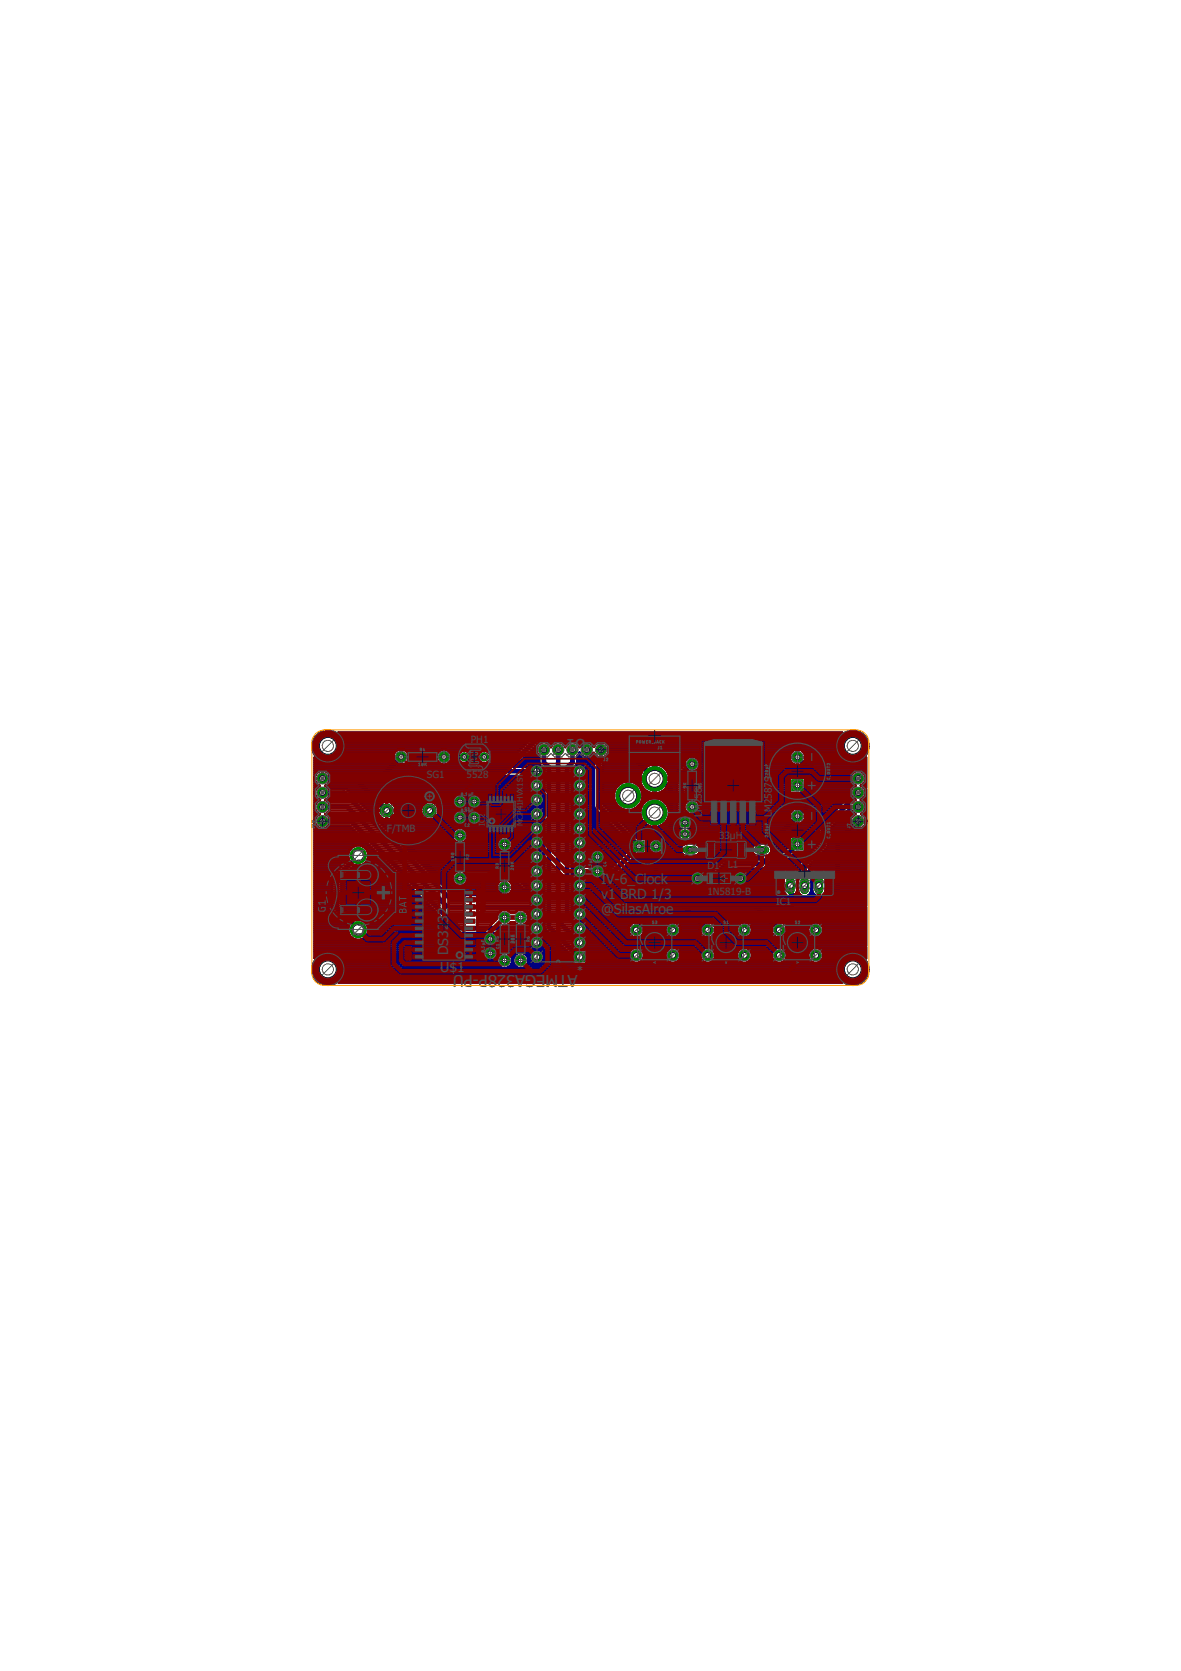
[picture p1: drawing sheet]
<svg xmlns="http://www.w3.org/2000/svg" width="210mm" height="297mm" viewBox="0 0 210 297" stroke-linecap="round" stroke-linejoin="round" font-family="sans-serif">
<defs><g id="words">
<g font-size="2.9" fill="#505050">
<text x="104.1" y="131.3" transform="rotate(-180 104.1 131.3)">U1</text>
<text x="102.7" y="173.3" transform="rotate(-180 102.7 173.3)">ATMEGA328P-PU</text>
</g>
<g font-size="2.5" fill="#505050">
<text x="106.8" y="157.2">IV-6_Clock</text>
<text x="106.8" y="159.8">v1 BRD 1/3</text>
<text x="79.7" y="166.8" transform="rotate(-90 79.7 166.8)">3</text>
<text x="79.7" y="165.4" transform="rotate(-90 79.7 165.4)">2</text>
<text x="79.7" y="164" transform="rotate(-90 79.7 164)">32</text>
<text x="106.8" y="162.5">@SilasAlroe</text>
<text x="78.2" y="172.8">U$1</text>
<text x="79.7" y="169.8" transform="rotate(-90 79.7 169.8)">D</text>
<text x="79.7" y="168.2" transform="rotate(-90 79.7 168.2)">S</text>
</g>
<g font-size="1.8" fill="#505050">
<text x="83.7" y="132">PH1</text>
<text x="75.9" y="138.4">SG1</text>
<text x="82.9" y="138.4">5528</text>
<text x="124.7" y="143" transform="rotate(-90 124.7 143)">2</text>
<text x="124.7" y="142" transform="rotate(-90 124.7 142)">5</text>
<text x="124.7" y="141" transform="rotate(-90 124.7 141)">8</text>
<text x="124.7" y="140" transform="rotate(-90 124.7 140)">7</text>
<text x="137.2" y="143" transform="rotate(-90 137.2 143)">2</text>
<text x="137.2" y="142" transform="rotate(-90 137.2 142)">5</text>
<text x="137.2" y="141" transform="rotate(-90 137.2 141)">8</text>
<text x="137.2" y="140" transform="rotate(-90 137.2 140)">7</text>
<text x="137.2" y="139.1" transform="rotate(-90 137.2 139.1)">S</text>
<text x="68.7" y="147.9">F/TMB</text>
<text x="124.7" y="145.2" transform="rotate(-90 124.7 145.2)">L</text>
<text x="124.7" y="144.3" transform="rotate(-90 124.7 144.3)">M</text>
<text x="127.8" y="149.1">3</text>
<text x="128.8" y="149.1">3</text>
<text x="129.7" y="149.1">µ</text>
<text x="130.8" y="149.1">H</text>
<text x="137.2" y="145.2" transform="rotate(-90 137.2 145.2)">L</text>
<text x="137.2" y="144.3" transform="rotate(-90 137.2 144.3)">M</text>
<text x="125.7" y="154.5">D1</text>
<text x="129.3" y="154.2">L1</text>
<text x="125.7" y="159.1">1N5819-B</text>
<text x="137.9" y="160.9">IC1</text>
<text x="139.8" y="158.7">A</text>
<text x="142.4" y="158.7">O</text>
<text x="144.9" y="158.7">I</text>
<text x="103.6" y="171.2" transform="rotate(-180 103.6 171.2)">*</text>
</g>
<g font-size="1.4" fill="#505050">
<text x="92.9" y="143.3" transform="rotate(-90 92.9 143.3)">1</text>
<text x="92.9" y="142.5" transform="rotate(-90 92.9 142.5)">H</text>
<text x="92.9" y="141.5" transform="rotate(-90 92.9 141.5)">V</text>
<text x="92.9" y="140.7" transform="rotate(-90 92.9 140.7)">X</text>
<text x="92.9" y="139.9" transform="rotate(-90 92.9 139.9)">1</text>
<text x="92.9" y="139.1" transform="rotate(-90 92.9 139.1)">S</text>
<text x="92.9" y="138.3" transform="rotate(-90 92.9 138.3)">T</text>
<text x="86.2" y="146.8" transform="rotate(-90 86.2 146.8)">I</text>
<text x="86.2" y="146.3" transform="rotate(-90 86.2 146.3)">C</text>
<text x="86.2" y="145.4" transform="rotate(-90 86.2 145.4)">2</text>
<text x="92.9" y="146.8" transform="rotate(-90 92.9 146.8)">M</text>
<text x="92.9" y="145.7" transform="rotate(-90 92.9 145.7)">C</text>
<text x="92.9" y="144.9" transform="rotate(-90 92.9 144.9)">P</text>
<text x="92.9" y="144.1" transform="rotate(-90 92.9 144.1)">4</text>
</g>
</g></defs>
<g fill="#000080" stroke="#000080" stroke-width=".18">
<path d="M56 170.5a2.88 2.88 0 0 1 4.6 .2 2.88 2.88 0 0 1-1.5 4.3 2.88 2.88 0 0 1-3.7-2.7h2.5a.35 .35 0 0 1 .5-.4 .35 .35 0 0 1 .1 .6 .35 .35 0 0 1-.6-.1l-2.5-.1 .1-.6z" fill-rule="evenodd"/>
<path d="M56 130.9a2.89 2.89 0 0 1 4.7 .1 2.89 2.89 0 0 1-1.5 4.4 2.89 2.89 0 0 1-3.8-2.7h2.5a.35 .35 0 0 1 .5-.4 .35 .35 0 0 1 .1 .6 .35 .35 0 0 1-.6-.2h-2.5l.1-.7z" fill-rule="evenodd"/>
<path d="M149.3 130.9a2.88 2.88 0 0 1 4.7 .1 2.88 2.88 0 0 1-1.6 4.4 2.88 2.88 0 0 1-3.7-2.7h2.5a.35 .35 0 0 1 .6-.3 .35 .35 0 0 1 0 .6 .35 .35 0 0 1-.6-.3h-2.5l.3-1.3z" fill-rule="evenodd"/>
<path d="M149.8 170.1a2.89 2.89 0 0 1 4.4 .9 2.89 2.89 0 0 1-2 4.1 2.89 2.89 0 0 1-3.5-2.8h2.5a.35 .35 0 0 1 .6-.2 .35 .35 0 0 1 0 .6 .35 .35 0 0 1-.6-.3l-2.5-.1a2.87 2.87 0 0 1 1.1-2.2z" fill-rule="evenodd"/>
</g>
<g fill="none" stroke="#000080" stroke-width=".83">
<path d="M63 138.4l6.7 6.6v2.6l11.1 11.1h7.9l1-1M71.3 134.6l-3.8 3.8h-10.2M78.9 134.6h3.6l2.5 2.5h10.4M86.1 134.6h6.1l3.2-3.2h7l4 4v7.9l7.2 7.1-4.5 4.5h-6.1M96.7 133.3v2.2l.9 .9v28.4l5.4 5.3M99.2 133.3v30.4l3.8 3.9M101.7 133.3v2.2l-.9 1v26.3l2.2 2.2M106.8 133.3h4.4l5.2 5.2h1l1.8 1.8v6.7l1.3 1.3M123 135.8l-1.9 1.7v8.1l.7 .6M141.7 134.6l2.6 2.5v5.4l-5.7 5.7-19.8 .1-2.2 2.1v5.7l9.2 9.2M57.3 140.9h3.8l19.1 19.1h15.2M57.3 143.4h4.5l17.8 17.8h14.6l1.2 1.3"/>
<path d="M57.3 146h5.1l19 19h14M63.7 152.1l-3.8 3.8v5.6l3.8 3.8M81.8 156.1l.6-.6h9.2l1.9 1.9h1.9M140.5 157.4v1.3l1.2 1.3M141.7 144.7v.4M141.7 160l-.9 .9h-23.3l-4.4 4.4M141.7 150.1l-2.2 2.2h-2.8l-1.3 1.3h-6.3l-2.6 2.5h-2.5M152.5 146l-3.6 3.3v8.6l-2.1 2.1h-5.1M152.5 140.9l-6.2 6.5v2.9l-3.3 3.3v3.8M134.1 160.9l4.4 4.4"/>
</g>
<g fill="none" stroke="#000080" stroke-width=".42">
<path d="M55.9 135.9h14.9M55.9 138.3a1.4 1.4 0 0 1 1.4-1.3 1.4 1.4 0 0 1 1.4 1.3h-2.8M55.9 137h1.2M55.9 138.5a1.49 1.49 0 0 0 .9 1.2 1.32 1.32 0 0 0-.9 1.3 1.32 1.32 0 0 0 1 1.2 1.33 1.33 0 0 0-.9 1.5M55.9 140h.4M55.9 139.6h.8M55.9 139.2h.3M55.9 138.9h.1M55.9 138.5h.1M55.9 138.1h.1M55.9 137.7h.2M55.9 137.4h.4"/>
<path d="M55.9 136.6h27.5M55.9 136.2h27.1M55.9 135.5h1.2M55.9 135.1h.6M55.9 134.7h.1M56.7 135.3l-.8-.6v35.6M56.7 135.3h.1M56.7 135.3l1 .4h1.1l1-.4M57.3 137v1.4h-1.4M57.3 138.1h.1M57.3 137.7h.1M57.3 137.4h.1"/>
<path d="M57.4 137v1.4h1.3a1.45 1.45 0 0 1-.9 1.3l.6 .4h2.9l.3 .1 18.9 18.9h14l.7-.4M57.5 137h26.3M58 139.6h36.2M58.3 140h35.9M58.3 137.4h25.9M58.4 139.2h35.8M58.6 137.7h25.9M58.6 138.9h35.8M58.7 138.1h36M58.7 138.5h36.2M59.4 135.5h10.8M59.8 135.3h.1"/>
<path d="M60.1 135.1h9.9M60.5 134.7h9.4M60.6 130.6h34.5M60.6 134.6v.1M60.6 134.6l-.8 .7M60.6 130.7l.6 .9 .2 1.1M60.6 130.7h.1M60.6 130.7l-.5-.4h89.6l-.5 .4M60.8 134.4h9.1M60.8 131h33.9M61 134h9M61 131.4h33.3"/>
<path d="M61.2 133.7h.1M61.2 133.7l-.6 .9M61.2 133.6h9.1M61.2 131.7h32.7M61.3 133.2h9.5M61.3 132.1h32.2M61.3 132.9h31.5M61.3 132.5h31.9M61.4 132.7l-.2 1M61.4 132.7h.1M69.9 134.6h2.8M69.9 134.5h2.8"/>
<path d="M70 134a1.39 1.39 0 0 1 1.3-.8 1.39 1.39 0 0 1 1.3 .8M70 134l-.1 .5 .1 .6M70 135.1a1.38 1.38 0 0 0 1.8 .8M71.3 135.9h.1M71.3 133.2h.1M71.3 133.2v2.8M71.3 135.5h.1M71.3 135.1h.1M71.3 134.7h.1M71.3 134.4h.1M71.3 134h.1M71.3 133.6h.1"/>
<path d="M71.7 133.2h6.9M71.8 135.9h6.7M72.3 133.6h5.6M72.3 135.5h5.6M72.3 135.5l-.5 .4M72.6 135.1h5.1M72.6 134h5.1M72.6 135.1l-.3 .4M72.6 134l.1 .5-.1 .6M72.7 134.7h4.9M72.7 134.4h4.9M79.2 133.2h13.2"/>
<path d="M79.3 135.9h3.4M79.9 133.6h2M79.9 135.5h2M83.1 133.6h2.4M83.1 133.6a1.06 1.06 0 0 0-1.3 .2h-1.8a1.37 1.37 0 0 0-2-.2 1.37 1.37 0 0 0 0 2 1.37 1.37 0 0 0 2-.2h1.8l.7 .3 1.9 1.9M83.1 133.6l.5 .7M83.5 134h1.6M83.6 134.3v.2l1.8 1.8h9.1l.7-.4M83.6 134.4h1.4M83.8 134.7h1.2M84.2 135.1h.9M84.4 137.6l.5 .3h9.6a1.25 1.25 0 0 0 1.6 .2 1.25 1.25 0 0 0 .4-1.6l.3 .2v28.2l.3 .6 4.7 4.6v1l.2 .2h2l.3-.2v-2l-.3-.3h-1.3"/>
<path d="M84.4 137.6h.1M84.6 135.5h.8M85 134.3a1.12 1.12 0 0 0 .5 1.2 1.12 1.12 0 0 0 1.3-.1h5.6l.3-.1 3.2-3.1a1.35 1.35 0 0 0 0 2.2M85 135.9h10.9M85.3 136.2h9.2M86.7 133.6h5.3M86.7 133.6a1.13 1.13 0 0 0-1.7 .7M86.7 135.5h9.2M92.8 135.1h3.1M93.2 134.7h2.7M93.6 134.4h2.2M94 134h1.5"/>
<path d="M94.3 133.6h1.1M94.7 133.2h.6M95.1 132.9h.3M95.4 132.5h.2M95.9 134.4v1.3l.1 .3-.3-.1M95.9 138.5h.9M96.2 138.1h.6M96.4 138.9h.4M96.5 137.7h.3M96.5 136.6h.1M96.6 139.2h.2M96.6 140h.2"/>
<path d="M96.6 137h.2M96.6 139.6h.2M96.6 137.4h.2M101.6 137h.2M101.6 140h.2M101.6 139.6h.2M101.6 139.2h.2M101.6 138.9h.4M101.6 138.5h1M101.6 138.1h.7M101.6 137.7h.3M101.6 137.4h.2"/>
<path d="M101.8 136.6h.1M102.5 135.9h3.1M102.6 134.4l.4-.6a1.31 1.31 0 0 0 1.5 .8l1.1 1.1v7.7l.1 .3M102.6 134.4v1.3l-.2 .3 .4-.1M102.6 135.5h2.7M102.6 135.1h2.4M102.6 134.7h2M102.6 134.4h.9M102.7 130.6h46.6M102.9 134h.2M103.1 130.9l1 1.1a1.32 1.32 0 0 1 1.4 .8M103.1 130.9v.1"/>
<path d="M103.1 130.9l-.5-.3h-7.4l-.2 .1-3.1 3.1h-5.1l-.1-.2M103.1 131h45.9M103.3 135.9a1.26 1.26 0 0 1 .9 1.6 1.26 1.26 0 0 1-1.7 .8 1.26 1.26 0 0 1-.6-1.8l-.3 .3v25.7l.2 .1a1.26 1.26 0 0 1 1.5-1.3 1.26 1.26 0 0 1 .8 1.9M103.5 138.5h2.1M103.5 131.4h45.3M103.8 138.1h1.8M103.9 131.7h44.8M103.9 136.2h1.7M104 138.9h1.6M104.1 137.7h1.5M104.2 136.6h1.4M104.2 139.2h1.4"/>
<path d="M104.2 140h1.4M104.3 137h1.3M104.3 139.6h1.3M104.3 137.4h1.3M105 132.1h1.1M105.4 132.5h.3M105.5 132.8a1.38 1.38 0 0 1 1.3-.9v1.3h34.5M105.5 132.8h.1M106.8 134.4h.1M106.8 134h.1M106.8 133.6h.1M106.8 132.9h.1"/>
<path d="M106.8 132.5h.1M106.8 132.1h.1M106.9 134.7h15.3M107.1 135.1h14.8M107.2 135.9h8.8M107.2 137h7M107.2 140h2.3M107.2 139.6h2.7M107.2 139.2h3.2M107.2 138.9h6.6M107.2 138.5h8.9M107.2 138.1h6.5"/>
<path d="M107.2 137.7h6.6M107.2 137.4h6.8M107.2 136.6h7.3M107.2 136.2h7.8M107.2 135.5h14.5M107.6 132.1l-.7-.2v2.8l.7-.2 .4-.5M107.6 132.1l.4 .5 .2 .6M107.6 132.1h41M107.7 134.4h32.6M108 132.5h40.5M108 134h32.5M108.2 132.9h40.3"/>
<path d="M108.2 133.6v-.3h-1.4v1.3l.4 .6v7.7l6.2 6.2h1.2l.3 .3v2.1l-.3 .2h-1.2l-3.8 3.9-.3 .1M108.2 133.6l-.2 .4M108.2 133.6h32.5M112.9 139.2h1M113.4 139.6h.6M113.8 140h.4M113.8 137.7l-.1 .5h5.3l-.1-.5M113.8 137.7a2.57 2.57 0 0 1 2.3-1.9v5.3l-1-.4M116.1 135.9h.5M116.1 137h.5M116.1 140h.5M116.1 139.6h.5"/>
<path d="M116.1 139.2h.5M116.1 138.9h.5M116.1 138.1h.5M116.1 137.7h.5M116.1 137.4h.5M116.1 136.6h.5M116.1 136.2h.5M116.6 138.5h3.7M116.8 135.9h4.9M117.8 136.2h3.5M118.2 136.6h2.7M118.5 140h1.8"/>
<path d="M118.5 137h1.9M118.7 139.6h1.6M118.7 137.4h1.6M118.9 139.2h1.4M118.9 137.7a2.65 2.65 0 0 0-2.3-1.9v5.3a2.62 2.62 0 0 0 2.4-2.4h-5.3a2.6 2.6 0 0 0 1.4 2M118.9 137.7h1.4M118.9 138.9h1.4M118.9 138.1h1.4M120.4 137l-.1 .5v8.3l.3 .5v.8M120.5 137h-.1M121.9 140h18.5M121.9 139.6h18.5"/>
<path d="M121.9 139.2h18.5M121.9 138.9h18.5M121.9 138.5h18.5M121.9 138.1h29.3M122 137.7h29.3M122.5 137.4h29.1M122.7 137.2l-.8 .6v4.8a1.36 1.36 0 0 1 1.7-.4 1.36 1.36 0 0 1 .8 1.5M122.7 137.2h.1M123.7 137h30.2M123.8 134.7h16.5M124.1 136.6h29.8M124.2 136.6a1.36 1.36 0 0 0-.8-2.1 1.36 1.36 0 0 0-1.7 1.4l-1.2 1.1"/>
<path d="M124.2 136.6l-.4 .4-.5 .2h-.6M124.2 135.1h16.2M124.3 136.2h29.6M124.3 135.5h16.3M124.4 135.9h16.7M140.3 134.6h2.9M140.7 133.7l.5-.4 .5-.1v2.8a1.41 1.41 0 0 1-1.3-.8 1.41 1.41 0 0 1 .3-1.5zM141.7 135.9h.1M141.7 133.2h.1M141.7 135.5h.1M141.7 135.1h.1M141.7 134.7h.1"/>
<path d="M141.7 134.4h.1M141.7 134h.1M141.7 133.6h.1M141.8 133.2a1.42 1.42 0 0 1 1.4 1.4 1.42 1.42 0 0 1-1.4 1.4zM142.2 133.2h6.4M142.4 135.9h11.5M142.8 133.6h5.9M142.9 135.5h7.6M143 134h5.8M143.1 135.1h6.7M143.1 140h8.5M143.1 139.6h8.9"/>
<path d="M143.1 139.2h8.4M143.1 138.9h8.2M143.1 138.5h8.1M143.2 134.7h6.1M143.2 134.4h5.9M148.5 132.7h.1M148.5 132.7l.2 1M148.7 131.6h.1M148.7 133.7h.1M148.7 131.6l-.2 1.1M148.7 133.7l.5 .9M149.2 130.7h.1"/>
<path d="M149.2 134.6v.1M149.2 130.7l-.5 .9M149.2 134.6h.1M149.2 134.6l.8 .7M150 135.3h.1M150 135.3l1 .4h1.1l1-.4M151.2 138.1a1.29 1.29 0 0 0 .9 1.5 1.29 1.29 0 0 0-.9 1.6l-5.6 5.8-.1 .3v2.6l-3.2 3.2-.1 .3v2.4l-.4 .6v2a1.2 1.2 0 0 0 1.2 1 1.2 1.2 0 0 0 1.2-1v-2l-.4-.6v-1.9l3.2-3.2 .2-.3v-2.7l1.2-1.2M151.2 138.1a1.37 1.37 0 0 1 1.3-1.1 1.37 1.37 0 0 1 1.4 1.1M152.7 135.5h1.2M153.1 139.6h.8M153.1 135.3h.1M153.1 135.3l.8-.6v35.6"/>
<path d="M153.4 135.1h.5M153.4 137.4h.5M153.5 140h.4M153.6 139.2h.3M153.7 137.7h.2M153.8 138.9h.1M153.8 134.7h.1M153.9 138.1a1.33 1.33 0 0 1-.9 1.5 1.34 1.34 0 0 1 .9 1.3 1.34 1.34 0 0 1-.9 1.3 1.34 1.34 0 0 1 .9 1.5M153.9 138.5h.1M153.9 138.1h.1M55.9 143.7h.1M55.9 146h.1"/>
<path d="M55.9 145.6h.1M55.9 156.1h3.2M55.9 155.7h3.2M55.9 141.9h.5M55.9 148.2h7.6M55.9 155.3h3.4M55.9 153.1h5.6M55.9 142.6h.4M55.9 158.7h3.2M55.9 152.3h6M55.9 159.8h3.2M55.9 159.4h3.2"/>
<path d="M55.9 159.1h3.2M55.9 158.3h3.2M55.9 157.9h3.2M55.9 157.6h3.2M55.9 157.2h3.2M55.9 156.8h3.2M55.9 156.5h3.2M55.9 155h3.7M55.9 154.6h4.1M55.9 154.2h4.5M55.9 153.8h4.8M55.9 153.5h5.2"/>
<path d="M55.9 152.7h6M55.9 152h6M55.9 151.6h6M55.9 151.2h6.2M55.9 150.8h6.5M55.9 150.5h7M55.9 150.1h9.5M55.9 149.7h9.1M55.9 149.4h8.7M55.9 149h8.3M55.9 148.6h8M55.9 147.8h7.2"/>
<path d="M55.9 147.5h6.8M55.9 147.1h.6M55.9 146.7h.3M55.9 146.3h.1M55.9 145.2h.3M55.9 144.8h.7M55.9 144.5h.6M55.9 144.1h.2M55.9 143.4h.1M55.9 143h.1M55.9 142.2h.8M55.9 141.5h.2"/>
<path d="M55.9 141.1h.1M55.9 140.7h.1M55.9 140.4h.2M56 143.7l.2 .5 .7 .5-.3 .1M56.2 145.2a1.36 1.36 0 0 0 .3 1.9 1.36 1.36 0 0 0 1.9-.3h3.7l18.9 18.9 .3 .1M56.6 144.8l-.4 .4M58.1 147.1h4.3M59.4 155.2h.1M60.7 158.7h13.3M60.7 159.8h14.4M60.7 159.4h14M60.7 159.1h13.6"/>
<path d="M60.7 158.3h12.9M60.7 157.9h12.5M60.7 157.6h12.2M60.7 157.2h11.8M60.7 156.8h11.4M60.7 156.5h11M60.8 156.1h10.6M61.2 155.7h9.8M61.6 155.3h9M61.7 140.4h32.7M61.9 155h8.3M62.1 140.7h32.7"/>
<path d="M62.3 154.6h7.5M62.5 141.1h32.2M62.7 154.2h6.8M62.8 141.5h18.2M63.1 153.8h.1M63.2 141.9h17.4M63.6 142.2h16.9M64 142.6h4.1M64.1 153.8h5M64.3 143h3.4M64.5 150.5h1.2M64.7 143.4h2.6"/>
<path d="M64.8 153.5h3.9M65 150.8h1.1M65.1 143.7h2.1M65.2 153.1a1.77 1.77 0 0 1-2.1 .7l-2.4 2.4v4.9l2.4 2.5a1.81 1.81 0 0 1 2.4 1.5 1.81 1.81 0 0 1-2 2 1.81 1.81 0 0 1-1.5-2.4M65.2 153.1h3.1M65.2 153.1a1.82 1.82 0 0 0-1.3-2.8 1.82 1.82 0 0 0-1.9 2.3l-2.8 2.8-.1 .3v5.9l.1 .3 2.8 2.8M65.3 151.2h1.2M65.3 152.7h2.7M65.4 151.6h1.4M65.5 152.3h2.1M65.5 152h1.7M65.5 144.1h3.2"/>
<path d="M65.8 144.5h1.4M66.2 144.8h1.1M66.6 145.2h1.1M67 145.6h13.5M67.4 146h13.2M67.7 146.3h13.2M68.1 146.7h26.2M68.1 145.6l-.9-.9v-.6h3.1v.6l-.9 .9M68.5 147.1h25.7M68.7 143.7h.1M68.7 145.6v-3h-.6l-.9 .8v.6h3.1v-.6l-.9-.8h-.6v3M68.7 142.6h.1"/>
<path d="M68.7 145.2h.1M68.7 144.8h.1M68.7 144.5h.1M68.7 143.4h.1M68.7 143h.1M68.8 144.1h6.1M68.8 147.5h12.1M69.2 147.8h11.4M69.4 142.6h11.1M69.6 148.2h10.8M69.8 145.2h5.6M69.8 143h5.6"/>
<path d="M70 148.6h10.4M70.1 144.8h4.9M70.2 143.4h4.8M70.3 143.7h4.6M70.3 144.5h4.6M70.3 149h10.2M70.7 149.4h10M71.1 149.7h10M71.5 150.1h16.8M71.8 150.5h16.6M72.2 150.8h16.3M72.6 151.2h16.3"/>
<path d="M73 151.6h21.4M73.3 152h20.9M73.7 152.3h20.5M74.1 152.7h20.1M74.5 153.1h19.9M74.8 153.5h20.1M75.2 153.8h19.4M75.6 154.2h18.7M75.8 142.6l-.9 .9v1.2l.9 .9h1.2l.9-.9v-1.2l-.9-.9M75.9 154.6h18.2M76.3 155h4.8M76.7 155.3h4"/>
<path d="M77.1 155.7h3.4M77.3 145.2h3.2M77.4 143h3.2M77.4 156.1h3M77.7 144.8h2.9M77.7 143.4h3.1M77.8 156.5h2.6M77.9 143.7h3.5M77.9 144.5h2.9M77.9 144.1h3.5M78.2 156.8h2.4M78.6 157.2h2.3"/>
<path d="M79 157.6h9.3M79.3 157.9h9M79.7 158.3h8.7M80.1 158.7h8.6M80.4 148.3a1.37 1.37 0 0 0 1.4 1.6 1.37 1.37 0 0 0 1.3-1.6M80.4 148.3a1.37 1.37 0 0 1 1.4-1.2 1.37 1.37 0 0 1 1.3 1.2M80.5 159.1h8.8M80.5 142.5h2.5M80.5 142.6l.1 .4M80.5 145.3h2.5M80.5 145.4h2.5M80.6 143l.2 .3"/>
<path d="M80.6 155.4l.4-.4 .5-.2 .7-.1h9.6l.3 .1 1.7 1.8h.7a1.25 1.25 0 0 1 1.8-.1 1.25 1.25 0 0 1 0 1.8 1.25 1.25 0 0 1-1.8-.1h-1.2l-.3-.1-1.8-1.8h-8.1a1.36 1.36 0 0 1-1.8 1.1 1.36 1.36 0 0 1-.7-2zM80.8 143.3a1.31 1.31 0 0 0 1.9 0M81.4 144.1a1.28 1.28 0 0 0-.5 2.2 1.28 1.28 0 0 0 2.1-.8M81.4 144.1h.7M81.7 141.2v2.6M81.7 144.1v2.5M81.7 143.7h.1M81.7 146h.1M81.7 145.6h.1M81.7 141.9h.1M81.7 142.6h.1M81.7 146.3h.1"/>
<path d="M81.7 145.2h.1M81.7 144.8h.1M81.7 144.5h.1M81.7 144.1h.1M81.7 143.4h.1M81.7 143h.1M81.7 142.2h.1M81.7 141.5h.1M81.8 141.2v2.6M81.8 144.1v2.5M82.1 144.1a1.29 1.29 0 0 1 .9 1.1M82.1 144.1h12.2"/>
<path d="M82.1 143.7h12.5M82.4 149.7h6M82.5 141.5h1.1M82.6 146.3h.9M82.6 157.2h5.8M82.6 147.5h11.6M82.7 144.5h.7M82.7 143.4h.7M82.8 149.4h5.8M82.9 141.9h.3M82.9 146h.3M82.9 156.8h5.7"/>
<path d="M82.9 147.8h11.4M82.9 144.8h.3M83 143l-.3 .3M83 143h.2M83 145.6h.1M83 142.2h.1M83 142.4a1.29 1.29 0 0 0-1.3-1.2 1.29 1.29 0 0 0-1.2 1.4M83 142.6v.4M83 142.6h.1M83 149h5.9M83 145.2h.1M83.1 145.6a1.26 1.26 0 0 1 1.2-1.5 1.26 1.26 0 0 1 1.2 1.5"/>
<path d="M83.1 145.6a1.27 1.27 0 0 0 1.2 1 1.27 1.27 0 0 0 1.2-1M83.1 148.2h11.5M83.1 156.5h6M83.1 148.6h11.9M84.1 143.7a1.25 1.25 0 0 1-.8-1.9 1.25 1.25 0 0 1 2 0 1.25 1.25 0 0 1-.8 1.9M85 141.5h9.3M85 146.3h9.6M85.2 144.5h9M85.2 143.4h9.8M85.4 146h11.4M85.4 141.9h8.8M85.4 144.8h8.8"/>
<path d="M85.4 143h9M85.5 142.2h8.7M85.5 145.6h9M85.5 142.6h8.7M85.5 145.2h8.8M88.3 157.8h2.8M88.3 157.7h2.8M88.3 157.6a1.43 1.43 0 0 0 1.1 1.5M88.4 157.2l-.1 .4M88.6 149.4a1.36 1.36 0 0 0 1.1 2.1 1.36 1.36 0 0 0 1.1-2.1M88.6 156.8l-.2 .4M88.9 149l.5-.2h.6l.4 .2"/>
<path d="M88.9 149l-.3 .4M89.4 159.1h.2M89.6 156.3l-.4 .1-.6 .4M89.7 156.3v2.8M89.7 158.7h.1M89.7 159.1h.1M89.7 158.3h.1M89.7 157.9h.1M89.7 157.6h.1M89.7 157.2h.1M89.7 156.8h.1M89.7 156.5h.1"/>
<path d="M89.8 156.3l.4 .1 .6 .4M90 159.1h-.2M90 159.1h4.5M90.3 156.5h1.1M90.4 149l.4 .4M90.4 149h4.1M90.5 151.2h4.3M90.7 158.7h6.1M90.8 156.8l.2 .4M90.8 156.8h1M90.8 149.4h3.4M90.8 150.8h3.9"/>
<path d="M91 158.3h3.6M91 157.2l.1 .4M91 157.2h1.1M91 150.5h3.3M91 149.7h3.2M91 150.1h3.2M91.1 157.9h1.8M91.1 157.6a1.38 1.38 0 0 1-1.1 1.5M91.1 157.6h1.4M92.2 155h1.9M92.6 155.3h1.6M92.9 155.7h1.5"/>
<path d="M93.3 156.1h1.7M93.7 156.5h.9M94.1 155h2.6M94.1 155a1.31 1.31 0 0 0 1.2 1.2M94.3 141.5a1.27 1.27 0 0 0 1.1 1.9 1.27 1.27 0 0 0 1.1-1.9M94.3 150.5a1.27 1.27 0 0 1 1.1-2 1.27 1.27 0 0 1 1.1 2M94.3 150.5l.4 .4M94.3 141.5a1.27 1.27 0 0 1 2.2 0M94.7 150.9l.5 .1h.5l.4-.1M95.2 146a1.27 1.27 0 0 1-.9-2 1.27 1.27 0 0 1 2.2 0 1.27 1.27 0 0 1-.8 2M95.3 153.6a1.31 1.31 0 0 0-1.2 1.2h2.6a1.26 1.26 0 0 0-1.2-1.2v2.6a1.31 1.31 0 0 0 1.2-1.2M95.3 153.6v2.6"/>
<path d="M95.3 156.1h.2M95.3 155.7h.2M95.3 155.3h.2M95.3 155h.2M95.3 154.6h.2M95.3 154.2h.2M95.3 153.8h.2M95.7 158.7a1.25 1.25 0 0 1 1 1.4 1.25 1.25 0 0 1-1.5 1.1 1.32 1.32 0 0 1 1.3 2M95.8 148.6h1M95.8 143.4h1M95.9 156.1h.9M95.9 153.5h.9"/>
<path d="M96 151.2h.8M96 140.7h.8M96.1 141.1h.7M96.1 150.8h.7M96.2 143.7h.6M96.2 153.8h.6M96.2 148.2h.6M96.2 156.5h.6M96.2 158.3h.6M96.3 146.3h.5M96.3 145.6h.5M96.3 159.1h.5"/>
<path d="M96.3 149h.5M96.4 143h.4M96.4 155.7h.4M96.4 153.1h.4M96.4 151.6h.4M96.4 140.4h.4M96.5 150.5l-.4 .4M96.5 141.5h.3M96.5 150.5h.3M96.5 147.8h.3M96.5 144.1h.3M96.5 157.9h.3"/>
<path d="M96.5 156.8h.3M96.5 154.2h.3M96.5 159.4h.3M96.5 146.7h.3M96.5 145.2h.3M96.6 149.4h.2M96.6 142.6h.2M96.6 152.7h.2M96.6 152h.2M96.6 141.9h.2M96.6 155.3h.2M96.6 150.1h.2"/>
<path d="M96.6 152.3h.2M96.6 159.8h.2M96.6 157.6h.2M96.6 157.2h.2M96.6 149.7h.2M96.6 147.5h.2M96.6 147.1h.2M96.6 144.8h.2M96.6 144.5h.2M96.6 142.2h.2M96.7 154.6h.1M96.7 155h.1"/>
<path d="M101.6 143.7h.7M101.6 146h6.3M101.6 145.6h.6M101.6 156.1h1.1M101.6 155.7h.5M101.6 141.9h.2M101.6 148.2h.6M101.6 155.3h.3M101.6 153.1h.4M101.6 142.6h.3M101.6 158.7h37.8M101.6 152.3h1.4"/>
<path d="M101.6 159.8h.2M101.6 159.4h.3M101.6 159.1h.5M101.6 158.3h.6M101.6 157.9h.3M101.6 157.6h.2M101.6 157.2h.2M101.6 156.8h.3M101.6 156.5h.6M101.6 155h.2M101.6 154.6h.2M101.6 154.2h.3"/>
<path d="M101.6 153.8h.7M101.6 153.5h.8M101.6 152.7h.2M101.6 152h.2M101.6 151.6h.4M101.6 151.2h.8M101.6 150.8h.7M101.6 150.5h.4M101.6 150.1h.2M101.6 149.7h.2M101.6 149.4h.3M101.6 149h.5"/>
<path d="M101.6 148.6h1.1M101.6 147.8h.3M101.6 147.5h.2M101.6 147.1h.2M101.6 146.7h.3M101.6 146.3h.6M101.6 145.2h.3M101.6 144.8h.2M101.6 144.5h.2M101.6 144.1h.3M101.6 143.4h1M101.6 143h.5"/>
<path d="M101.6 142.2h.2M101.6 141.5h.4M101.6 141.1h.8M101.6 140.7h.8M101.6 140.4h.4M102 150.5a1.27 1.27 0 0 1 .8-1.9 1.27 1.27 0 0 1 1.5 1.4 1.27 1.27 0 0 1-2 .9M102 150.5l.3 .4M102 141.5a1.27 1.27 0 0 0 1 2 1.27 1.27 0 0 0 1.1-2M102 140.4a1.28 1.28 0 0 1 1-2 1.28 1.28 0 0 1 1.1 2M102 140.4a1.29 1.29 0 0 0 2.1 0M102.8 146a1.27 1.27 0 0 1-.8-2 1.27 1.27 0 0 1 2.1 0 1.27 1.27 0 0 1-.8 2M102.8 158.7a1.26 1.26 0 0 0-.8 2 1.26 1.26 0 0 0 2.1 0 1.26 1.26 0 0 0-.8-2"/>
<path d="M102.9 151a1.31 1.31 0 0 0-1.2 1.3h2.6a1.26 1.26 0 0 0-1.2-1.3M102.9 153.6a1.31 1.31 0 0 1-1.2-1.2h2.6a1.26 1.26 0 0 1-1.2 1.2M103 153.1h.1M103 151v2.6M103 153.5h.1M103 152.7h.1M103 152h.1M103 151.6h.1M103 151.2h.1M103.1 151v2.6M103.1 152.3h7.4M103.3 156.1h2.6"/>
<path d="M103.4 148.6h7.2M103.4 143.4h2.2M103.6 140.7h2M103.7 153.5h1.9M103.7 151.2h1.9M103.7 141.1h1.9M103.7 141.1a1.25 1.25 0 0 0-1.7 .4M103.7 141.1l.4 .4M103.7 153.8h1.8M103.7 150.8h8.3M103.8 143.7h1.9M103.8 148.2h6.4"/>
<path d="M103.8 156.5h18.9M103.9 158.3h35.4M103.9 146.3h4.4M103.9 145.6h3.7M103.9 159.1h35.8M103.9 155.7h1.4l.7 .4h16.7M103.9 149h7.1M104 143h1.6M104.1 140.4h1.5M104.1 153.1h1.1M104.1 151.6h1.1M104.1 141.5h1.5"/>
<path d="M104.1 150.5h8.2M104.1 156.8h18.8M104.1 147.8h5.7M104.1 144.1h2M104.1 157.9h35.2M104.1 146.7h4.6M104.2 159.4h49.7M104.2 145.2h3M104.2 142.6h1.4M104.2 149.4h7.1M104.2 141.9h1.4M104.2 150.1h7.9"/>
<path d="M104.3 159.8h49.6M104.3 157.6h35M104.3 157.2h19M104.3 152.7h.7M104.3 152h.7M104.3 149.7h7.4M104.3 147.5h5.2M104.3 147.1h4.8M104.3 144.8h2.5M104.3 144.5h2.1M104.3 142.2h1.3M104.9 152.4h2.6"/>
<path d="M105.5 153.8l-.2 .3h-1.3a1.26 1.26 0 0 0-1.9-.2 1.26 1.26 0 0 0 0 1.9 1.26 1.26 0 0 0 1.9-.1M105.5 153.8l.5-.2 .9 .2M105.7 143.7l.2 .3M105.9 144h.1M105.9 144l6.4 6.3v.3l-3.5 3.5h-1.7l-.2-.3M106.2 153.1h.1M106.2 151v2.6M106.2 153.5h.1M106.2 152.7h.1M106.2 152h.1M106.2 151.6h.1M106.2 151.2h.1"/>
<path d="M106.8 153.5h2.6M106.8 151.2h4.8M106.9 153.8h2.1M107.1 155.7h15.7M107.1 155.7l-.7 .4M107.2 141.9h1.9M107.2 142.6h2.2M107.2 142.2h2M107.2 141.5h1.9M107.2 141.1h1.9M107.2 140.7h2M107.2 140.4h2.1"/>
<path d="M107.2 153.1h2.5M107.3 151.6h4M107.3 143h2.3M107.4 152.7h2.7M107.4 152h3.5M107.6 143.4h2.3M108 143.7h2.5M108.4 144.1h5.4M108.8 144.5h5M109.1 141.1a2.58 2.58 0 0 0 2.6 2.9 2.58 2.58 0 0 0 2.5-2.9M109.1 141.1a2.58 2.58 0 0 1 2.6-2.2 2.58 2.58 0 0 1 2.5 2.2M109.1 144.8h4.7"/>
<path d="M109.5 145.2h4.4M109.8 155.3h13.2M109.9 145.6h4.1M110.2 155h13.3M110.3 146h4M110.6 154.6h16.3M110.6 146.3h4M110.9 154.2h16.4M111 146.7h4.2M111.3 153.8h16.4M111.4 147.1h9.2M111.7 153.5h16.3"/>
<path d="M111.8 147.5h9.1M112.1 153.1h16.3M112.1 147.8h8.6M112.4 152.7h22.7M112.5 148.2h33M112.8 152.3h22.7M112.8 143.7h1.1M112.9 148.6h7.7M113.2 152h8.2M113.2 149h7.6M113.4 143.4h.6M113.7 143h.5"/>
<path d="M113.8 144.1a2.58 2.58 0 0 0 2.6 2.9 2.58 2.58 0 0 0 2.5-2.9M113.9 142.6h.7M114 140.4h.6M114.1 142.2h1M114.1 140.7h1M114.2 141.9h6.1M114.2 141.5h6.1M114.2 141.1h6.1M114.7 151.6h1.2M114.8 149.4h1M114.9 151.2h.6M114.9 150.8h.4"/>
<path d="M114.9 150.5h.4M114.9 150.1h.4M114.9 149.7h.6M115.3 150.4h2.7M115.3 150.5h2.7M115.3 150.1a1.35 1.35 0 0 1 1.3-1 1.35 1.35 0 0 1 1.3 1M115.3 150.1a1.35 1.35 0 0 0 1.3 1.7 1.35 1.35 0 0 0 1.3-1.7M116 141.9a2.59 2.59 0 0 0-2.2 2.2M116.1 140.7h.5M116.1 140.4h.5M116.6 149.1v2.7M116.6 151.6h.1"/>
<path d="M116.6 151.2h.1M116.6 150.8h.1M116.6 150.5h.1M116.6 150.1h.1M116.6 149.7h.1M116.6 149.4h.1M116.7 141.9a2.59 2.59 0 0 1 2.2 2.2M117.3 151.6h3.8M117.4 149.4h3.9M117.5 146.7h3.1M117.6 142.2h2.7M117.6 140.7h2.7"/>
<path d="M117.7 151.2h3.3M117.8 149.7h22.6M117.9 150.8h3.1M117.9 150.1h3.7M118 150.5h3.1M118.1 146.3h2.5M118.1 142.6h2.2M118.2 140.4h2.1M118.4 146h2M118.5 143h1.8M118.6 145.6h1.7M118.7 143.4h1.6"/>
<path d="M118.8 143.7h1.5M118.8 145.2h1.5M118.9 144.8h1.4M118.9 144.5h1.4M118.9 144.1h1.4M120.6 148.3h2.3M120.6 147.1l.4 .2-.3 .5M120.7 147.8a1.17 1.17 0 0 0 .6 1.6M121 150.9v.4l.4 .7M121 150.9l.4-.7 .4-.2h1.8l.7 .5 .1 .4M121.3 149.4h.9M121.4 152l.4 .1h1.8l.4-.1"/>
<path d="M121.7 148.3v1.1M121.7 149.4h.1M121.7 149h.1M121.7 148.6h.1M121.8 148.3v1.1M121.9 141.9h28.6M121.9 142.6h.1M121.9 144.8h18.4M121.9 144.5h.3M121.9 142.2h.5M121.9 141.5h29M121.9 141.1h29.3"/>
<path d="M121.9 140.7h18.5M121.9 140.4h18.5M122.2 149.4h18.2M122.6 147.5h22.9M122.7 149h17.7M122.7 145.2h17.6M122.8 147.8a1.17 1.17 0 0 1-.6 1.6M122.8 147.8h22.7M122.9 146h17.7M122.9 145.6h17.5M122.9 147.1l-.5 .2 .4 .5M122.9 147.1h22.7"/>
<path d="M122.9 146.7h23M122.9 146.3h18.2M122.9 148.6h22.6M123.3 157.2l.4 .2h.5l.5-.2M123.6 142.2h26.6M123.8 150.1h10.5M123.9 144.5h16.5M124 152h10.1M124.1 142.6h25.7M124.2 144.1h16.5M124.3 150.5h9.5M124.3 143h25.2"/>
<path d="M124.3 151.6h9.5M124.4 143.7h16.9M124.4 143.7a1.36 1.36 0 0 1-1.1 1.1 1.36 1.36 0 0 1-1.4-.5v.8h.7l.3 .3v1.7M124.4 143.4h24.7M124.4 155h2.1M124.4 150.9l-.1 .8-.3 .3M124.4 151.2h9.3M124.4 150.8h9.3M124.7 157.2h6.2M127 156.8l-.3 .2h-1.8l-.2 .2M127 156.8h3.5M127.3 156.5h3.1"/>
<path d="M127.7 156.1h2.6M128.1 155.7h2.3M128.5 155.3h2.1M128.8 155h2.3M129.2 154.6h13M130.9 157.2a1.28 1.28 0 0 1-.3-1.9 1.28 1.28 0 0 1 1.9 0 1.28 1.28 0 0 1-.2 1.9M130.9 157.2l.4 .2h.5l.5-.2M132 155h10.2M132.3 157.2h7M132.6 155.3h9.6M132.7 156.8h6.6M132.8 155.7h6.9"/>
<path d="M132.8 156.5h6.5M132.8 156.1h6.6M133.7 150.9l.1-.4 .7-.5h1.8l.6 .5 .2 .4M133.7 150.9v.4l.4 .7M134.1 152l.4 .1h1.2l-.6 .7h-6.2l-.3 .1-2.4 2.4h-1.3a1.27 1.27 0 0 0-1.9 0 1.27 1.27 0 0 0 .3 1.9M135.9 154.2h6.3M136.3 153.8h5.9M136.5 150.1h3.9M136.7 153.5h5.5M137 150.5h3.2M137.1 150.9l-.1 .6h2.2l1.2-1.2v-1.4l.2-.2h2.3l.2 .2v2.3M137.1 151.2h2.3"/>
<path d="M137.1 150.8h2.7M139.6 155.9l.4-.4 .4-.1v4a1.23 1.23 0 0 1-1.1-1.1v-.8h2.4v.8a1.23 1.23 0 0 1-1.2 1.1v-4a1.23 1.23 0 0 1 1.2 1.1v.9h-2.4v-1zM139.7 153.1h2.7M140.3 152.7h2.4M140.3 145.1h2.9M140.4 140.7v-2.2l.2-.3h2.3l.2 .3v2.2M140.4 140.7l.2 .3h2.3l.2-.3M140.4 156.1h.1M140.4 155.7h.1M140.4 158.7h.1M140.4 159.1h.1M140.4 158.3h.1"/>
<path d="M140.4 157.9h.1M140.4 157.6h.1M140.4 157.2h.1M140.4 156.8h.1M140.4 156.5h.1M140.6 152.3h2.5M140.7 144.1l.5-.3 .5-.1v2.8a1.43 1.43 0 0 1-1.3-.8 1.43 1.43 0 0 1 .3-1.6zM141 152h2.5M141.2 155.7h1M141.3 159.1h1M141.4 151.6h2.5M141.6 156.1h.4"/>
<path d="M141.6 158.7h.4M141.7 156.5h.1M141.7 158.3h.1M141.7 157.9h.1M141.7 157.6h.1M141.7 157.2h.1M141.7 156.8h.1M141.7 143.7h.1M141.7 146h.1M141.7 145.6h.1M141.7 146.3h.1M141.7 145.2h.1"/>
<path d="M141.7 144.8h.1M141.7 144.5h.1M141.7 144.1h.1M141.8 143.7a1.42 1.42 0 0 1 1.4 1.4 1.42 1.42 0 0 1-1.4 1.4zM142.2 143.7h6.6M142.4 146.3h3.9M142.8 144.1h5.6M142.9 146h3.7M143 144.5h5.1M143.1 145.6h3.9M143.1 151.2l-.2 .2h-1.4l-1.5 1.6-.3 .1h-2.7l-1.2 1.2-.2 .1h-6.2l-2.4 2.4M143.1 151.2h1.2"/>
<path d="M143.1 150.8h1.5M143.1 150.5h1.9M143.1 150.1h2.3M143.1 149.7h2.4M143.1 149.4h2.4M143.1 149h2.4M143.1 140.7h8.1M143.1 140.4h8.2M143.2 145.2h4.2M143.2 144.8h4.5M143.8 159.1h1M143.8 155.7h1"/>
<path d="M143.8 155.3h10.1M143.8 155h10.1M143.8 154.6h10.1M143.8 154.2h10.1M143.9 153.8h10M144 156.1h.5M144.1 158.7h.4M144.2 158.3h.2M144.2 157.9h.2M144.2 157.6h.2M144.2 157.2h.2M144.2 156.8h.2"/>
<path d="M144.2 156.5h.2M144.3 153.5h9.6M144.6 156a1.19 1.19 0 0 1 1.2-.5 1.19 1.19 0 0 1 .9 .9v2a1.2 1.2 0 0 1-1.1 1 1.2 1.2 0 0 1-1.2-1v-2zM144.7 153.1h9.2M145.1 152.7h8.8M145.4 152.3h8.5M145.8 152h8.1M146.2 151.6h7.7M146.3 155.7h7.6M146.3 159.1h7.6M146.5 151.2h7.4M146.6 156.1h7.3"/>
<path d="M146.6 158.7h7.3M146.7 158.3h7.2M146.7 157.9h7.2M146.7 157.6h7.2M146.7 157.2h7.2M146.7 156.8h7.2M146.7 156.5h7.2M146.9 150.8h7M147.2 148.2h6.7M147.2 150.5h6.7M147.2 150.1h6.7M147.2 149.7h6.7"/>
<path d="M147.2 149.4h6.7M147.2 149h6.7M147.2 148.6h6.7M147.2 147.8h6.7M147.4 147.5h6.5M147.8 147.1h3.9M148.2 146.7h3.1M148.4 146.5h.1M148.6 146.3h2.6M148.6 146.3l-.2 .2M148.6 146.3h.1M148.9 146h3.6v1.4l-.7-.2-.5-.5"/>
<path d="M149.2 145.6h2M149.6 145.2h1.8M150 144.8h1.7M150.3 144.5h1.4M150.7 144.1h.6M151 143.7h.2M151.2 143.7v-.2l-2.6 2.8M151.2 143.7l.2 .5 .6 .5M152 144.7h.1M152 144.7a1.39 1.39 0 0 0-.9 1.2M152.5 147.1h.1M152.5 146.7h.1"/>
<path d="M152.5 146.3h.1M153.1 144.7h.1M153.1 144.7l.6 .5 .2 .7M153.1 142.2h.8M153.4 144.8h.5M153.4 147.1h.5M153.4 144.5h.5M153.5 141.9h.4M153.6 142.6h.3M153.7 145.2h.2M153.7 144.1h.2M153.7 146.7h.2"/>
<path d="M153.8 141.5h.1M153.8 140.4h.1M153.8 143h.1M153.9 143.7h.1M153.9 145.6h.1M153.9 143.7l-.2 .5-.6 .5M153.9 146.3h.1M153.9 143.4h.1M153.9 141.1h.1M153.9 140.7h.1M153.9 146h-2.8l.2 .7M153.9 145.9h-1.3v1.5l.7-.2 .4-.5"/>
<path d="M153.9 146.1l-.2 .6M55.9 170.3h.1M55.9 168.4h30.5M55.9 163.9h5.3M55.9 168.8h30.1M55.9 162.1h3.4M55.9 165.8h6.1M55.9 169.9h.5M55.9 169.6h1.1M55.9 169.2h30M55.9 168.1h30.8M55.9 167.7h30.3"/>
<path d="M55.9 167.3h30.1M55.9 166.9h7.1M55.9 166.6h6.5M55.9 166.2h6.2M55.9 165.4h6M55.9 165.1h6M55.9 164.7h6M55.9 164.3h5.7M55.9 163.6h4.9M55.9 163.2h4.5M55.9 162.8h4.1M55.9 162.5h3.8"/>
<path d="M55.9 161.7h3.2M55.9 161.3h3.2M55.9 161h3.2M55.9 160.6h3.2M55.9 160.2h3.2M56.7 169.7l1-.4h1.1l1 .4M56.7 169.7h.1M56.7 169.7l-.8 .6M59.6 169.6h26.3M59.8 169.7h.1M59.8 169.7l.8 .6M60.2 169.9h25.8"/>
<path d="M60.5 174.4h88.9M60.6 170.3h25.6M60.6 174.3l-.4 .4h89.4l-.4-.4M60.6 170.3h.1M60.6 174.3h.1M60.6 170.3l.6 1M60.7 161h15.5M60.7 160.6h15.1M60.7 160.2h14.8M60.8 174.1h88.3M60.8 170.7h26M60.9 161.3h15.7"/>
<path d="M61 173.7h87.8M61.1 171h27.3M61.2 173.4l-.6 .9M61.2 171.3h.1M61.2 173.4h.1M61.2 171.3l.2 1-.2 1.1M61.2 173.3h87.5M61.2 171.4h27.3M61.2 161.7h15.8M61.3 172.9h87.3M61.3 171.8h27.6M61.3 172.6h87.2"/>
<path d="M61.3 172.2h87.2M61.6 162.1h15.7M62 162.5h15.7M62.4 162.8h15.7M62.7 163.2h15.8M64.2 163.6h14.6M64.3 166.9h21.6M64.9 163.9h14.3M64.9 166.6h21.1M65.2 164.3h14.4M65.2 166.2h20.9M65.4 164.7h14.6"/>
<path d="M65.5 165.4h15.2M65.5 165.1h14.8M85.9 169.6a1.28 1.28 0 0 0 1.3 1.2 1.28 1.28 0 0 0 1.2-1.2M85.9 169.5h2.5M85.9 169.4h2.5M87.1 170.3h.1M87.1 168.2v2.6M87.1 168.4h.1M87.1 168.8h.1M87.1 170.7h.1M87.1 169.9h.1M87.1 169.6h.1"/>
<path d="M87.1 169.2h.1M87.2 168.2v2.6M87.5 170.7h.8M87.6 168.1h6.7M87.9 168.4h6.6M88.1 170.3h.3M88.1 167.7h6.1M88.2 166.2h6.8M88.2 168.8l.2 .8M88.2 168.8a1.28 1.28 0 0 0-1.5-.6 1.28 1.28 0 0 0-.8 1.4M88.3 168.8h12.2M88.3 167.3h5.9"/>
<path d="M88.3 166.6h6.3M88.3 169.9h.3M88.4 166.9h5.9M88.4 169.2h6.2M88.4 169.6h.6M90.4 169.6h1.5M90.5 171.8h1.2M90.8 169.9h.6M90.9 171.4h.5M91 170.3h.3M91 171h.2M91 170.7h.2"/>
<path d="M93.2 169.6h1.1M93.4 171.8h55.2M93.6 163.9h1.2M93.6 169.9h.6M93.7 171.4h55M93.7 162.5h.5M93.8 163.6h1M93.8 170.3h.4M93.9 171h.7M93.9 162.8h.3M93.9 170.7h.4M93.9 163.2h.5"/>
<path d="M94.2 167.3a1.22 1.22 0 0 0 1 1.5M94.2 167.3a1.26 1.26 0 0 1 1.2-1 1.26 1.26 0 0 1 1.2 1M95.8 166.2h2M95.8 161.3h1M96 163.6h.8M96.1 163.9h.7M96.2 166.6h2M96.2 161h.6M96.2 171h5.6M96.2 169.2h4.6M96.3 168.4h3.8M96.4 165.8h1.1"/>
<path d="M96.4 161.7h.4M96.5 164.3a1.25 1.25 0 0 1-.3 1.7 1.25 1.25 0 0 1-1.7-.2h-6.8a1.24 1.24 0 0 1 .4 1.9 1.24 1.24 0 0 1-1.9 0 1.24 1.24 0 0 1 .4-1.9h-21.2M96.5 163.2a1.25 1.25 0 0 1-1.5 .5 1.25 1.25 0 0 1-.8-1.3l-.4-.3h-.4a1.32 1.32 0 0 1 0 2.1h1.1a1.24 1.24 0 0 1 2 .1M96.5 164.3h.3M96.5 163.2h.3M96.5 170.7h5.3M96.5 166.9h2.1M96.5 160.6h.3M96.5 169.6h4.7M96.5 168.1h3.2M96.6 162.1h.2M96.6 165.4h.5"/>
<path d="M96.6 164.7h.2M96.6 162.8h.2M96.6 170.3h5.2M96.6 167.3a1.25 1.25 0 0 1-.9 1.5M96.6 169.9h5M96.6 167.7h2.7M96.6 167.3h2.4M96.6 165.1h.2M96.6 162.5h.2M96.6 160.2h.2M101.6 162.1h.3M101.6 162.5h.2"/>
<path d="M101.6 161.7h.4M101.6 161.3h1M101.6 161h.7M101.6 160.6h.3M101.6 160.2h.2M102.7 168.8h.1M102.7 168.8h9.5M103.5 166.2h8.5M103.5 161.3h50.4M103.7 163.6h50.2M103.7 163.9h9.1M103.8 166.6h8.7"/>
<path d="M103.8 161h50.1M103.9 168.4h50M104 165.8h7.8M104 161.7h49.9M104.1 164.3a1.25 1.25 0 0 1 0 1.4 1.25 1.25 0 0 1-1.2 .6 1.49 1.49 0 0 1 1.4 1M104.1 163.2l-.4 .3-.8 .2a1.63 1.63 0 0 1 1.2 .6M104.1 164.3h8M104.1 163.2h49.8M104.1 160.6h49.8M104.1 166.9h49.8M104.2 168.1h49.7M104.2 162.1h49.7"/>
<path d="M104.2 165.4h7.5M104.2 164.7h7.6M104.2 162.8h49.7M104.3 170.3h7.5M104.3 167.3a1.25 1.25 0 0 1-1 1.5M104.3 171h8.3M104.3 170.7h7.8M104.3 169.9h7.5M104.3 169.6h7.5M104.3 169.2h7.6M104.3 167.7h49.6M104.3 167.3h49.6"/>
<path d="M104.3 165.1h7.4M104.3 162.5h49.6M104.3 160.2h49.6M111.7 165.4h2.8M111.7 165.4l.1 .4M111.8 169.5a1.37 1.37 0 0 0 1.3 1.7 1.37 1.37 0 0 0 1.3-1.7M112.8 163.9a1.44 1.44 0 0 0-1.1 1.3h2.8a1.37 1.37 0 0 0-1.1-1.3M112.8 163.9h.6M112.8 168.5l-.5 .2-.3 .4-.2 .4M113.1 163.9v2.8a1.38 1.38 0 0 1-1.3-.9M113.1 165.8h.1M113.1 166.6h.1"/>
<path d="M113.1 166.2h.1M113.1 165.4h.1M113.1 165.1h.1M113.1 164.7h.1M113.1 164.3h.1M113.2 163.9v2.8a1.38 1.38 0 0 0 1.2-.9M113.4 168.5l.5 .2 .3 .4 .2 .4M113.4 163.9h12.1M113.6 171h5.5M113.7 166.6h5.4M114 168.8h4.7M114.1 164.3h4.6"/>
<path d="M114.2 170.7h4.4M114.2 166.2h4.4M114.3 169.2h4.1M114.4 170.3h3.9M114.4 164.7h4M114.4 165.8h4M114.4 169.9h3.9M114.4 169.6h3.9M114.5 165.1h3.8M114.5 165.4l-.1 .4M114.5 165.4h3.8M118.3 169.5a1.37 1.37 0 0 0 1.3 1.7 1.37 1.37 0 0 0 1.3-1.7"/>
<path d="M119.3 168.5l-.5 .2-.3 .4-.2 .4M119.9 168.5l.5 .2 .3 .4 .2 .4M120.1 166.6h5.1M120.1 171h5.2M120.5 168.8h4.4M120.5 164.3h4.3M120.6 166.2h4.1M120.6 170.7h4.2M120.8 169.2h3.8M120.8 164.7h3.7M120.8 165.8h3.7M120.9 170.3h3.6"/>
<path d="M120.9 169.9h3.6M120.9 169.6h3.6M120.9 165.4h3.5M120.9 165.1h3.5M124.4 165.4h2.8M124.4 165.4l.1 .4M124.5 169.5a1.37 1.37 0 0 0 1.3 1.7 1.37 1.37 0 0 0 1.3-1.7M124.9 164.2a1.4 1.4 0 0 1 1.5-.2 1.4 1.4 0 0 1 .8 1.2h-2.8l.1-.4zM125.5 168.5l-.5 .2-.3 .4-.2 .4M125.8 163.9v2.8a1.38 1.38 0 0 1-1.3-.9M125.8 165.8h.1M125.8 166.6h.1"/>
<path d="M125.8 166.2h.1M125.8 165.4h.1M125.8 165.1h.1M125.8 164.7h.1M125.8 164.3h.1M125.9 163.9v2.8a1.37 1.37 0 0 0 1.3-1.3M126.1 168.5l.5 .2 .3 .4 .2 .4M126.1 163.9h12.1M126.3 171h5.5M126.4 166.6h5.4M126.7 168.8h4.7M126.8 164.3h4.6"/>
<path d="M126.8 170.7h4.5M126.9 166.2h4.4M127 169.2h4.1M127 170.3h4M127.1 164.7h4M127.1 165.8h4M127.1 169.9h3.9M127.1 169.6h3.9M127.2 165.1h3.8M127.2 165.4h3.8M131 169.5a1.37 1.37 0 0 0 1.3 1.7 1.37 1.37 0 0 0 1.3-1.7M132 168.5l-.5 .2-.4 .4-.1 .4"/>
<path d="M132.6 168.5l.5 .2 .3 .4 .2 .4M132.8 166.6h5.1M132.8 171h5.2M133.2 168.8h4.4M133.2 164.3h4.3M133.3 166.2h4.1M133.3 170.7h4.2M133.5 169.2h3.8M133.5 164.7h3.7M133.5 170.3h3.7M133.5 165.8h3.7M133.6 169.9h3.5"/>
<path d="M133.6 169.6h3.5M133.6 165.4h3.5M133.6 165.1h3.5M137.1 165.4h2.8M137.1 169.5a1.38 1.38 0 0 0 1.4 1.7 1.38 1.38 0 0 0 1.3-1.7M137.6 164.2a1.4 1.4 0 0 1 1.5-.2 1.4 1.4 0 0 1 .8 1.2h-2.8l.1-.4zM138.2 168.5l-.5 .2-.3 .4-.3 .4M138.5 163.9v2.8a1.37 1.37 0 0 1-1.4-1.3M138.5 165.8h.1M138.5 166.6h.1M138.5 166.2h.1M138.5 165.4h.1"/>
<path d="M138.5 165.1h.1M138.5 164.7h.1M138.5 164.3h.1M138.5 163.9v2.8a1.32 1.32 0 0 0 1.3-.9M138.8 168.5l.5 .2 .3 .4 .2 .4M138.8 163.9h15.1M139 171h5.5M139.1 166.6h5.4M139.4 168.8h4.7M139.5 164.3h4.6M139.5 170.7h4.5M139.6 166.2h4.4"/>
<path d="M139.7 169.2h4.1M139.7 170.3h4M139.7 164.7h4.1M139.8 165.8h3.9M139.8 169.9h3.8M139.8 169.6h3.8M139.9 165.1h3.7M139.9 165.4l-.1 .4M139.9 165.4h3.7M143.6 169.5a1.38 1.38 0 0 0 1.4 1.7 1.38 1.38 0 0 0 1.3-1.7M144.7 168.5l-.5 .2-.4 .4-.2 .4M145.3 168.5l.5 .2 .3 .4 .2 .4"/>
<path d="M145.5 166.6h8.4M145.5 171h3.3M145.9 168.8h8M145.9 164.3h8M146 166.2h7.9M146 170.7h3M146.2 169.2h7.7M146.2 164.7h7.7M146.2 170.3h3M146.2 165.8h7.7M146.3 169.9h3.4M146.3 169.6h4"/>
<path d="M146.3 165.4h7.6M146.3 165.1h7.6M148.5 172.3h.1M148.5 172.3l.2 1.1M148.7 171.3h.1M148.7 173.4h.1M148.7 171.3l-.2 1M148.7 173.4l.5 .9M149.2 170.3h.1M149.2 174.3h.1M149.2 170.3l-.5 1M150 169.7l1-.4h1.1l1 .4"/>
<path d="M150 169.7h.1M150 169.7l-.8 .6M152.9 169.6h1M153.1 169.7l.8 .6M153.1 169.7h.1M153.5 169.9h.4M153.9 170.3h.1"/>
<circle cx="95.4" cy="139.6" r="1.27"/>
<circle cx="95.4" cy="147.3" r="1.27"/>
<circle cx="95.4" cy="152.3" r="1.27"/>
<circle cx="103" cy="147.3" r="1.27"/>
<circle cx="103" cy="157.4" r="1.26"/>
<circle cx="106.2" cy="152.3" r="1.28"/>
<circle cx="89.7" cy="170.7" r="1.37"/>
<circle cx="92.5" cy="170.7" r="1.38"/>
<circle cx="95.4" cy="170.1" r="1.27"/>
<circle cx="119.6" cy="165.3" r="1.37"/>
<circle cx="132.3" cy="165.3" r="1.37"/>
<circle cx="145" cy="165.3" r="1.37"/>
</g>
<circle cx="121.8" cy="148.3" r=".7" fill="#008000" stroke="#008000" stroke-width=".18"/>
<circle cx="121.8" cy="148.3" r=".44" fill="#fff" stroke="#000" stroke-width=".18"/>
<path d="M121.1 145.5h1.3v1.4h-1.3z" fill="#008000" stroke="#008000" stroke-width=".18"/>
<circle cx="121.8" cy="146.2" r=".44" fill="#fff" stroke="#000" stroke-width=".18"/>
<path d="M112.7 149.5h1.7v1.8h-1.7z" fill="#008000" stroke="#008000" stroke-width=".18"/>
<circle cx="113.6" cy="150.4" r=".44" fill="#fff" stroke="#000" stroke-width=".18"/>
<circle cx="116.6" cy="150.4" r=".89" fill="#008000" stroke="#008000" stroke-width=".18"/>
<circle cx="116.6" cy="150.4" r=".44" fill="#fff" stroke="#000" stroke-width=".18"/>
<circle cx="141.7" cy="145.1" r=".97" fill="#008000" stroke="#008000" stroke-width=".18"/>
<circle cx="141.7" cy="145.1" r=".44" fill="#fff" stroke="#000" stroke-width=".18"/>
<path d="M140.8 149.1h1.9v1.9h-1.9z" fill="#008000" stroke="#008000" stroke-width=".18"/>
<circle cx="141.7" cy="150.1" r=".44" fill="#fff" stroke="#000" stroke-width=".18"/>
<circle cx="141.7" cy="134.6" r=".97" fill="#008000" stroke="#008000" stroke-width=".18"/>
<circle cx="141.7" cy="134.6" r=".44" fill="#fff" stroke="#000" stroke-width=".18"/>
<path d="M140.8 138.6h1.9v2h-1.9z" fill="#008000" stroke="#008000" stroke-width=".18"/>
<circle cx="141.7" cy="139.6" r=".44" fill="#fff" stroke="#000" stroke-width=".18"/>
<circle cx="124" cy="156.1" r=".85" fill="#008000" stroke="#008000" stroke-width=".18"/>
<circle cx="124" cy="156.1" r=".55" fill="#fff" stroke="#000" stroke-width=".18"/>
<circle cx="131.6" cy="156.1" r=".85" fill="#008000" stroke="#008000" stroke-width=".18"/>
<circle cx="131.6" cy="156.1" r=".55" fill="#fff" stroke="#000" stroke-width=".18"/>
<path d="M134.7 151.1h1.4" fill="none" stroke="#008000" stroke-width="1.3"/>
<circle cx="135.4" cy="151.1" r=".4" fill="#fff" stroke="#000" stroke-width=".18"/>
<path d="M122 151.1h1.4" fill="none" stroke="#008000" stroke-width="1.3"/>
<circle cx="122.7" cy="151.1" r=".4" fill="#fff" stroke="#000" stroke-width=".18"/>
<circle cx="123" cy="135.8" r=".93" fill="#008000" stroke="#008000" stroke-width=".18"/>
<circle cx="123" cy="135.8" r=".44" fill="#fff" stroke="#000" stroke-width=".18"/>
<circle cx="123" cy="143.4" r=".93" fill="#008000" stroke="#008000" stroke-width=".18"/>
<circle cx="123" cy="143.4" r=".44" fill="#fff" stroke="#000" stroke-width=".18"/>
<circle cx="116.4" cy="144.4" r="2.16" fill="#008000" stroke="#008000" stroke-width=".18"/>
<circle cx="116.4" cy="144.4" r="1.5" fill="#fff" stroke="#000" stroke-width=".18"/>
<circle cx="116.4" cy="138.5" r="2.16" fill="#008000" stroke="#008000" stroke-width=".18"/>
<circle cx="116.4" cy="138.5" r="1.5" fill="#fff" stroke="#000" stroke-width=".18"/>
<circle cx="111.7" cy="141.5" r="2.16" fill="#008000" stroke="#008000" stroke-width=".18"/>
<circle cx="111.7" cy="141.5" r="1.5" fill="#fff" stroke="#000" stroke-width=".18"/>
<circle cx="152.5" cy="146" r=".93" fill="#008000" stroke="#008000" stroke-width=".18"/>
<circle cx="152.5" cy="146" r=".51" fill="#fff" stroke="#000" stroke-width=".18"/>
<circle cx="152.5" cy="143.4" r=".93" fill="#008000" stroke="#008000" stroke-width=".18"/>
<circle cx="152.5" cy="143.4" r=".51" fill="#fff" stroke="#000" stroke-width=".18"/>
<circle cx="152.5" cy="140.9" r=".93" fill="#008000" stroke="#008000" stroke-width=".18"/>
<circle cx="152.5" cy="140.9" r=".51" fill="#fff" stroke="#000" stroke-width=".18"/>
<circle cx="152.5" cy="138.4" r=".93" fill="#008000" stroke="#008000" stroke-width=".18"/>
<circle cx="152.5" cy="138.4" r=".51" fill="#fff" stroke="#000" stroke-width=".18"/>
<circle cx="57.3" cy="146" r=".93" fill="#008000" stroke="#008000" stroke-width=".18"/>
<circle cx="57.3" cy="146" r=".51" fill="#fff" stroke="#000" stroke-width=".18"/>
<circle cx="57.3" cy="143.4" r=".93" fill="#008000" stroke="#008000" stroke-width=".18"/>
<circle cx="57.3" cy="143.4" r=".51" fill="#fff" stroke="#000" stroke-width=".18"/>
<circle cx="57.3" cy="140.9" r=".93" fill="#008000" stroke="#008000" stroke-width=".18"/>
<circle cx="57.3" cy="140.9" r=".51" fill="#fff" stroke="#000" stroke-width=".18"/>
<circle cx="57.3" cy="138.4" r=".93" fill="#008000" stroke="#008000" stroke-width=".18"/>
<circle cx="57.3" cy="138.4" r=".51" fill="#fff" stroke="#000" stroke-width=".18"/>
<circle cx="86.1" cy="134.6" r=".7" fill="#008000" stroke="#008000" stroke-width=".18"/>
<circle cx="86.1" cy="134.6" r=".4" fill="#fff" stroke="#000" stroke-width=".18"/>
<circle cx="82.5" cy="134.6" r=".7" fill="#008000" stroke="#008000" stroke-width=".18"/>
<circle cx="82.5" cy="134.6" r=".4" fill="#fff" stroke="#000" stroke-width=".18"/>
<circle cx="71.3" cy="134.6" r=".93" fill="#008000" stroke="#008000" stroke-width=".18"/>
<circle cx="71.3" cy="134.6" r=".44" fill="#fff" stroke="#000" stroke-width=".18"/>
<circle cx="78.9" cy="134.6" r=".93" fill="#008000" stroke="#008000" stroke-width=".18"/>
<circle cx="78.9" cy="134.6" r=".44" fill="#fff" stroke="#000" stroke-width=".18"/>
<circle cx="125.8" cy="165.3" r=".93" fill="#008000" stroke="#008000" stroke-width=".18"/>
<circle cx="125.8" cy="165.3" r=".51" fill="#fff" stroke="#000" stroke-width=".18"/>
<circle cx="132.3" cy="165.3" r=".93" fill="#008000" stroke="#008000" stroke-width=".18"/>
<circle cx="132.3" cy="165.3" r=".51" fill="#fff" stroke="#000" stroke-width=".18"/>
<circle cx="125.8" cy="169.8" r=".93" fill="#008000" stroke="#008000" stroke-width=".18"/>
<circle cx="125.8" cy="169.8" r=".51" fill="#fff" stroke="#000" stroke-width=".18"/>
<circle cx="132.3" cy="169.8" r=".93" fill="#008000" stroke="#008000" stroke-width=".18"/>
<circle cx="132.3" cy="169.8" r=".51" fill="#fff" stroke="#000" stroke-width=".18"/>
<path d="M140.5 156.7v1.5" fill="none" stroke="#008000" stroke-width="1.5"/>
<circle cx="140.5" cy="157.4" r=".51" fill="#fff" stroke="#000" stroke-width=".18"/>
<path d="M143 156.7v1.5" fill="none" stroke="#008000" stroke-width="1.5"/>
<circle cx="143" cy="157.4" r=".51" fill="#fff" stroke="#000" stroke-width=".18"/>
<path d="M145.5 156.7v1.5" fill="none" stroke="#008000" stroke-width="1.5"/>
<circle cx="145.5" cy="157.4" r=".51" fill="#fff" stroke="#000" stroke-width=".18"/>
<circle cx="138.5" cy="165.3" r=".93" fill="#008000" stroke="#008000" stroke-width=".18"/>
<circle cx="138.5" cy="165.3" r=".51" fill="#fff" stroke="#000" stroke-width=".18"/>
<circle cx="145" cy="165.3" r=".93" fill="#008000" stroke="#008000" stroke-width=".18"/>
<circle cx="145" cy="165.3" r=".51" fill="#fff" stroke="#000" stroke-width=".18"/>
<circle cx="138.5" cy="169.8" r=".93" fill="#008000" stroke="#008000" stroke-width=".18"/>
<circle cx="138.5" cy="169.8" r=".51" fill="#fff" stroke="#000" stroke-width=".18"/>
<circle cx="145" cy="169.8" r=".93" fill="#008000" stroke="#008000" stroke-width=".18"/>
<circle cx="145" cy="169.8" r=".51" fill="#fff" stroke="#000" stroke-width=".18"/>
<circle cx="113.1" cy="165.3" r=".93" fill="#008000" stroke="#008000" stroke-width=".18"/>
<circle cx="113.1" cy="165.3" r=".51" fill="#fff" stroke="#000" stroke-width=".18"/>
<circle cx="119.6" cy="165.3" r=".93" fill="#008000" stroke="#008000" stroke-width=".18"/>
<circle cx="119.6" cy="165.3" r=".51" fill="#fff" stroke="#000" stroke-width=".18"/>
<circle cx="113.1" cy="169.8" r=".93" fill="#008000" stroke="#008000" stroke-width=".18"/>
<circle cx="113.1" cy="169.8" r=".51" fill="#fff" stroke="#000" stroke-width=".18"/>
<circle cx="119.6" cy="169.8" r=".93" fill="#008000" stroke="#008000" stroke-width=".18"/>
<circle cx="119.6" cy="169.8" r=".51" fill="#fff" stroke="#000" stroke-width=".18"/>
<circle cx="68.7" cy="144.1" r="1.17" fill="#008000" stroke="#008000" stroke-width=".18"/>
<circle cx="68.7" cy="144.1" r=".51" fill="#fff" stroke="#000" stroke-width=".18"/>
<circle cx="76.4" cy="144.1" r="1.17" fill="#008000" stroke="#008000" stroke-width=".18"/>
<circle cx="76.4" cy="144.1" r=".51" fill="#fff" stroke="#000" stroke-width=".18"/>
<circle cx="81.8" cy="148.5" r=".93" fill="#008000" stroke="#008000" stroke-width=".18"/>
<circle cx="81.8" cy="148.5" r=".44" fill="#fff" stroke="#000" stroke-width=".18"/>
<circle cx="81.8" cy="156.1" r=".93" fill="#008000" stroke="#008000" stroke-width=".18"/>
<circle cx="81.8" cy="156.1" r=".44" fill="#fff" stroke="#000" stroke-width=".18"/>
<path d="M102.2 169.2h1.7v1.7h-1.7z" fill="#008000" stroke="#008000" stroke-width=".18"/>
<circle cx="103" cy="170.1" r=".55" fill="#fff" stroke="#000" stroke-width=".18"/>
<circle cx="103" cy="167.6" r=".85" fill="#008000" stroke="#008000" stroke-width=".18"/>
<circle cx="103" cy="167.6" r=".55" fill="#fff" stroke="#000" stroke-width=".18"/>
<circle cx="103" cy="165" r=".85" fill="#008000" stroke="#008000" stroke-width=".18"/>
<circle cx="103" cy="165" r=".55" fill="#fff" stroke="#000" stroke-width=".18"/>
<circle cx="103" cy="162.5" r=".85" fill="#008000" stroke="#008000" stroke-width=".18"/>
<circle cx="103" cy="162.5" r=".55" fill="#fff" stroke="#000" stroke-width=".18"/>
<circle cx="103" cy="160" r=".85" fill="#008000" stroke="#008000" stroke-width=".18"/>
<circle cx="103" cy="160" r=".55" fill="#fff" stroke="#000" stroke-width=".18"/>
<circle cx="103" cy="157.4" r=".85" fill="#008000" stroke="#008000" stroke-width=".18"/>
<circle cx="103" cy="157.4" r=".55" fill="#fff" stroke="#000" stroke-width=".18"/>
<circle cx="103" cy="154.9" r=".85" fill="#008000" stroke="#008000" stroke-width=".18"/>
<circle cx="103" cy="154.9" r=".55" fill="#fff" stroke="#000" stroke-width=".18"/>
<circle cx="103" cy="152.3" r=".85" fill="#008000" stroke="#008000" stroke-width=".18"/>
<circle cx="103" cy="152.3" r=".55" fill="#fff" stroke="#000" stroke-width=".18"/>
<circle cx="103" cy="149.8" r=".85" fill="#008000" stroke="#008000" stroke-width=".18"/>
<circle cx="103" cy="149.8" r=".55" fill="#fff" stroke="#000" stroke-width=".18"/>
<circle cx="103" cy="147.3" r=".85" fill="#008000" stroke="#008000" stroke-width=".18"/>
<circle cx="103" cy="147.3" r=".55" fill="#fff" stroke="#000" stroke-width=".18"/>
<circle cx="103" cy="144.7" r=".85" fill="#008000" stroke="#008000" stroke-width=".18"/>
<circle cx="103" cy="144.7" r=".55" fill="#fff" stroke="#000" stroke-width=".18"/>
<circle cx="103" cy="142.2" r=".85" fill="#008000" stroke="#008000" stroke-width=".18"/>
<circle cx="103" cy="142.2" r=".55" fill="#fff" stroke="#000" stroke-width=".18"/>
<circle cx="103" cy="139.6" r=".85" fill="#008000" stroke="#008000" stroke-width=".18"/>
<circle cx="103" cy="139.6" r=".55" fill="#fff" stroke="#000" stroke-width=".18"/>
<circle cx="103" cy="137.1" r=".85" fill="#008000" stroke="#008000" stroke-width=".18"/>
<circle cx="103" cy="137.1" r=".55" fill="#fff" stroke="#000" stroke-width=".18"/>
<circle cx="95.4" cy="137.1" r=".85" fill="#008000" stroke="#008000" stroke-width=".18"/>
<circle cx="95.4" cy="137.1" r=".55" fill="#fff" stroke="#000" stroke-width=".18"/>
<circle cx="95.4" cy="139.6" r=".85" fill="#008000" stroke="#008000" stroke-width=".18"/>
<circle cx="95.4" cy="139.6" r=".55" fill="#fff" stroke="#000" stroke-width=".18"/>
<circle cx="95.4" cy="142.2" r=".85" fill="#008000" stroke="#008000" stroke-width=".18"/>
<circle cx="95.4" cy="142.2" r=".55" fill="#fff" stroke="#000" stroke-width=".18"/>
<circle cx="95.4" cy="144.7" r=".85" fill="#008000" stroke="#008000" stroke-width=".18"/>
<circle cx="95.4" cy="144.7" r=".55" fill="#fff" stroke="#000" stroke-width=".18"/>
<circle cx="95.4" cy="147.3" r=".85" fill="#008000" stroke="#008000" stroke-width=".18"/>
<circle cx="95.4" cy="147.3" r=".55" fill="#fff" stroke="#000" stroke-width=".18"/>
<circle cx="95.4" cy="149.8" r=".85" fill="#008000" stroke="#008000" stroke-width=".18"/>
<circle cx="95.4" cy="149.8" r=".55" fill="#fff" stroke="#000" stroke-width=".18"/>
<circle cx="95.4" cy="152.3" r=".85" fill="#008000" stroke="#008000" stroke-width=".18"/>
<circle cx="95.4" cy="152.3" r=".55" fill="#fff" stroke="#000" stroke-width=".18"/>
<circle cx="95.4" cy="154.9" r=".85" fill="#008000" stroke="#008000" stroke-width=".18"/>
<circle cx="95.4" cy="154.9" r=".55" fill="#fff" stroke="#000" stroke-width=".18"/>
<circle cx="95.4" cy="157.4" r=".85" fill="#008000" stroke="#008000" stroke-width=".18"/>
<circle cx="95.4" cy="157.4" r=".55" fill="#fff" stroke="#000" stroke-width=".18"/>
<circle cx="95.4" cy="160" r=".85" fill="#008000" stroke="#008000" stroke-width=".18"/>
<circle cx="95.4" cy="160" r=".55" fill="#fff" stroke="#000" stroke-width=".18"/>
<circle cx="95.4" cy="162.5" r=".85" fill="#008000" stroke="#008000" stroke-width=".18"/>
<circle cx="95.4" cy="162.5" r=".55" fill="#fff" stroke="#000" stroke-width=".18"/>
<circle cx="95.4" cy="165" r=".85" fill="#008000" stroke="#008000" stroke-width=".18"/>
<circle cx="95.4" cy="165" r=".55" fill="#fff" stroke="#000" stroke-width=".18"/>
<circle cx="95.4" cy="167.6" r=".85" fill="#008000" stroke="#008000" stroke-width=".18"/>
<circle cx="95.4" cy="167.6" r=".55" fill="#fff" stroke="#000" stroke-width=".18"/>
<circle cx="95.4" cy="170.1" r=".85" fill="#008000" stroke="#008000" stroke-width=".18"/>
<circle cx="95.4" cy="170.1" r=".55" fill="#fff" stroke="#000" stroke-width=".18"/>
<circle cx="63.7" cy="165.3" r="1.4" fill="#008000" stroke="#008000" stroke-width=".18"/>
<circle cx="63.7" cy="165.3" r=".93" fill="#fff" stroke="#000" stroke-width=".18"/>
<circle cx="63.7" cy="152.1" r="1.4" fill="#008000" stroke="#008000" stroke-width=".18"/>
<circle cx="63.7" cy="152.1" r=".93" fill="#fff" stroke="#000" stroke-width=".18"/>
<circle cx="106.8" cy="133.3" r=".93" fill="#008000" stroke="#008000" stroke-width=".18"/>
<circle cx="106.8" cy="133.3" r=".51" fill="#fff" stroke="#000" stroke-width=".18"/>
<circle cx="104.3" cy="133.3" r=".93" fill="#008000" stroke="#008000" stroke-width=".18"/>
<circle cx="104.3" cy="133.3" r=".51" fill="#fff" stroke="#000" stroke-width=".18"/>
<circle cx="101.7" cy="133.3" r=".93" fill="#008000" stroke="#008000" stroke-width=".18"/>
<circle cx="101.7" cy="133.3" r=".51" fill="#fff" stroke="#000" stroke-width=".18"/>
<circle cx="99.2" cy="133.3" r=".93" fill="#008000" stroke="#008000" stroke-width=".18"/>
<circle cx="99.2" cy="133.3" r=".51" fill="#fff" stroke="#000" stroke-width=".18"/>
<circle cx="96.7" cy="133.3" r=".93" fill="#008000" stroke="#008000" stroke-width=".18"/>
<circle cx="96.7" cy="133.3" r=".51" fill="#fff" stroke="#000" stroke-width=".18"/>
<circle cx="89.7" cy="157.7" r=".93" fill="#008000" stroke="#008000" stroke-width=".18"/>
<circle cx="89.7" cy="157.7" r=".44" fill="#fff" stroke="#000" stroke-width=".18"/>
<circle cx="89.7" cy="150.1" r=".93" fill="#008000" stroke="#008000" stroke-width=".18"/>
<circle cx="89.7" cy="150.1" r=".44" fill="#fff" stroke="#000" stroke-width=".18"/>
<circle cx="89.7" cy="170.7" r=".93" fill="#008000" stroke="#008000" stroke-width=".18"/>
<circle cx="89.7" cy="170.7" r=".44" fill="#fff" stroke="#000" stroke-width=".18"/>
<circle cx="89.7" cy="163.1" r=".93" fill="#008000" stroke="#008000" stroke-width=".18"/>
<circle cx="89.7" cy="163.1" r=".44" fill="#fff" stroke="#000" stroke-width=".18"/>
<circle cx="92.5" cy="163.1" r=".93" fill="#008000" stroke="#008000" stroke-width=".18"/>
<circle cx="92.5" cy="163.1" r=".44" fill="#fff" stroke="#000" stroke-width=".18"/>
<circle cx="92.5" cy="170.7" r=".93" fill="#008000" stroke="#008000" stroke-width=".18"/>
<circle cx="92.5" cy="170.7" r=".44" fill="#fff" stroke="#000" stroke-width=".18"/>
<circle cx="87.1" cy="166.9" r=".83" fill="#008000" stroke="#008000" stroke-width=".18"/>
<circle cx="87.1" cy="166.9" r=".44" fill="#fff" stroke="#000" stroke-width=".18"/>
<circle cx="87.1" cy="169.5" r=".83" fill="#008000" stroke="#008000" stroke-width=".18"/>
<circle cx="87.1" cy="169.5" r=".44" fill="#fff" stroke="#000" stroke-width=".18"/>
<circle cx="84.3" cy="145.4" r=".83" fill="#008000" stroke="#008000" stroke-width=".18"/>
<circle cx="84.3" cy="145.4" r=".44" fill="#fff" stroke="#000" stroke-width=".18"/>
<circle cx="81.8" cy="145.4" r=".83" fill="#008000" stroke="#008000" stroke-width=".18"/>
<circle cx="81.8" cy="145.4" r=".44" fill="#fff" stroke="#000" stroke-width=".18"/>
<circle cx="84.3" cy="142.5" r=".83" fill="#008000" stroke="#008000" stroke-width=".18"/>
<circle cx="84.3" cy="142.5" r=".44" fill="#fff" stroke="#000" stroke-width=".18"/>
<circle cx="81.8" cy="142.5" r=".83" fill="#008000" stroke="#008000" stroke-width=".18"/>
<circle cx="81.8" cy="142.5" r=".44" fill="#fff" stroke="#000" stroke-width=".18"/>
<circle cx="106.2" cy="152.3" r=".83" fill="#008000" stroke="#008000" stroke-width=".18"/>
<circle cx="106.2" cy="152.3" r=".44" fill="#fff" stroke="#000" stroke-width=".18"/>
<circle cx="106.2" cy="154.9" r=".83" fill="#008000" stroke="#008000" stroke-width=".18"/>
<circle cx="106.2" cy="154.9" r=".44" fill="#fff" stroke="#000" stroke-width=".18"/>
<g fill="#800000" stroke="#800000" stroke-width=".18">
<path d="M124.9 131.9h10.8v10.4h-10.8z"/>
<path d="M126.4 144.4h1v2.1h-1z"/>
<path d="M128.1 144.4h1v2.1h-1z"/>
<path d="M129.8 144.4h1.1v2.1h-1.1z"/>
<path d="M131.5 144.4h1v2.1h-1z"/>
<path d="M133.2 144.4h1v2.1h-1z"/>
<path d="M82.9 169.7h1.5v.8h-1.5z"/>
<path d="M82.9 168.4h1.5v.8h-1.5z"/>
<path d="M82.9 167.2h1.5v.7h-1.5z"/>
<path d="M82.9 165.9h1.5v.8h-1.5z"/>
<path d="M82.9 164.6h1.5v.8h-1.5z"/>
<path d="M82.9 163.4h1.5v.7h-1.5z"/>
<path d="M82.9 162.1h1.5v.8h-1.5z"/>
<path d="M82.9 160.8h1.5v.8h-1.5z"/>
<path d="M82.9 159.6h1.5v.7h-1.5z"/>
<path d="M82.9 158.3h1.5v.8h-1.5z"/>
<path d="M73.4 159.6h1.5v.7h-1.5z"/>
<path d="M73.4 158.3h1.5v.8h-1.5z"/>
<path d="M73.4 160.8h1.5v.8h-1.5z"/>
<path d="M73.4 162.1h1.5v.8h-1.5z"/>
<path d="M73.4 163.4h1.5v.7h-1.5z"/>
<path d="M73.4 164.6h1.5v.8h-1.5z"/>
<path d="M73.4 165.9h1.5v.8h-1.5z"/>
<path d="M73.4 167.2h1.5v.7h-1.5z"/>
<path d="M73.4 168.4h1.5v.8h-1.5z"/>
<path d="M73.4 169.7h1.5v.8h-1.5z"/>
<path d="M61.7 156.7h4v4h-4z"/>
<path d="M87 147.2h.2v.9h-.2z"/>
<path d="M87.6 147.2h.3v.9h-.3z"/>
<path d="M88.3 147.2h.3v.9h-.3z"/>
<path d="M88.9 147.2h.3v.9h-.3z"/>
<path d="M89.6 147.2h.3v.9h-.3z"/>
<path d="M90.2 147.2h.3v.9h-.3z"/>
<path d="M90.9 147.2h.3v.9h-.3z"/>
<path d="M90.9 141.3h.3v1h-.3z"/>
<path d="M90.2 141.3h.3v1h-.3z"/>
<path d="M89.6 141.3h.3v1h-.3z"/>
<path d="M88.9 141.3h.3v1h-.3z"/>
<path d="M88.3 141.3h.3v1h-.3z"/>
<path d="M87.6 141.3h.3v1h-.3z"/>
<path d="M87 141.3h.2v1h-.2z"/>
</g>
<g fill="none" stroke="#800000" stroke-width=".42">
<path d="M55.9 138.3a1.4 1.4 0 0 1 1.4-1.3 1.4 1.4 0 0 1 1.4 1.3h-2.8M55.9 137h1.2M55.9 138.5a1.49 1.49 0 0 0 .9 1.2 1.32 1.32 0 0 0-.9 1.3 1.32 1.32 0 0 0 1 1.2 1.33 1.33 0 0 0-.9 1.5M55.9 140h.4M55.9 139.6h.8M55.9 139.2h.3M55.9 138.9h.1M55.9 138.5h.1M55.9 138.1h.1M55.9 137.7h.2M55.9 137.4h.4M55.9 136.6h34.8"/>
<path d="M55.9 136.2h35.1M55.9 135.9h14.9M55.9 135.5h1.2M55.9 135.1h.6M55.9 134.7h.1M56.7 135.3l-.8-.6v35.6M56.7 135.3h.1M56.7 135.3l1 .4h1.1l1-.4M57.3 137v1.4h-1.4M57.3 138.1h.1M57.3 137.7h.1M57.3 137.4h.1"/>
<path d="M57.4 137v1.4h1.3a1.45 1.45 0 0 1-.9 1.3 1.32 1.32 0 0 1 .9 1.3 1.32 1.32 0 0 1-.9 1.2 1.33 1.33 0 0 1 .9 1.5M57.5 137h32.8M58 139.6h29.8M58.3 140h29.5M58.3 137.4h31.6M58.4 139.2h29.6M58.6 137.7h30.9M58.6 138.9h29.8M58.7 138.1h30.5M58.7 138.5h30.1M59.4 135.5h10.8M59.8 135.3h.1"/>
<path d="M60.1 135.1h9.9M60.5 134.7h9.4M60.6 130.6h88.7M60.6 134.6v.1M60.6 134.6l-.8 .7M60.6 130.7l.6 .9 .2 1.1M60.6 130.7h.1M60.6 130.7l-.5-.4h89.6l-.5 .4M60.8 134.4h9.1M60.8 131h88.2M61 134h9M61 131.4h87.8"/>
<path d="M61.2 133.7h.1M61.2 133.7l-.6 .9M61.2 133.6h9.1M61.2 131.7h63.3M61.3 133.2h9.5M61.3 132.1h34.7M61.3 132.9h34.1M61.3 132.5h34.3M61.4 132.7l-.2 1M61.4 132.7h.1M69.9 134.6h2.8M69.9 134.5h2.8"/>
<path d="M70 134a1.39 1.39 0 0 1 1.3-.8 1.39 1.39 0 0 1 1.3 .8M70 134l-.1 .5 .1 .6M70 135.1a1.38 1.38 0 0 0 1.8 .8M71.3 133.2h.1M71.3 133.2v2.8M71.3 135.9h.1M71.3 135.5h.1M71.3 135.1h.1M71.3 134.7h.1M71.3 134.4h.1M71.3 134h.1M71.3 133.6h.1"/>
<path d="M71.7 133.2h6.9M71.8 135.9h6.7M72.3 133.6h5.6M72.3 135.5h5.6M72.3 135.5l-.5 .4M72.6 135.1h5.1M72.6 134h5.1M72.6 135.1l-.3 .4M72.6 134l.1 .5-.1 .6M72.7 134.7h4.9M72.7 134.4h4.9M79.2 133.2h16.1"/>
<path d="M79.3 135.9h12.1M79.9 133.6h2M79.9 135.5h2M80.1 134h1.5M80.1 135.1h1.5M80.2 134.7h1.2M80.2 134.4h1.2M81.4 134.3a1.13 1.13 0 0 0 1.1 1.4 1.13 1.13 0 0 0 1.1-1.4M83.1 133.6h2.4M83.1 133.6l.5 .7M83.1 133.6a1.13 1.13 0 0 0-1.7 .7M83.2 135.5h2.2"/>
<path d="M83.5 135.1h1.6M83.5 134h1.6M83.6 134.7h1.4M83.6 134.4h1.4M85 134.3a1.13 1.13 0 0 0 1.1 1.4 1.13 1.13 0 0 0 1.1-1.4M86.7 133.6h8.7M86.7 133.6l.5 .7M86.7 133.6a1.13 1.13 0 0 0-1.7 .7M86.7 135.5h5.1M87 135.1h5.2M87 134h8.5M87.2 134.7h5.3"/>
<path d="M87.2 134.4h5.7M90.3 140h3.9M90.7 139.6h3.5M91.1 139.2h3.1M91.5 138.9h2.9M91.8 138.5h3.1M92.2 138.1h2.5M92.6 137.7h1.7M93 137.4h1.2M93.3 137h.9M93.7 136.6h.6M95.9 138.5h6.7"/>
<path d="M96.2 138.1h6.1M96.4 138.9h5.6M96.5 137.7h5.4M96.5 136.6h5.4M96.6 139.2h5.2M96.6 140h5.2M96.6 137h5.2M96.6 139.6h5.2M96.6 137.4h5.2M97.4 132.1h1.1M97.8 132.5h.3M99.9 132.1h1.2"/>
<path d="M100.3 132.5h.3M102.4 132.1h1.2M102.8 132.5h.4M103.5 138.5h.8M103.8 138.1h.5M103.8 135.7l1.1 1.1M104 138.9h.3M104.1 137.7h.2M104.2 139.2h.1M104.2 140h.1M104.3 137.4a1.26 1.26 0 0 1-1.8 .8 1.26 1.26 0 0 1-.4-1.9h-5.8a1.25 1.25 0 0 1 0 1.7 1.25 1.25 0 0 1-1.8 0 1.25 1.25 0 0 1 0-1.7h-.5l-4.4 4.4v.1l1.7 .1 .3 .2v1.4l-.3 .2h-1.7v.3l-.6 .7h-1.8l-.3-.3h-1.7l-.7 .3M104.3 139.4a1.28 1.28 0 0 0-1.8-.9 1.28 1.28 0 0 0-.5 1.9"/>
<path d="M104.3 137l-.1 11.4 .1 .2 7.8 7.8 .3 .4M104.3 137h.1M104.3 139.9l-.2 .5M104.3 139.6h.1M104.3 137.4h.1M104.9 134.7h17.3M105 132.1h1.1M105.1 134.4h.8M105.3 135.1h16.6M105.4 132.5h.3M105.5 134h.1M105.5 132.8a1.34 1.34 0 0 0-1.2-.9 1.34 1.34 0 0 0-1.3 .9 1.34 1.34 0 0 0-1.3-.9 1.34 1.34 0 0 0-1.2 .9 1.34 1.34 0 0 0-1.3-.9 1.34 1.34 0 0 0-1.3 .9 1.35 1.35 0 0 0-2-.6 1.35 1.35 0 0 0-.1 2.1h-2.9l-5.1 5.1v1.4l-.4 .1"/>
<path d="M105.5 133.8l-.4 .6-.3 .2 1.9 1.8 .1 .3v10.2l5.5 5.5h14.3l1.2-1.2v-4.4l-.2 .1h-1.4l-.2-.2v-.5h-1.6l-.3-.2-1-1.2a1.35 1.35 0 0 1-1.4-1.1M105.5 132.8h.1M105.5 133.8h.1M105.5 133.8l.4 .6M105.5 132.8a1.38 1.38 0 0 1 1.3-.9v1.3h17.7M105.7 135.5h16M106.1 135.9h9.9M106.2 136.8v10.5M106.5 136.2h8.5M106.8 136.6h7.7M106.8 134.4h.1M106.8 134h.1"/>
<path d="M106.8 133.6h.1M106.8 132.9h.1M106.8 132.5h.1M106.8 132.1h.1M106.8 137h7.4M106.8 140h2.7M106.8 139.6h3.1M106.8 139.2h3.6M106.8 138.9h7M106.8 138.5h9.3M106.8 138.1h6.9M106.8 137.7h7"/>
<path d="M106.8 137.4h7.2M107.6 132.1l-.7-.2v2.8l.7-.2 .4-.5M107.6 132.1l.4 .5 .2 .6M107.6 132.1h16.9M107.7 134.4h16.8M108 132.5h16.5M108 134h16.5M108.2 132.9h16.3M108.2 133.6v-.3h-1.4v1.4l-.9-.3M108.2 133.6l-.2 .4M108.2 133.6h16.3M112.9 139.2h1"/>
<path d="M113.4 139.6h.6M113.8 140h.4M113.8 137.7l-.1 .5h5.3l-.1-.5M113.8 137.7a2.57 2.57 0 0 1 2.3-1.9v5.3l-1-.4M116.1 137h.5M116.1 140h.5M116.1 139.6h.5M116.1 139.2h.5M116.1 138.9h.5M116.1 138.1h.5M116.1 137.7h.5M116.1 137.4h.5"/>
<path d="M116.1 136.6h.5M116.1 136.2h.5M116.1 135.9h.5M116.6 138.5h7.9M116.8 135.9h4.9M117.8 136.2h3.9M118.2 136.6h3.7M118.5 140h6M118.5 137h3.8M118.7 139.6h5.8M118.7 137.4h5.8M118.9 139.2h5.6"/>
<path d="M118.9 137.7a2.65 2.65 0 0 0-2.3-1.9v5.3a2.62 2.62 0 0 0 2.4-2.4h-5.3a2.6 2.6 0 0 0 1.4 2M118.9 137.7h5.6M118.9 138.9h5.6M118.9 138.1h5.6M121.9 136.6a1.37 1.37 0 0 1 1.1-2.1 1.37 1.37 0 0 1 1.2 2.1M121.9 136.6l.4 .4M123.7 137h.8M123.8 134.7h.7M124.1 136.6h.4M124.2 136.6a1.36 1.36 0 0 1-1.9 .4M124.2 135.1h.3M124.3 136.2h.2"/>
<path d="M124.3 135.5h.2M124.4 135.9h.1M124.5 131.7v10.8l.3 .2h11.1l.2-.2v-10.8M124.5 131.7l.3-.2h11.1l.2 .2M136.1 133.2h5.2M136.1 137h2.7M136.1 140h2M136.1 139.6h2M136.1 139.2h2M136.1 138.9h2M136.1 138.5h2M136.1 138.1h2"/>
<path d="M136.1 137.7h2M136.1 137.4h2.3M136.1 136.6h3.1M136.1 136.2h17.8M136.1 135.9h5M136.1 135.5h4.5M136.1 135.1h4.3M136.1 134.7h4.2M136.1 134.4h4.2M136.1 134h4.4M136.1 133.6h4.6M136.1 132.9h12.4"/>
<path d="M136.1 132.5h12.4M136.1 132.1h12.5M136.1 131.7h12.6M139.7 140h.7M139.7 139.6h.7M139.7 139.2h.7M139.7 138.9h.7M139.7 138.5h.7M140 138.1h4.1M140.3 134.6h2.9M140.7 133.7l.5-.4 .5-.1v2.8a1.41 1.41 0 0 1-1.3-.8 1.41 1.41 0 0 1 .3-1.5zM141.7 133.2h.1"/>
<path d="M141.7 135.9h.1M141.7 135.5h.1M141.7 135.1h.1M141.7 134.7h.1M141.7 134.4h.1M141.7 134h.1M141.7 133.6h.1M141.8 133.2a1.42 1.42 0 0 1 1.4 1.4 1.42 1.42 0 0 1-1.4 1.4zM142.2 133.2h6.4M142.4 135.9h11.5M142.8 133.6h5.9M142.9 135.5h7.6"/>
<path d="M143 134h5.8M143.1 135.1h6.7M143.1 139.6h8.9M143.1 139.2h8.4M143.1 138.9h1.8M143.1 138.5h1.4M143.2 134.7h6.1M143.2 134.4h5.9M143.3 140h8.3M144.9 136.6h9M145 136.7h.1M145.3 137h8.6"/>
<path d="M145.7 137.4h5.9M148.5 132.7h.1M148.5 132.7l.2 1M148.7 131.6h.1M148.7 133.7h.1M148.7 131.6l-.2 1.1M148.7 133.7l.5 .9M149.2 130.7h.1M149.2 134.6v.1M149.2 130.7l-.5 .9M149.2 134.6h.1M149.2 134.6l.8 .7"/>
<path d="M150 135.3h.1M150 135.3l1 .4h1.1l1-.4M152.7 135.5h1.2M153.1 139.6h.8M153.1 135.3h.1M153.1 135.3l.8-.6v35.6M153.4 135.1h.5M153.4 137.4h.5M153.5 140h.4M153.6 139.2h.3M153.7 137.7h.2M153.8 138.9h.1"/>
<path d="M153.8 134.7h.1M153.9 138.1a1.36 1.36 0 0 0-1.1-1.1 1.36 1.36 0 0 0-1.4 .6h-5.5l-1.2-1.2-.3-.1h-4.7l-.3 .1-1.2 1.2-.1 .3v4.3l-2.5 2.4h-.9v-.4l-.3-.3h-1.4l-.1 .2-.2-.2h-1.4l-.1 .2-.3-.2h-.5v1.5h-.1v-1.5h-.6l-.3 .2-.1-.2h-1.4l-.1 .2-.2-.2h-1.4l-.2 .3v.4h-.9l-.7-.9M153.9 138.1a1.33 1.33 0 0 1-.9 1.5 1.34 1.34 0 0 1 .9 1.3 1.34 1.34 0 0 1-.9 1.3 1.34 1.34 0 0 1 .9 1.5M153.9 138.5h.1M153.9 138.1h.1M55.9 148.6h23.8M55.9 152.3h6M55.9 146.7h.3M55.9 155.7h22.2M55.9 156.1h22.2M55.9 146h.1M55.9 143.7h.1"/>
<path d="M55.9 155.3h22.2M55.9 153.8h7.3M55.9 145.6h.1M55.9 141.9h.5M55.9 148.2h23.5M55.9 158.7h7.6M55.9 142.6h.4M55.9 149.4h24.8M55.9 159.8h5.3M55.9 159.4h5.3M55.9 159.1h5.3M55.9 158.3h5.3"/>
<path d="M55.9 157.9h5.3M55.9 157.6h5.3M55.9 157.2h5.3M55.9 156.8h5.3M55.9 156.5h5.4M55.9 155h22.2M55.9 154.6h22.2M55.9 154.2h22.5M55.9 153.5h6.6M55.9 153.1h6.2M55.9 152.7h6.1M55.9 152h6"/>
<path d="M55.9 151.6h6M55.9 151.2h6.2M55.9 150.8h6.5M55.9 150.5h7M55.9 150.1h30.7M55.9 149.7h25.2M55.9 149h24.2M55.9 147.8h23.1M55.9 147.5h22.7M55.9 147.1h.6M55.9 146.3h.1M55.9 145.2h.3"/>
<path d="M55.9 144.8h.7M55.9 144.5h.6M55.9 144.1h.2M55.9 143.4h.1M55.9 143h.1M55.9 142.2h.8M55.9 141.5h.2M55.9 141.1h.1M55.9 140.7h.1M55.9 140.4h.2M56 143.7l.2 .5 .7 .5-.3 .1M56.2 145.2a1.38 1.38 0 0 0 1.1 2.2 1.38 1.38 0 0 0 1.2-2.2"/>
<path d="M56.6 144.8l-.4 .4M57.9 142.2h22.6M58.1 144.8l.4 .4M58.1 144.8h9.2M58.1 147.1h20.1M58.2 144.5h9M58.3 141.9h22.3M58.4 142.6h9.7M58.5 146.7h19.4M58.5 145.2h9.2M58.5 144.1h10.2M58.5 141.5h22.5"/>
<path d="M58.5 140.4h29.3M58.6 143h9.1M58.6 145.6h18.1M58.6 146.3h18.9M58.7 143.7h8.5M58.7 146h18.4M58.7 143.7l-.2 .5-.7 .5 .3 .1M58.7 143.4h8.6M58.7 141.1h27.9M58.7 140.7h29.1M61.3 156.4l.3-.1h1.9v4.8h-1.9l-.2-.1-.2-.3v-1.8h4.9l-.1 2-.3 .2h-1.8v-4.8h2l.2 .3v1.9h-4.9zM62.1 153.1a1.83 1.83 0 0 1 1.6-2.9 1.83 1.83 0 0 1 1.5 2.9"/>
<path d="M62.1 153.1a1.86 1.86 0 0 0 3.1 0M63.5 159.8h.4M63.5 159.4h.4M63.5 159.1h.4M63.5 158.3h.4M63.5 157.9h.4M63.5 157.6h.4M63.5 157.2h.4M63.5 156.8h.4M63.5 156.5h.4M63.9 158.7h9M64.1 153.8h14.7"/>
<path d="M64.5 150.5h22.1M64.8 153.5h14.4M65 150.8h21.6M65.2 153.1h14.3M65.3 151.2h21.3M65.3 152.7h14.6M65.4 151.6h21.2M65.5 152.3h14.8M65.5 152h21.1M66 156.5h12.1M66.1 159.8h6.8M66.1 159.4h6.8"/>
<path d="M66.1 159.1h6.8M66.1 158.3h6.8M66.1 157.9h7M66.1 157.6h12M66.1 157.2h12M66.1 156.8h12M68.1 145.6l-.9-.9v-.6h3.1v.6l-.9 .9M68.7 145.6v-3h-.6l-.9 .8v.6h3.1v-.6l-.9-.8h-.6v3M68.7 143.7h.1M68.7 142.6h.1M68.7 145.2h.1M68.7 144.8h.1"/>
<path d="M68.7 144.5h.1M68.7 143.4h.1M68.7 143h.1M68.8 144.1h6.1M69.4 142.6h11.1M69.8 145.2h5.6M69.8 143h5.6M70.1 144.8h4.9M70.2 143.4h4.8M70.3 143.7h4.6M70.3 144.5h4.6M72.9 160h2.5"/>
<path d="M72.9 158.7h2.5M74.1 160v3.8M74.1 157.8v.9M74.1 158.3h.1M74.1 157.9h.1M75.2 157.9h2.9M75.3 159.4h2.8M75.4 159.8h2.7M75.4 158.7h2.7M75.4 159.1h2.7M75.4 158.3h2.7M75.8 142.6l-.9 .9v1.2l.9 .9h.9l3.6 3.6 .3 .1"/>
<path d="M77 142.6l.9 .9v.9l3 3.1M77.4 143h3.2M77.7 143.4h3.1M77.9 143.7h3.5M77.9 144.1h3.5M77.9 144.5h2.9M78.3 144.8h2.3M78.7 145.2h1.8M79 145.6h1.5M79.4 146h1.2M79.7 155.7h.8M79.7 156.1h.7"/>
<path d="M79.7 155.3h1M79.7 158.7h2.8M79.7 159.8h2.8M79.7 159.4h2.8M79.7 159.1h2.8M79.7 158.3h2.8M79.7 157.9h2.9M79.7 157.6h8.6M79.7 157.2h1.2M79.7 156.8h.9M79.7 156.5h.7M79.8 146.3h1.1"/>
<path d="M80 155h1.1M80.2 146.7h6.4M80.3 154.6h13.8M80.5 145.3h2.5M80.5 145.4h2.5M80.5 142.5h2.5M80.5 142.6l.1 .4M80.5 147.1h6.1M80.6 143l.2 .3M80.7 154.2h13.6M80.8 143.3a1.31 1.31 0 0 0 1.9 0M80.9 147.5a1.35 1.35 0 0 1 2.2 .8"/>
<path d="M80.9 147.5h.1M81.1 153.8h13.5M81.4 144.1h.7M81.4 144.1a1.28 1.28 0 0 0-.5 2.2 1.28 1.28 0 0 0 2.1-.8M81.7 141.2v2.6M81.7 144.1v2.5M81.7 146h.1M81.7 143.7h.1M81.7 145.6h.1M81.7 141.9h.1M81.7 142.6h.1M81.7 146.3h.1"/>
<path d="M81.7 145.2h.1M81.7 144.8h.1M81.7 144.5h.1M81.7 144.1h.1M81.7 143.4h.1M81.7 143h.1M81.7 142.2h.1M81.7 141.5h.1M81.8 141.2v2.6M81.8 144.1v2.5M82.1 144.1a1.29 1.29 0 0 1 .9 1.1M82.1 144.1h8.7"/>
<path d="M82.1 143.7h9.1M82.4 149.7h4.2M82.4 155h11.7M82.5 160h2.4M82.5 158.7h2.4M82.5 141.5h1.1M82.6 146.3h.9M82.6 157.2h5.8M82.6 147.5h4M82.7 144.5h.7M82.7 143.4h.7M82.8 155.3h11.4"/>
<path d="M82.8 149.4h3.8M82.9 141.9h.3M82.9 146h.3M82.9 156.8h5.7M82.9 147.8h3.7M82.9 144.8h.3M83 143l-.3 .3M83 143h.2M83 145.6h.1M83 142.2h.1M83 142.4a1.29 1.29 0 0 0-1.3-1.2 1.29 1.29 0 0 0-1.2 1.4M83 155.7h11.4"/>
<path d="M83 142.6h.1M83 142.6v.4M83 149h3.6M83 145.2h.1M83.1 145.6a1.25 1.25 0 0 1 .8-1.4 1.25 1.25 0 0 1 1.5 .6h1l1.3 1.2v.7h.4M83.1 145.6a1.25 1.25 0 0 0 1 1 1.25 1.25 0 0 0 1.3-.7h.6l.6 .6v5.6h-6l-.3 .2-2.1 2.1-.1 .3v8.6l.1 .3M83.1 148.2h3.5M83.1 156.5h6M83.1 148.6h3.5M83.1 156.1h11.9M83.1 148.3a1.36 1.36 0 0 1-.8 1.5 1.36 1.36 0 0 1-1.6-.5M83.7 157.8v4.7"/>
<path d="M83.7 158.7h.1M83.7 159.8h.1M83.7 159.4h.1M83.7 159.1h.1M83.7 158.3h.1M83.7 157.9h.1M84.7 157.9h3.6M84.9 159.4h9.4M84.9 158.7h3.8M84.9 159.8h9.3M84.9 159.1h4.4M84.9 158.3h3.5"/>
<path d="M85 141.5h1.6M85 146.3h1.4M85.2 144.5h5.2M85.4 146h.6M85.4 141.9h1.2M85.5 142.2h1.1M85.5 142.3a1.25 1.25 0 0 0-2.1-.7 1.25 1.25 0 0 0 .7 2.1M85.5 142.3h.1M86.5 144.8h3.5M86.6 141.1v1.2h-1.1M86.9 145.2h2.8M87.2 145.6h2.1"/>
<path d="M87.4 140.9h-.6l-.2 .2M87.4 140.9h.1M87.6 146h1.3M87.7 146.3h.8M87.8 140.8v1M87.8 141.5h.1M87.8 141.1h.1M88.1 146.7h.1M88.3 157.8h2.8M88.3 157.7h2.8M88.3 157.6a1.43 1.43 0 0 0 1.1 1.5M88.3 150.4l.3 .5 .3 .4 .5 .1"/>
<path d="M88.3 149.4h.3M88.3 151.2h.6M88.3 150.8h.2M88.3 150.5h.1M88.3 150.1h.1M88.3 149.7h.1M88.3 149h.6M88.4 157.2l-.1 .4M88.4 146.7v1.9M88.4 147.6h.1M88.4 146.7h.1M88.4 148.2h.1"/>
<path d="M88.4 147.8h.1M88.4 147.5h.1M88.4 147.1h.1M88.6 149.4l-.3 .4M88.6 156.8a1.41 1.41 0 0 1 2.2 0M88.6 156.8l-.2 .4M88.9 149l.5-.2h.8l.2-.2h-2.1v2.8h2.1l3.8-3.7v-.7l.2-.5h-2.6l-.2 .3v2.2l-.6 .6a1.3 1.3 0 0 1-1 1.8M88.9 149l-.3 .4M89.3 143.4h4.1M89.4 159.1h.6M89.4 148.5h.1M89.6 143h4.2"/>
<path d="M89.6 140.7h5.2M89.7 158.7h.1M89.7 156.3v2.8M89.7 159.1h.1M89.7 158.3h.1M89.7 157.9h.1M89.7 157.6h.1M89.7 157.2h.1M89.7 156.8h.1M89.7 156.5h.1M89.7 141.8h.7M89.7 140.8v1.9"/>
<path d="M89.7 141.9h.1M89.7 142.6h.1M89.7 142.2h.1M89.7 141.5h.1M89.7 141.1h.1M90 140.4h4.4M90 148.5l-1.4 .1M90 148.5h.1M90 148.5l.1 .1M90 159.1h4.5M90.3 156.5h4.3M90.4 140.8v1.9"/>
<path d="M90.4 147.6v1M90.4 147.6h.1M90.4 141.9h.1M90.4 148.2h.1M90.4 142.6h.1M90.4 147.8h.1M90.4 142.2h.1M90.4 141.5h.1M90.4 141.1h.1M90.5 151.2h.2M90.7 158.7h14.4M90.8 156.8l.2 .4"/>
<path d="M90.8 156.8h3.5M90.8 150.8h.2M91 158.3h3.6M91 157.2l.1 .4M91 157.2h3.2M91 150.5h.4M91 149.7h1.2M91 150.1h.8M91.1 157.9h3.2M91.1 157.6a1.38 1.38 0 0 1-1.1 1.5M91.1 157.6h3.1M91.2 149.4h1.3"/>
<path d="M91.4 142.6h2.8M91.5 141.1h3.2M91.6 148.6h1.7M91.6 141.9h2.6M91.6 148.2h2M91.6 149h1.3M91.6 147.8h2.4M91.6 147.5h2.6M91.6 147.1h2.6M91.6 142.2h2.6M91.6 141.5h2.7M91.6 153.5h3.3"/>
<path d="M91.7 146.7h2.6M91.7 153.4l-.6 .4h-10l-1.4 1.4v7.6l2.7 2.7h.1v-1.2M91.7 153.4v.1M92 153.1h2.4M92.4 152.7h1.8M92.7 152.3h1.5M93.1 152h1.1M93.5 151.6h.9M93.9 151.2h.9M94.1 155h2.6M94.1 155a1.31 1.31 0 0 0 1.2 1.2M94.2 142.6l-.9 .9h-1.9l-2.9 2.9v.3h-.4"/>
<path d="M94.2 150.8h.5M94.3 141.5l-.1 .4v.7M94.7 150.9l.8 .2a1.26 1.26 0 0 0-1.4 1.2 1.26 1.26 0 0 0 1.3 1.3 1.26 1.26 0 0 0 1.2-1.4l3.4 3.4 .3 .1M94.7 150.9l-.2-.3-2.8 2.8M94.8 148.6h.2M95.2 158.7a1.26 1.26 0 0 0-.8 1.9 1.26 1.26 0 0 0 2.1 0 1.26 1.26 0 0 0-.8-1.9M95.3 153.6a1.31 1.31 0 0 0-1.2 1.2h2.6a1.26 1.26 0 0 0-1.2-1.2v2.6a1.31 1.31 0 0 0 1.2-1.2M95.3 153.6v2.6M95.3 155.7h.2M95.3 156.1h.2M95.3 155.3h.2M95.3 153.8h.2"/>
<path d="M95.3 155h.2M95.3 154.6h.2M95.3 154.2h.2M95.8 148.6h6.9M95.9 156.1h6.8M95.9 153.5h2M96.1 141.1h.1M96.1 141.1l-.3-.3a1.26 1.26 0 0 1-1.7-1 1.26 1.26 0 0 1 1.4-1.4 1.26 1.26 0 0 1 1.1 1.6l1 1v4.3l-1.2 1.2a1.25 1.25 0 0 1 .1 1.5 1.25 1.25 0 0 1-1.5 .4l-.3 .3a1.23 1.23 0 0 1 1.3 0 1.23 1.23 0 0 1 .6 1.2l4.2 4.2h1.3a1.23 1.23 0 0 1 1.9 0h1.3l.2-.3M96.1 141.1a1.26 1.26 0 0 0-1.8 .4M96.2 153.8h2.1M96.2 148.2h6M96.2 156.5h6"/>
<path d="M96.2 158.3h6M96.3 159.1h5.8M96.3 149h5.8M96.4 155.7h5.7M96.4 153.1h1.2M96.5 146.3h5.7M96.5 147.8h5.4M96.5 157.9h5.4M96.5 156.8h5.4M96.5 154.2h2.2M96.5 146.7h5.4M96.5 159.4h5.4"/>
<path d="M96.6 149.4h5.3M96.6 152.7h.6M96.6 155.3h3.2M96.6 152.3h.2M96.6 159.8h5.2M96.6 157.6h5.2M96.6 157.2h5.2M96.6 149.7h5.2M96.6 147.5h5.2M96.6 147.1h5.2M96.7 154.6h2.3M96.7 155h2.7"/>
<path d="M96.8 146h7.5M96.9 150.1h4.9M96.9 140.4h5.1M97.2 145.6h5M97.2 150.5h4.8M97.3 140.7h5.1M97.6 143.7h4.7M97.6 141.9h4.2M97.6 142.6h4.3M97.6 145.2h4.3M97.6 144.8h4.2M97.6 144.5h4.2"/>
<path d="M97.6 144.1h4.3M97.6 143.4h5M97.6 143h4.5M97.6 142.2h4.2M97.6 141.5h4.4M97.6 141.1h4.8M97.6 150.8h4.7M98 151.2h4.4M98.3 151.6h3.7M98.7 152h3.1M99.1 152.3h3.9M99.5 152.7h2.3"/>
<path d="M99.8 153.1h2.2M100.2 153.5h2.2M100.6 153.8h1.7M102 150.5a1.27 1.27 0 0 1 .8-1.9 1.27 1.27 0 0 1 1.5 1.4 1.27 1.27 0 0 1-2 .9M102 140.4a1.29 1.29 0 0 0 2.1 0M102 141.5a1.27 1.27 0 0 0 .5 1.9 1.27 1.27 0 0 0 1.8-1M102 150.5l.3 .4M102.1 155.7a1.23 1.23 0 0 0 1.9 0M102.8 158.7a1.26 1.26 0 0 0-1 1.7 1.26 1.26 0 0 0 1.8 .7l7.2 7.2 .3 .1h12.1l1.3 1.2a1.37 1.37 0 0 0 1.4 1.6 1.37 1.37 0 0 0 1.2-1.7M102.9 151a1.31 1.31 0 0 0-1.2 1.3h2.6a1.26 1.26 0 0 0-1.2-1.3M102.9 153.6a1.31 1.31 0 0 1-1.2-1.2h2.6a1.26 1.26 0 0 1-1.2 1.2M103 151v2.6"/>
<path d="M103 153.5h.1M103 153.1h.1M103 152.7h.1M103 152h.1M103 151.6h.1M103 151.2h.1M103.1 152.3h5M103.1 151v2.6M103.3 158.7l.8 .6 7.5 7.5h12.1l.3 .1 1.6 1.6M103.3 156.1h2.6M103.4 148.6h.9M103.4 143.4h.9"/>
<path d="M103.6 140.7h.7M103.7 153.5h1.9M103.7 151.2h1.9M103.7 141.1h.6M103.7 141.1a1.25 1.25 0 0 0-1.7 .4M103.7 141.1l.4 .4M103.7 153.8h1.8M103.7 150.8h2.9M103.8 143.7h.5M103.8 148.2h.4M103.8 156.5h2.8M103.9 158.3h.8"/>
<path d="M103.9 146.3h.4M103.9 145.6h.4M103.9 159.1h1.6M103.9 149h.8M104 143h.3M104.1 140.4h.2M104.1 141.5l.2 .4M104.1 153.1h1.1M104.1 151.6h1.1M104.1 141.5h.2M104.1 150.5h2.1M104.1 147.8h.2"/>
<path d="M104.1 144.1h.2M104.1 146.7h.2M104.2 145.2h.1M104.2 142.6h.1M104.2 149.4h.9M104.2 141.9h.1M104.2 150.1h1.6M104.3 144.5a1.27 1.27 0 0 0-2.2-.7 1.27 1.27 0 0 0 .7 2.2M104.3 147a1.27 1.27 0 0 0-2-.8 1.27 1.27 0 0 0 0 2.1 1.27 1.27 0 0 0 2-.8M104.3 145l-.2 .4-.4 .4-.4 .2M104.3 152.7h.7M104.3 152h.7"/>
<path d="M104.3 149.7h1.1M104.3 147.5h.1M104.3 147.1h.1M104.3 144.8h.1M104.3 144.5h.1M104.3 142.2h.1M104.3 159.4h1.5M104.7 159.8h1.5M104.9 152.4h2.6M105.5 153.8l.5-.2 .9 .2M105.5 156.8h1.5M105.6 147.8h.3"/>
<path d="M105.6 157h.1M105.9 157.2h1.5M105.9 148.2h.3M106.2 151v2.6M106.2 153.5h.1M106.2 153.1h.1M106.2 152.7h.1M106.2 152h.1M106.2 151.6h.1M106.2 151.2h.1M106.3 157.6h1.5M106.3 148.6h.3"/>
<path d="M106.6 157.9h1.5M106.7 149h.3M106.8 146.7h6.1M106.8 146h6.9M106.8 143.7h3.7M106.8 145.6h7.2M106.8 141.9h2.3M106.8 142.6h2.6M106.8 153.5h2.4M106.8 146.3h6.5M106.8 145.2h7.1M106.8 144.8h7"/>
<path d="M106.8 144.5h7M106.8 144.1h7M106.8 143.4h3.1M106.8 143h2.8M106.8 142.2h2.4M106.8 141.5h2.3M106.8 141.1h2.3M106.8 140.7h2.4M106.8 140.4h2.5M106.8 151.2h.1M106.9 153.8l.3 .4 .2 .8M106.9 153.8h2.7"/>
<path d="M107 147.1h5.8M107 158.3h1.5M107.1 149.4h.3M107.2 153.1h1.6M107.3 154.2h2.6M107.3 151.6h.1M107.3 147.5h5.5M107.4 158.7h1.5M107.4 154.6h2.9M107.4 152.7h1M107.4 152h.3M107.4 155h3.3"/>
<path d="M107.4 149.7h.3M107.7 147.8h5.1M107.7 159.1h1.6M107.8 155.3h3.2M107.8 150.1h.3M108.1 148.2h4.7M108.1 159.4h1.5M108.2 155.7h3.2M108.2 150.5h.3M108.5 148.6h4.3M108.5 159.8h1.5M108.6 156.1h3.2"/>
<path d="M108.6 150.8h.2M108.8 149h4M108.9 156.5h3.2M108.9 151.2h.3M109.1 141.1a2.58 2.58 0 0 0 2.6 2.9 2.58 2.58 0 0 0 2.5-2.9M109.1 141.1a2.58 2.58 0 0 1 2.6-2.2 2.58 2.58 0 0 1 2.5 2.2M109.2 149.4h3.1M109.3 156.8h3.1M109.3 151.6h.3M109.6 149.7h2.7M109.7 157.2h13.6M109.7 152h.3"/>
<path d="M110 150.1h2.3M110 157.6h29.3M110.1 152.3h.2M110.3 150.5h2M110.4 157.9h28.9M110.4 152.7h.3M110.7 150.8h1.6M110.8 158.3h28.5M110.8 153.1h.3M111.1 151.2h1.2M111.2 158.7h28.2M111.2 153.5h.3"/>
<path d="M111.5 151.6h.9M111.5 159.1h28.2M111.8 152h9.6M111.9 154.2h21.7M112.1 153.8l-.4-.1-6.1-6.2v.4l7.5 7.4h9.9a1.27 1.27 0 0 1 1.9 0 1.27 1.27 0 0 1-.2 1.9M112.2 152.3h14.4M112.3 154.6h21M112.4 156.8l.3 .2h10.3l.3 .2M112.7 155h10.8M112.8 143.7h1.1M113.4 143.4h.6M113.7 143h.5"/>
<path d="M113.8 144.1v.7l.2 .8M113.9 142.6h.7M114 140.4h.6M114 145.6l-1.1 1.2-.1 .3v2h-.3l-.2 .3v2.1l.2 .2h2.1l.3-.2v-2.1l-.3-.3h-.2v-1.5l.8-.9 .3 .2v.2M114.1 142.2h1M114.1 140.7h1M114.2 141.9h10.3M114.2 141.5h10.3M114.2 141.1h10.3M114.4 148.6h2.5M114.4 148.2h2.1M114.4 149h2.8"/>
<path d="M114.4 147.8h1.7M114.5 147.5h1.2M114.7 151.6h1.2M114.8 149.4h1M114.9 151.2h.6M114.9 150.8h.4M114.9 150.5h.4M114.9 150.1h.4M114.9 149.7h.6M114.9 147.1h.6M115.3 150.4h2.7M115.3 150.5h2.7"/>
<path d="M115.3 150.1a1.35 1.35 0 0 1 1.3-1 1.35 1.35 0 0 1 1.3 1M115.3 150.1a1.35 1.35 0 0 0 1.3 1.7 1.35 1.35 0 0 0 1.3-1.7M115.5 147.1l.2 .3 4.3 4.3 .3 .2h1l.1 .1M116 141.9a2.59 2.59 0 0 0-2.2 2.2M116.1 140.7h.5M116.1 140.4h.5M116.6 149.1v2.7M116.6 149.4h.1M116.6 151.6h.1M116.6 151.2h.1M116.6 150.8h.1M116.6 150.5h.1"/>
<path d="M116.6 150.1h.1M116.6 149.7h.1M116.7 141.9a2.59 2.59 0 0 1 2.2 2.2M117.3 151.6h2.6M117.4 149.4h.2M117.5 146.7h3.1M117.6 142.2h4.8M117.6 140.7h6.9M117.7 147.1h2.9M117.7 151.2h1.8M117.8 149.7h.2M117.9 150.8h1.2"/>
<path d="M117.9 150.1h.5M118 150.5h.7M118 147.5h2.9M118.1 146.3h2.5M118.1 142.6h3.9M118.2 140.4h6.3M118.4 147.8h2.3M118.4 146h2.2M118.5 143h3.3M118.6 145.6h2M118.7 143.4h3M118.8 148.2h9"/>
<path d="M118.8 143.7h2.9M118.8 145.2h2M118.9 144.8h4.2M118.9 144.1a2.55 2.55 0 0 1-1.5 2.7l3.4 3.4h.5l.5-.2h1.8l.7 .5 .1 .4M118.9 144.5h3.3M118.9 144.1h2.9M119.2 148.6h1.4M119.5 149h1.3M119.9 149.4h1.4M120.3 149.7h7.5M120.6 148.3h2.3M120.6 147.1v-1.7l.3-.3h1.7l.3 .3v1.7"/>
<path d="M120.6 147.1l.4 .2-.3 .5M120.6 150.1h1M120.7 147.8a1.17 1.17 0 0 0 .6 1.6M121.3 149.4h.9M121.4 152l.4 .1h1.8l.4-.1M121.7 143.7a1.37 1.37 0 0 1 1.3-1.6 1.37 1.37 0 0 1 1.4 1.6M121.7 148.6h.1M121.7 148.3v1.1M121.7 149.4h.1M121.7 149h.1M121.8 148.3v1.1M122.2 149.4h5.6"/>
<path d="M122.6 147.5h5.2M122.7 149h5.1M122.7 145.2h.7M122.8 147.8a1.17 1.17 0 0 1-.6 1.6M122.8 147.8h5M122.9 146.7h3.1M122.9 146h1.2M122.9 145.6h.9M122.9 147.1l-.5 .2 .4 .5M122.9 147.1h4.9M122.9 146.3h3.1M122.9 148.6h4.9"/>
<path d="M123.3 157.2l.4 .2h.5l.5-.2M123.6 142.2h.9M123.8 150.1h4M124 152h3M124.1 142.6h.6M124.3 150.5h3.5M124.3 143h12.9M124.3 151.6h3.1M124.4 143.7h12.1M124.4 143.4h12.5M124.4 155h6.7M124.4 150.9l-.1 .8-.3 .3"/>
<path d="M124.4 151.2h3.3M124.4 150.8h3.4M124.5 146.2h.1M124.6 144.1h1.4M124.7 157.2h6.2M124.9 155.3h5.7M124.9 144.5h1.1M125 156.8h5.5M125.2 155.7h5.2M125.2 156.5h5.2M125.2 156.1h5.1M127.4 153.8h6.6"/>
<path d="M127.8 153.5h6.6M128.2 153.1h6.4M128.5 152.7h6.1M128.9 152.3h5.7M129.3 152h4.8M129.3 152l-1.9 1.8-.3 .1-.5-.1h-15M129.4 148.6h2.4M129.4 148.2h2M129.4 149.4h3.1M129.4 151.6h4.4M129.4 151.2h4.3M129.4 150.8h4.3"/>
<path d="M129.4 150.5h4.2M129.4 150.1h3.9M129.4 149.7h3.5M129.4 149h2.7M129.4 147.8h1.8M129.4 147.5h1.8M129.4 147.1h1.8M130.3 146.7h.1M130.3 146h.1M130.3 145.6h.1M130.3 146.3h.1M130.3 145.2h.1"/>
<path d="M130.3 144.8h.1M130.3 144.5h.1M130.3 144.1h.1M130.9 157.2l.4 .2h.5l.5-.2M131.2 147.8v-1l-.2 .1-.6 .1v-1.5h-.1v1.5l-.7-.1-.2-.1v4.9l-.1 .3M131.2 147.8l.4 .6 2.2 2.2-.1 .3M132 155h.9M132.3 157.2h7M132.8 147.1h2.3M132.9 147.5h2.2M133.3 156.8l-.8 .2-.2 .2M133.3 156.8h6"/>
<path d="M133.3 147.8h1.8M133.7 150.9v.4l.4 .7M133.7 156.5h5.6M133.7 148.2h1.7M134.1 148.6h1.6M134.1 156.1h5.3M134.1 152l.5 .1v1.2l-2.1 2a1.27 1.27 0 0 0-1.9 0 1.27 1.27 0 0 0 .3 1.9M134.4 155.7h5.3M134.5 149h1.6M134.6 144.1h1.5M134.6 146.7h.5M134.7 146.3h.4"/>
<path d="M134.7 144.5h1.1M134.8 155.3h7.7M134.8 149.4h1.7M135.2 155h6.9M135.2 149.7h1.7M135.6 154.6h6.1M135.9 154.2h5.5M136 142.6h1.6M136.1 141.9h2M136.1 142.2h1.9M136.1 141.5h2M136.1 141.1h2"/>
<path d="M136.1 140.7h2M136.1 140.4h2M136.2 153.8h4.8M136.2 152.3h3.3M136.2 153.5h4.4M136.2 153.1h4.1M136.2 152.7h3.7M136.5 150.1h.7M136.7 152l-.5 .1v1.7l-.1 .3-2.8 2.7M136.7 152h2.4M136.8 146.7h7.1M136.8 146h3.8"/>
<path d="M136.8 147.1h6.8M136.8 146.3h4.3M136.9 145.6h3.5M136.9 147.5h6.3M137 150.5h.6M137 151.6h1.7M137.1 150.9l-.4-.7-.4-.2h-.8l-2.7-2.7v-.5l.2 .1h1.4l.3-.2v-.5h.4l.2 1.9 7.4 7.4-.7 .5-.2 .4v2l.5 .7h-1.1l.5-.6v-1h-1.2v-2.1a1.23 1.23 0 0 1 1.2 1.1v.9h-2.4v-.9a1.23 1.23 0 0 1 1.1-1.1v2.1h-1.1v1l.4 .6h-28.1l-4.2-4.1M137.1 150.9v.4l-.4 .7M137.1 151.2h1.3M137.1 150.8h.9M137.3 147.8h5.5M137.3 145.2h3"/>
<path d="M137.7 148.2h4.8M137.7 144.8h2.6M138 148.6h4.1M138 144.5h2.4M138.4 149h2M138.4 144.1h2.3M138.8 149.4h1.6M138.8 143.7h2.5M139.2 149.7h1.2M139.2 143.4h5.2M139.6 150.1h.8M139.6 143h4.4"/>
<path d="M139.7 141.9h3.2M139.7 142.6h3.9M139.7 142.2h3.5M139.7 141.5h2.8M139.7 141.1h2.4M139.7 140.7h.7M139.7 140.4h.7M139.9 150.5h.5M140.3 150.8h.1M140.3 145.1h2.9M140.4 140.7l.2 .3h1.4l2.8 2.8v2.1l-2.8 2.8h-1.4l-.2 .2v2l-3.6-3.6v-1.5l2.8-2.8 .1-.3v-4.3l.5-.5h3.8l1.1 1.2 .3 .1h6l.7 .4a1.34 1.34 0 0 0-.9 1.3 1.34 1.34 0 0 0 .9 1.3l-.7 .4h-3.2l-.5 .4M140.4 140.7v-2.2l.2-.3h2.3l.2 .3v1.3l3.2 3.2"/>
<path d="M140.4 155.7h.1M140.4 156.1h.1M140.4 157.2h.1M140.4 156.8h.1M140.4 156.5h.1M140.7 144.1l.5-.3 .5-.1v2.8a1.43 1.43 0 0 1-1.3-.8 1.43 1.43 0 0 1 .3-1.6zM141 151.6h12.9M141.2 155.7h1.1M141.3 159.1h1M141.4 152h12.5M141.6 156.1h.4M141.6 158.7h.4"/>
<path d="M141.7 156.5h.1M141.7 158.3h.1M141.7 157.9h.1M141.7 157.6h.1M141.7 157.2h.1M141.7 156.8h.1M141.7 146h.1M141.7 143.7h.1M141.7 145.6h.1M141.7 146.3h.1M141.7 145.2h.1M141.7 144.8h.1"/>
<path d="M141.7 144.5h.1M141.7 144.1h.1M141.8 143.7a1.42 1.42 0 0 1 1.4 1.4 1.42 1.42 0 0 1-1.4 1.4zM141.8 152.3h12.1M142.2 152.7h11.7M142.2 143.7h2.5M142.4 146.3h1.9M142.5 153.1h11.4M142.8 144.1h2M142.9 146h1.8M142.9 153.5h11M143 144.5h1.8"/>
<path d="M143.1 145.6h1.7M143.1 151.2l-.2 .2h-2l4.2 4.2a1.14 1.14 0 0 1 1.6 .8v2l-.3 .6v.5l-.2 .3-.8 .8-.3 .2h-34l-.3-.2-4.5-4.5-.8-.2-.2-.2h-1.4M143.1 151.2h10.8M143.1 150.8h10.8M143.1 150.5h10.8M143.1 150.1h10.8M143.2 145.2h1.6M143.2 144.8h1.6M143.2 149.7h10.7M143.3 153.8h10.6M143.6 149.4h10.3M143.7 154.2h10.2"/>
<path d="M143.7 140.4h7.6M144 149h9.9M144 140.7h7.2M144 154.6h9.9M144.4 148.6h9.5M144.4 141.1h6.8M144.4 155h9.5M144.7 148.2h9.2M144.8 155.3h9.1M144.8 141.5h6.5M145.1 147.8h8.8M145.1 141.9h6.5"/>
<path d="M145.5 147.5h8.4M145.5 142.2h6.5M145.9 147.1h5.8M145.9 142.6h5.6M146.2 159.8h7.7M146.2 146.7h5.1M146.3 155.7h7.6M146.3 143h1.4M146.3 143l.1 .3v1l1.3-1.3M146.4 159.4h7.5M146.4 159.1h7.5M146.4 143.7h.5"/>
<path d="M146.4 144.1h.2M146.4 143.4h.9M146.6 156.1h7.3M146.6 158.7h7.3M146.6 146.3h4.6M146.7 158.3h7.2M146.7 157.9h7.2M146.7 157.6h7.2M146.7 157.2h7.2M146.7 156.8h7.2M146.7 156.5h7.2M147 146h5.5v1.4l-.7-.2-.5-.5"/>
<path d="M147.4 145.6h3.8M147.7 145.2h3.7M148.1 144.8h3.6M148.5 144.5h3.2M152 144.7h.1M152 144.7a1.39 1.39 0 0 0-.9 1.2M152 144.7l-.6-.4h-2.7l-5.6 5.6v1.3M152.5 146.7h.1M152.5 147.1h.1M152.5 146.3h.1M153.1 144.7h.1M153.1 144.7l.6 .5 .2 .7"/>
<path d="M153.1 142.2h.8M153.4 144.8h.5M153.4 147.1h.5M153.4 144.5h.5M153.5 141.9h.4M153.6 142.6h.3M153.7 145.2h.2M153.7 144.1h.2M153.7 146.7h.2M153.8 141.5h.1M153.8 140.4h.1M153.8 143h.1"/>
<path d="M153.9 143.7l-.2 .5-.6 .5M153.9 143.7h.1M153.9 145.6h.1M153.9 146.3h.1M153.9 143.4h.1M153.9 141.1h.1M153.9 140.7h.1M153.9 146h-2.8l.2 .7M153.9 145.9h-1.3v1.5l.7-.2 .4-.5M153.9 146.1l-.2 .6M55.9 170.3h.1M55.9 165.8h6.1"/>
<path d="M55.9 163.9h6.6M55.9 168.4h13.3M55.9 168.8h13.3M55.9 161.7h17M55.9 169.9h.5M55.9 169.6h1.1M55.9 169.2h13.3M55.9 168.1h13.3M55.9 167.7h9.1M55.9 167.3h8.7M55.9 166.9h7.1M55.9 166.6h6.5"/>
<path d="M55.9 166.2h6.2M55.9 165.4h6M55.9 165.1h6M55.9 164.7h6.1M55.9 164.3h6.2M55.9 163.6h7.2M55.9 163.2h17M55.9 162.8h17M55.9 162.5h17M55.9 162.1h17M55.9 161.3h17M55.9 161h5.4"/>
<path d="M55.9 160.6h5.3M55.9 160.2h5.3M56.7 169.7l1-.4h1.1l1 .4M56.7 169.7h.1M56.7 169.7l-.8 .6M59.6 169.6h9.6M59.8 169.7h.1M59.8 169.7l.8 .6M60.2 169.9h9M60.5 174.4h88.9M60.6 170.3h8.6M60.6 174.3l-.4 .4h89.4l-.4-.4"/>
<path d="M60.6 170.3h.1M60.6 174.3h.1M60.6 170.3l.6 1M60.8 174.1h88.3M60.8 170.7h8.4M61 173.7h87.8M61.1 171h8.1M61.2 173.4l-.6 .9M61.2 171.3h.1M61.2 173.4h.1M61.2 171.3l.2 1-.2 1.1M61.2 173.3h9.6"/>
<path d="M61.2 171.4h8M61.3 172.9h9.1M61.3 171.8h8M61.3 172.6h8.8M61.3 172.2h8.4M63.5 161h.4M63.5 160.6h.4M63.5 160.2h.4M64.2 163.6h8.7M64.9 163.9h8M65.2 164.3h4.4M65.4 164.7h3.8"/>
<path d="M65.4 165.8a1.81 1.81 0 0 0-1.5-2.3 1.81 1.81 0 0 0-2 1.9 1.81 1.81 0 0 0 2.3 1.6l.7 .6 .3 .1h3.1l.3-.1 1.8-1.8h.2l-1.3 1.3-.1 .3v4.1l.1 .3M65.4 165.8h2.7M65.5 165.4h3M65.5 165.1h3.3M66 161h6.9M66.1 160.6h6.9M66.1 160.2h6.8M68.4 167.7h.8M68.9 167.3h.3M69.2 166.9h.3M69.3 171.8l1.5 1.5 .3 .1h25.1l.3-.1M69.6 166.6h.3"/>
<path d="M70 166.2h.2M72.1 168.5l.2-.1h.6l.1 2.2h-.7l-.2-.2zM72.1 170.3h.9M72.1 168.8h.8M72.1 169.9h.9M72.1 169.6h.9M72.1 169.2h.8M72.2 168.4h.7M72.9 162.5h2.5M72.9 163.7h2.5M72.9 161.2h2.5M72.9 168.8h2.5"/>
<path d="M72.9 163.2v1h-3.1l-.2 .1-1.8 1.8h-2.1l-.3-.3M73 160.6l-.1-2.4 .1-.2 .3-.2h1.7l.3 .2 .1 1.1-.1 1.5M73 160.6l-.1 2.6M74.1 168.8h.1M74.1 161.7h.1M74.1 163.6h.1M74.1 163.2h.1M74.1 162.8h.1M74.1 162.5h.1M74.1 162.1h.1M74.1 161.3h.1M74.1 161h.1"/>
<path d="M74.1 160.6h.1M74.1 160.2h.1M75.2 166.9v1.3M75.2 166.9h6.4M75.2 168.2l.2 .2-.1 1.1M75.2 168.2h.1M75.3 160.6v2.6M75.3 160.6h2.8M75.3 169.5v1.1h7.2v-1.1M75.3 170.3h7.2M75.3 165.8h5.2M75.3 169.9h7.2"/>
<path d="M75.3 169.6h7.2M75.3 168.1h7.2M75.3 167.7h7.2M75.3 167.3h7.2M75.3 166.6h5.9M75.3 166.2h5.5M75.3 165.4h4.8M75.3 165.1h4.4M75.3 164.7h4M75.3 164.3l-.1 2.6M75.3 163.2v1.1M75.3 164.3h3.7"/>
<path d="M75.3 163.2h2.8M75.3 161.7h2.8M75.4 163.9h3.2M75.4 168.4h7.1M75.4 168.8h7.1M75.4 169.2h7.1M75.4 163.6h2.8M75.4 162.8h2.7M75.4 162.5h2.7M75.4 162.1h2.7M75.4 161.3h2.7M75.4 161h2.7"/>
<path d="M75.4 160.2h2.7M78.2 163.6l3.4 3.4 .9 .1v1.1M79.7 161.7h2.8M79.7 162.5h2.8M79.7 162.1h2.8M79.7 161.3h2.8M79.7 161h2.8M79.7 160.6h2.8M79.7 160.2h2.8M79.8 162.8h2.7M80.1 163.2h2.4M80.5 163.6h2"/>
<path d="M80.9 163.9h1.6M81.3 164.3h1.2M81.4 166.8h.1M81.6 164.7h.9M82 165.1h.5M82.4 165.4h.1M82.5 162.5h2.4M82.5 161.2h2.4M82.5 168.8h2.4M82.5 170.1h2.4M82.5 163.2v1.1M82.5 160.6v-2.4v-.2l.3-.2h1.7l.3 .2 .1 .2-.1 2.4"/>
<path d="M82.5 160.6v2.6M82.5 168.2h.1M82.5 168.2v1.3M82.5 163.2h.1M83.7 168.8v1.3M83.7 161.7h.1M83.7 169.9h.1M83.7 169.6h.1M83.7 169.2h.1M83.7 162.5h.1M83.7 162.1h.1M83.7 161.3h.1"/>
<path d="M83.7 161h.1M83.7 160.6h.1M83.7 160.2h.1M84.8 168.2l.1 .2v1.1M84.8 168.2h.1M84.8 160.6v2.6M84.8 160.6h9.5M84.8 164.3v1.2h1.4l2.1-2.2a1.36 1.36 0 0 1 .9-1.4 1.36 1.36 0 0 1 1.6 .4h.7a1.37 1.37 0 0 1 2-.2 1.37 1.37 0 0 1 0 2 1.37 1.37 0 0 1-2-.2h-.7l-.4 .4-.4 .2h-.5l-1.5 1.5a1.25 1.25 0 0 1-.2 2 1.25 1.25 0 0 1-1.9-.9h-1.1v1.1M84.8 163.2v1.1M84.8 163.9h2.9M84.8 168.1h1.9M84.8 167.7h1.4"/>
<path d="M84.8 167.3h1.2M84.8 165.4h1.4M84.8 165.1h1.8M84.8 164.7h2.2M84.8 164.3h2.5M84.8 163.6h3.3M84.8 163.2h3.5M84.9 169.5v1.1h1.6l-.4-.5-.2-.5M84.9 169.6h1M84.9 161.7h9.5M84.9 170.3h1.3M84.9 168.4h1.5"/>
<path d="M84.9 168.8h1.1M84.9 169.9h1.1M84.9 169.2h1M84.9 162.8h3.4M84.9 162.5h3.6M84.9 162.1h3.9M84.9 161.3h10.1M84.9 161h9.8M84.9 160.2h9.3M85.9 169.5h2.5M85.9 169.4h2.5M87.1 168.2v1.3"/>
<path d="M87.1 168.4h.1M87.1 168.8h.1M87.1 169.2h.1M87.2 168.2v1.3M87.6 168.1h3.7M87.9 168.4h2.9M88.1 170.3h.3M88.1 165.8h6.3M88.1 167.7h6.1M88.2 166.2h6.8M88.2 168.8l.2 .8M88.2 168.8a1.28 1.28 0 0 0-1.5-.6 1.28 1.28 0 0 0-.8 1.4"/>
<path d="M88.3 168.8h2.2M88.3 167.3h5.9M88.3 166.6h6.3M88.3 169.9h.3M88.4 166.9h5.9M88.4 169.2h1.7M88.4 169.6h.6M88.5 165.4h5.7M88.9 165.1h5.3M89.3 164.7h4.9M90.3 164.3h1.6M90.6 162.1h1.1"/>
<path d="M93.2 164.3h1.1M93.4 162.1h.8M93.6 163.9h1.2M93.7 162.5h.5M93.8 163.6h1M93.9 162.8h.3M93.9 163.2h.5M94.2 167.3l.1 .7h-2.9l-.3 .1-1.2 1.3a1.29 1.29 0 0 0-1.6 1.2h-.5l.4-.5 .2-.5M94.2 167.3a1.25 1.25 0 0 1 .9-1 1.25 1.25 0 0 1 1.3 .5l.4 .1 1 .9M94.3 164.3a1.27 1.27 0 0 0 1.1 2 1.27 1.27 0 0 0 1.1-2M94.3 164.3a1.29 1.29 0 0 1 2.2 0M95.8 166.2h6.8"/>
<path d="M95.8 161.3h6.8M96 163.6h6.4M96.1 163.9h6.3M96.2 166.6h6.1M96.2 161h6.1M96.4 165.8h5.7M96.4 161.7h5.6M96.5 164.3h5.5M96.5 163.2h5.5M96.5 160.6h5.4M96.5 173.3h52.2M96.6 165.4h5.3"/>
<path d="M96.6 162.1h5.3M96.6 164.7h5.2M96.6 162.8h5.2M96.6 165.1h5.2M96.6 162.5h5.2M96.6 160.2h5.2M96.9 166.9h5M96.9 172.9h51.7M97.3 172.6h51.2M97.3 167.3h4.5M97.6 172.2h50.9M97.6 167.7h4.2"/>
<path d="M97.8 167.8l.2 .2M97.8 167.8h.1M98 171.8l-1.5 1.5M98 168l.1 .4v3.1l-.1 .3M98 171.8h50.6M98 168.1h3.9M98.1 170.3h3.7M98.1 168.4h4M98.1 168.8h9.7M98.1 171.4h50.6M98.1 171h3.7M98.1 170.7h3.7"/>
<path d="M98.1 169.9h3.7M98.1 169.6h3.7M98.1 169.2h3.7M101.8 167.3a1.27 1.27 0 0 1 1.2-1 1.27 1.27 0 0 1 1.3 1M101.8 167.3a1.25 1.25 0 0 0 1 1.5M102 163.2a1.26 1.26 0 0 1 .8-2 1.26 1.26 0 0 1 1.4 1.7l6.1 6.1h1.7l.3-.3 .5-.2M102 164.3a1.27 1.27 0 0 0 .5 1.9 1.27 1.27 0 0 0 1.8-.9M102 163.2l.8 .6-.5 .2-.3 .3M102 168.8h2l.3 .3v2l-.3 .2h-2l-.2-.2v-2zM103.5 166.2h1.7M103.5 161.3h.4M103.8 166.6h1.8"/>
<path d="M103.9 168.4h3.6M104 165.8h.9M104 161.7h.3M104.1 166.9h1.9M104.2 168.1h2.9M104.2 165.4h.3M104.2 162.1h.4M104.2 162.8h1.2M104.3 170.3h5M104.3 165.2v.1M104.3 167.3a1.25 1.25 0 0 1-1 1.5M104.3 165.2l5.2 5.3 .3 .1h2.2a1.36 1.36 0 0 0 1.7 .5 1.36 1.36 0 0 0 .7-1.6"/>
<path d="M104.3 171h8.3M104.3 170.7h7.8M104.3 169.9h4.7M104.3 169.6h4.3M104.3 169.2h3.9M104.3 167.7h2.4M104.3 167.3h2M104.3 162.5h.7M104.5 163.2h1.2M104.9 163.6h1.2M105.1 160.2h1.5M105.3 163.9h1.2"/>
<path d="M105.4 160.6h1.6M105.6 164.3h1.3M105.8 161h1.5M106 164.7h1.3M106.2 161.3h1.5M106.4 165.1h1.2M106.6 161.7h1.5M106.8 165.4h1.2M106.9 162.1h1.5M107.1 165.8h1.3M107.3 162.5h1.5M107.5 166.2h1.3"/>
<path d="M107.7 162.8h1.5M107.9 166.6h1.2M108.1 163.2h1.5M108.3 166.9h1.2M108.4 163.6h18.7M108.6 167.3h1.3M108.8 163.9h4M108.9 160.2h1.5M109 167.7h1.3M109.2 164.3h2.9M109.2 160.6h1.5M109.3 162.9l-4.7-4.7h-.6a1.26 1.26 0 0 1-1.9 .1 1.26 1.26 0 0 1 0-1.8 1.26 1.26 0 0 1 1.9 .1h1.1l.3 .1 4.9 5h17l.3 .1 2.1 2.1"/>
<path d="M109.3 162.9v.1M109.3 162.9l.5 .4h17l1.4 1.4v1.1M109.4 168.1h1.2M109.6 164.7h2.2M109.6 161h44.3M109.8 168.4h13.5M109.9 165.1h1.8M110 161.3h43.9M110.2 168.8h2M110.3 165.4h1.4M110.6 160.4h.1M110.7 165.8h1.1"/>
<path d="M111.1 166.2h.9M111.4 166.6h1.1M111.7 165.4h2.8M111.7 165.4l.1 .4M112.8 163.9h.6M112.8 163.9a1.44 1.44 0 0 0-1.1 1.3h2.8a1.37 1.37 0 0 0-1.1-1.3M113.1 165.8h.1M113.1 163.9v2.8a1.38 1.38 0 0 1-1.3-.9M113.1 166.6h.1M113.1 166.2h.1M113.1 165.4h.1M113.1 165.1h.1"/>
<path d="M113.1 164.7h.1M113.1 164.3h.1M113.2 163.9v2.8a1.38 1.38 0 0 0 1.2-.9M113.4 168.5l.5 .2 .3 .4 .2 .4M113.4 163.9h12.1M113.6 171h5.5M113.7 166.6h5.4M114 168.8h4.7M114.1 164.3h4.6M114.2 170.7h4.4M114.2 166.2h4.4M114.3 169.2h4.1"/>
<path d="M114.4 170.3h3.9M114.4 164.7h4M114.4 165.8h4M114.4 169.9h3.9M114.4 169.6h3.9M114.5 165.1h3.8M114.5 165.4l-.1 .4M114.5 165.4h3.8M118.3 169.5a1.37 1.37 0 0 0 1.3 1.7 1.37 1.37 0 0 0 1.3-1.7M119.3 168.5l-.5 .2-.3 .4-.2 .4M119.9 168.5l.5 .2 .3 .4 .2 .4M120.1 166.6h5.1"/>
<path d="M120.1 171h5.2M120.5 168.8h3.1M120.5 164.3h4.3M120.6 166.2h4.1M120.6 170.7h4.2M120.8 169.2h3.2M120.8 164.7h3.7M120.8 165.8h3.7M120.9 170.3h3.6M120.9 169.9h3.6M120.9 169.6h3.5M120.9 165.4h3.5"/>
<path d="M120.9 165.1h3.5M124.1 166.9h5.1M124.4 165.4h2.8M124.4 165.4l.1 .4M124.4 167.3h5.2M124.8 167.7h5.1M124.9 164.2a1.4 1.4 0 0 1 1.5-.2 1.4 1.4 0 0 1 .8 1.2h-2.8l.1-.4zM125.2 168.1h5.1M125.6 168.4h10.4M125.8 165.8h.1M125.8 163.9v2.8a1.38 1.38 0 0 1-1.3-.9M125.8 166.6h.1"/>
<path d="M125.8 166.2h.1M125.8 165.4h.1M125.8 165.1h.1M125.8 164.7h.1M125.8 164.3h.1M125.9 163.9v2.8a1.37 1.37 0 0 0 1.3-1.3M126.1 168.5l.5 .2 .3 .4 .2 .4M126.1 163.9h1.3M126.3 171h5.5M126.4 166.6h2.4M126.7 168.8h4.7M126.8 164.3h1"/>
<path d="M126.8 170.7h4.5M126.9 166.2h1.5M127 169.2h4.1M127 170.3h4M127.1 164.7h1.1M127.1 165.8h1.1M127.1 169.9h3.9M127.1 169.6h3.9M127.2 165.1h1M127.2 165.4h1M127.4 161.7h26.5M127.9 162.1h26"/>
<path d="M128.2 165.8l.4 .5M128.2 162.5h25.7M128.6 166.3l1.9 2 .3 .1h5.1l1.2 1.2a1.38 1.38 0 0 0 1.4 1.6 1.38 1.38 0 0 0 1.3-1.7M128.6 166.3h.1M128.6 162.8h25.3M129 163.2h24.9M129.4 163.6h24.5M129.7 163.9l.2 .3v1.1l1.4 1.5h5.1l.3 .1 1.6 1.6M129.8 163.9h8.4M129.9 165.1h1.1M129.9 164.7h1.2M129.9 164.3h1.5"/>
<path d="M130 165.4h1M130.3 168h.1M130.4 165.8h.7M130.7 166.2h.6M131 169.5a1.37 1.37 0 0 0 1.3 1.7 1.37 1.37 0 0 0 1.3-1.7M131.1 166.6h.7M132 168.5l-.5 .2-.4 .4-.1 .4M132.6 168.5l.5 .2 .3 .4 .2 .4M132.8 166.6h5.1M132.8 171h5.2M133.2 168.8h3.1M133.2 164.3h4.3"/>
<path d="M133.3 166.2h4.1M133.3 170.7h4.2M133.5 169.2h3.2M133.5 164.7h3.7M133.5 170.3h3.7M133.5 165.8h3.7M133.6 169.9h3.5M133.6 169.6h3.5M133.6 165.4h3.5M133.6 165.1h3.5M136.8 166.9h17.1M137.1 165.4h2.8"/>
<path d="M137.1 167.3h16.8M137.5 167.7h16.4M137.6 164.2a1.4 1.4 0 0 1 1.5-.2 1.4 1.4 0 0 1 .8 1.2h-2.8l.1-.4zM137.9 168.1h16M138.3 168.4h15.6M138.5 165.8h.1M138.5 163.9v2.8a1.37 1.37 0 0 1-1.4-1.3M138.5 166.6h.1M138.5 166.2h.1M138.5 165.4h.1M138.5 165.1h.1M138.5 164.7h.1"/>
<path d="M138.5 164.3h.1M138.5 163.9v2.8a1.32 1.32 0 0 0 1.3-.9M138.8 168.5l.5 .2 .3 .4 .2 .4M138.8 163.9h15.1M139 171h5.5M139.1 166.6h5.4M139.4 168.8h4.7M139.5 164.3h4.6M139.5 170.7h4.5M139.6 166.2h4.4M139.7 169.2h4.1M139.7 170.3h4"/>
<path d="M139.7 164.7h4.1M139.8 165.8h3.9M139.8 169.9h3.8M139.8 169.6h3.8M139.9 165.1h3.7M139.9 165.4l-.1 .4M139.9 165.4h3.7M143.6 169.5a1.38 1.38 0 0 0 1.4 1.7 1.38 1.38 0 0 0 1.3-1.7M144.7 168.5l-.5 .2-.4 .4-.2 .4M145.3 168.5l.5 .2 .3 .4 .2 .4M145.4 160.6h8.5M145.5 166.6h8.4"/>
<path d="M145.5 171h3.3M145.8 160.2h8.1M145.9 168.8h8M145.9 164.3h8M146 166.2h7.9M146 170.7h3M146.2 169.2h7.7M146.2 164.7h7.7M146.2 170.3h3M146.2 165.8h7.7M146.3 169.9h3.4M146.3 169.6h4"/>
<path d="M146.3 165.4h7.6M146.3 165.1h7.6M148.5 172.3h.1M148.5 172.3l.2 1.1M148.7 171.3h.1M148.7 173.4h.1M148.7 171.3l-.2 1M148.7 173.4l.5 .9M149.2 170.3h.1M149.2 174.3h.1M149.2 170.3l-.5 1M150 169.7l1-.4h1.1l1 .4"/>
<path d="M150 169.7h.1M150 169.7l-.8 .6M152.9 169.6h1M153.1 169.7l.8 .6M153.1 169.7h.1M153.5 169.9h.4M153.9 170.3h.1"/>
<circle cx="78.9" cy="134.6" r="1.37"/>
<circle cx="81.8" cy="156.1" r="1.37"/>
<circle cx="95.4" cy="157.4" r="1.26"/>
<circle cx="106.2" cy="152.3" r="1.28"/>
<circle cx="95.4" cy="162.5" r="1.26"/>
<circle cx="119.6" cy="165.3" r="1.37"/>
<circle cx="132.3" cy="165.3" r="1.37"/>
<circle cx="145" cy="165.3" r="1.37"/>
</g>
<g fill="none" stroke="#800000" stroke-width=".83">
<path d="M141.7 139.6l3.9 3.8v2.8M152.5 138.4h-7l-1.2-1.3h-4.5l-.9 .9v4.5l-2.9 2.9M63.7 158.7h10.4M68.7 144.1l3.2 3.2v11.4l1.3 1.3h.9M70.7 158.7l.9 .9M71.6 158.7v4.4l.6 .6h4.2l1.2 1.3v3.8M71.6 160l1.3 1.2h1.2M76.4 144.1l4.4 4.4h1M85.9 158.1l-.7 .6h-1.5M85.9 159.3l-.7 .7h-1.5M89.7 154.9v2.8M103 157.4h1.9l5.1 5.1h17.1l2 1.9v1.3l1.9 1.9h5.2l2.3 2.2"/>
<path d="M103 160h.7l7.6 7.6h12.2l2.3 2.2M103 152.3h3.2l5.7 5.8h27.9l.7-.7M112.9 156.1h11.1M116.4 144.4h.5M116.4 144.4l-2.8 2.8v3.2M116.4 144.4v2.5l4.1 4.2h2.2M123 143.4l1.7 2h2.2M128.6 145.4v6.1l-1.6 1.6M130.3 145.4v7.6l-2.4 2.4v2.5l.2 .2M132 145.4v2.3l3.4 3.4v2.5l-2.5 2.5h-1.3M133.7 145.4h2.3M136 145.4v2.3l9.5 9.5v2.1l-.6 .7h-33.6l-5.1-5.1h-5.7l-5.1-5.1h-1.3l-3.1 3.2h-10.2l-1.9 1.9v8.2l3.2 3.2h4.4"/>
<path d="M152.5 143.4h-4.1l-6.7 6.7v-.6M71.6 161.5l1 1h1.5M74.1 168.8h12l.7 .7h.3M74.1 167.6h-2.2l-.6 .6v2.5l.6 .7h17.1l2.6-2.6h2.5l1.3 1.3M74.1 166.3h-2.8l-1.3 1.3v3.8l1.3 1.2h24.7l1.3-1.2v-2.9l-.9-.9h-1M74.1 165h-4.1l-1.9 1.9h-2.8l-1.6-1.6M83.7 162.5h1.5l.7-.7v-5.3l1.6-1.6h9.5l2.2 2.2v13.6l2.2 2.3h38.4l1.9-2v-2.4l-3.2-3.3M85.9 160.6l-.7 .6h-1.5M85.9 168.8l-1.3 1.3h-.9M86.5 166.3l.6 .6M92.5 163.1h-2.8l-3.2 3.2M92.5 170.7l1.9 1.9"/>
<path d="M103 162.5h-.3l7.3 7.3h3.1"/>
</g>
<g fill="none" stroke="#800000" stroke-width=".32">
<path d="M71.3 134.6l6.7 6.7h3.8M95.4 139.6l1.6 1.6v3.8l-1 1h-4.4l-.6 .6v2.2l-1.3 1.3M103.8 135.7h-10l-4.8 4.8v2.3l-.3 .3h-1.2l-.4-.3v-1M106.2 136.8l-1.9-1.9h-11.1l-4.8 4.8v2.1M81.8 144.1h5.9l.7 .6M81.8 141.3l3.4-3.4h2.1l.5 .5v3.4M81.8 141.3v4.1M83.3 152.9l.1 .1M84.3 145.4h1.9l.9 .9v6.7M84.3 142.5l.3 .3h2.5M88.4 144.7v3.8h1.9l.1-.9M89.7 141.8v1.6"/>
<path d="M90.4 141.8v1l-2 1.9M95.4 144.7h-3.7l-2 2v.9M95.4 142.2l-1.9 1.9h-1.9l-2.6 2.5v1M95.4 147.3l-4.8 4.7h-2.8v-4.4"/>
</g>
<path d="M104.9 136.8v11.4M106.2 147.3l5.9 5.8h.1" fill="none" stroke="#800000" stroke-width=".51"/>
<path d="M104.9 148.2l8 7.9M112.2 153.1h14.8" fill="none" stroke="#800000" stroke-width=".61"/>
<circle cx="121.8" cy="148.3" r=".7" fill="#008000" stroke="#008000" stroke-width=".18"/>
<circle cx="121.8" cy="148.3" r=".44" fill="#fff" stroke="#000" stroke-width=".18"/>
<path d="M121.1 145.5h1.3v1.4h-1.3z" fill="#008000" stroke="#008000" stroke-width=".18"/>
<circle cx="121.8" cy="146.2" r=".44" fill="#fff" stroke="#000" stroke-width=".18"/>
<path d="M112.7 149.5h1.7v1.8h-1.7z" fill="#008000" stroke="#008000" stroke-width=".18"/>
<circle cx="113.6" cy="150.4" r=".44" fill="#fff" stroke="#000" stroke-width=".18"/>
<circle cx="116.6" cy="150.4" r=".89" fill="#008000" stroke="#008000" stroke-width=".18"/>
<circle cx="116.6" cy="150.4" r=".44" fill="#fff" stroke="#000" stroke-width=".18"/>
<circle cx="141.7" cy="145.1" r=".97" fill="#008000" stroke="#008000" stroke-width=".18"/>
<circle cx="141.7" cy="145.1" r=".44" fill="#fff" stroke="#000" stroke-width=".18"/>
<path d="M140.8 149.1h1.9v1.9h-1.9z" fill="#008000" stroke="#008000" stroke-width=".18"/>
<circle cx="141.7" cy="150.1" r=".44" fill="#fff" stroke="#000" stroke-width=".18"/>
<circle cx="141.7" cy="134.6" r=".97" fill="#008000" stroke="#008000" stroke-width=".18"/>
<circle cx="141.7" cy="134.6" r=".44" fill="#fff" stroke="#000" stroke-width=".18"/>
<path d="M140.8 138.6h1.9v2h-1.9z" fill="#008000" stroke="#008000" stroke-width=".18"/>
<circle cx="141.7" cy="139.6" r=".44" fill="#fff" stroke="#000" stroke-width=".18"/>
<circle cx="124" cy="156.1" r=".85" fill="#008000" stroke="#008000" stroke-width=".18"/>
<circle cx="124" cy="156.1" r=".55" fill="#fff" stroke="#000" stroke-width=".18"/>
<circle cx="131.6" cy="156.1" r=".85" fill="#008000" stroke="#008000" stroke-width=".18"/>
<circle cx="131.6" cy="156.1" r=".55" fill="#fff" stroke="#000" stroke-width=".18"/>
<path d="M134.7 151.1h1.4" fill="none" stroke="#008000" stroke-width="1.3"/>
<circle cx="135.4" cy="151.1" r=".4" fill="#fff" stroke="#000" stroke-width=".18"/>
<path d="M122 151.1h1.4" fill="none" stroke="#008000" stroke-width="1.3"/>
<circle cx="122.7" cy="151.1" r=".4" fill="#fff" stroke="#000" stroke-width=".18"/>
<circle cx="123" cy="135.8" r=".93" fill="#008000" stroke="#008000" stroke-width=".18"/>
<circle cx="123" cy="135.8" r=".44" fill="#fff" stroke="#000" stroke-width=".18"/>
<circle cx="123" cy="143.4" r=".93" fill="#008000" stroke="#008000" stroke-width=".18"/>
<circle cx="123" cy="143.4" r=".44" fill="#fff" stroke="#000" stroke-width=".18"/>
<circle cx="116.4" cy="144.4" r="2.16" fill="#008000" stroke="#008000" stroke-width=".18"/>
<circle cx="116.4" cy="144.4" r="1.5" fill="#fff" stroke="#000" stroke-width=".18"/>
<circle cx="116.4" cy="138.5" r="2.16" fill="#008000" stroke="#008000" stroke-width=".18"/>
<circle cx="116.4" cy="138.5" r="1.5" fill="#fff" stroke="#000" stroke-width=".18"/>
<circle cx="111.7" cy="141.5" r="2.16" fill="#008000" stroke="#008000" stroke-width=".18"/>
<circle cx="111.7" cy="141.5" r="1.5" fill="#fff" stroke="#000" stroke-width=".18"/>
<circle cx="152.5" cy="146" r=".93" fill="#008000" stroke="#008000" stroke-width=".18"/>
<circle cx="152.5" cy="146" r=".51" fill="#fff" stroke="#000" stroke-width=".18"/>
<circle cx="152.5" cy="143.4" r=".93" fill="#008000" stroke="#008000" stroke-width=".18"/>
<circle cx="152.5" cy="143.4" r=".51" fill="#fff" stroke="#000" stroke-width=".18"/>
<circle cx="152.5" cy="140.9" r=".93" fill="#008000" stroke="#008000" stroke-width=".18"/>
<circle cx="152.5" cy="140.9" r=".51" fill="#fff" stroke="#000" stroke-width=".18"/>
<circle cx="152.5" cy="138.4" r=".93" fill="#008000" stroke="#008000" stroke-width=".18"/>
<circle cx="152.5" cy="138.4" r=".51" fill="#fff" stroke="#000" stroke-width=".18"/>
<circle cx="57.3" cy="146" r=".93" fill="#008000" stroke="#008000" stroke-width=".18"/>
<circle cx="57.3" cy="146" r=".51" fill="#fff" stroke="#000" stroke-width=".18"/>
<circle cx="57.3" cy="143.4" r=".93" fill="#008000" stroke="#008000" stroke-width=".18"/>
<circle cx="57.3" cy="143.4" r=".51" fill="#fff" stroke="#000" stroke-width=".18"/>
<circle cx="57.3" cy="140.9" r=".93" fill="#008000" stroke="#008000" stroke-width=".18"/>
<circle cx="57.3" cy="140.9" r=".51" fill="#fff" stroke="#000" stroke-width=".18"/>
<circle cx="57.3" cy="138.4" r=".93" fill="#008000" stroke="#008000" stroke-width=".18"/>
<circle cx="57.3" cy="138.4" r=".51" fill="#fff" stroke="#000" stroke-width=".18"/>
<circle cx="86.1" cy="134.6" r=".7" fill="#008000" stroke="#008000" stroke-width=".18"/>
<circle cx="86.1" cy="134.6" r=".4" fill="#fff" stroke="#000" stroke-width=".18"/>
<circle cx="82.5" cy="134.6" r=".7" fill="#008000" stroke="#008000" stroke-width=".18"/>
<circle cx="82.5" cy="134.6" r=".4" fill="#fff" stroke="#000" stroke-width=".18"/>
<circle cx="71.3" cy="134.6" r=".93" fill="#008000" stroke="#008000" stroke-width=".18"/>
<circle cx="71.3" cy="134.6" r=".44" fill="#fff" stroke="#000" stroke-width=".18"/>
<circle cx="78.9" cy="134.6" r=".93" fill="#008000" stroke="#008000" stroke-width=".18"/>
<circle cx="78.9" cy="134.6" r=".44" fill="#fff" stroke="#000" stroke-width=".18"/>
<circle cx="125.8" cy="165.3" r=".93" fill="#008000" stroke="#008000" stroke-width=".18"/>
<circle cx="125.8" cy="165.3" r=".51" fill="#fff" stroke="#000" stroke-width=".18"/>
<circle cx="132.3" cy="165.3" r=".93" fill="#008000" stroke="#008000" stroke-width=".18"/>
<circle cx="132.3" cy="165.3" r=".51" fill="#fff" stroke="#000" stroke-width=".18"/>
<circle cx="125.8" cy="169.8" r=".93" fill="#008000" stroke="#008000" stroke-width=".18"/>
<circle cx="125.8" cy="169.8" r=".51" fill="#fff" stroke="#000" stroke-width=".18"/>
<circle cx="132.3" cy="169.8" r=".93" fill="#008000" stroke="#008000" stroke-width=".18"/>
<circle cx="132.3" cy="169.8" r=".51" fill="#fff" stroke="#000" stroke-width=".18"/>
<path d="M140.5 156.7v1.5" fill="none" stroke="#008000" stroke-width="1.5"/>
<circle cx="140.5" cy="157.4" r=".51" fill="#fff" stroke="#000" stroke-width=".18"/>
<path d="M143 156.7v1.5" fill="none" stroke="#008000" stroke-width="1.5"/>
<circle cx="143" cy="157.4" r=".51" fill="#fff" stroke="#000" stroke-width=".18"/>
<path d="M145.5 156.7v1.5" fill="none" stroke="#008000" stroke-width="1.5"/>
<circle cx="145.5" cy="157.4" r=".51" fill="#fff" stroke="#000" stroke-width=".18"/>
<circle cx="138.5" cy="165.3" r=".93" fill="#008000" stroke="#008000" stroke-width=".18"/>
<circle cx="138.5" cy="165.3" r=".51" fill="#fff" stroke="#000" stroke-width=".18"/>
<circle cx="145" cy="165.3" r=".93" fill="#008000" stroke="#008000" stroke-width=".18"/>
<circle cx="145" cy="165.3" r=".51" fill="#fff" stroke="#000" stroke-width=".18"/>
<circle cx="138.5" cy="169.8" r=".93" fill="#008000" stroke="#008000" stroke-width=".18"/>
<circle cx="138.5" cy="169.8" r=".51" fill="#fff" stroke="#000" stroke-width=".18"/>
<circle cx="145" cy="169.8" r=".93" fill="#008000" stroke="#008000" stroke-width=".18"/>
<circle cx="145" cy="169.8" r=".51" fill="#fff" stroke="#000" stroke-width=".18"/>
<circle cx="113.1" cy="165.3" r=".93" fill="#008000" stroke="#008000" stroke-width=".18"/>
<circle cx="113.1" cy="165.3" r=".51" fill="#fff" stroke="#000" stroke-width=".18"/>
<circle cx="119.6" cy="165.3" r=".93" fill="#008000" stroke="#008000" stroke-width=".18"/>
<circle cx="119.6" cy="165.3" r=".51" fill="#fff" stroke="#000" stroke-width=".18"/>
<circle cx="113.1" cy="169.8" r=".93" fill="#008000" stroke="#008000" stroke-width=".18"/>
<circle cx="113.1" cy="169.8" r=".51" fill="#fff" stroke="#000" stroke-width=".18"/>
<circle cx="119.6" cy="169.8" r=".93" fill="#008000" stroke="#008000" stroke-width=".18"/>
<circle cx="119.6" cy="169.8" r=".51" fill="#fff" stroke="#000" stroke-width=".18"/>
<circle cx="68.7" cy="144.1" r="1.17" fill="#008000" stroke="#008000" stroke-width=".18"/>
<circle cx="68.7" cy="144.1" r=".51" fill="#fff" stroke="#000" stroke-width=".18"/>
<circle cx="76.4" cy="144.1" r="1.17" fill="#008000" stroke="#008000" stroke-width=".18"/>
<circle cx="76.4" cy="144.1" r=".51" fill="#fff" stroke="#000" stroke-width=".18"/>
<circle cx="81.8" cy="148.5" r=".93" fill="#008000" stroke="#008000" stroke-width=".18"/>
<circle cx="81.8" cy="148.5" r=".44" fill="#fff" stroke="#000" stroke-width=".18"/>
<circle cx="81.8" cy="156.1" r=".93" fill="#008000" stroke="#008000" stroke-width=".18"/>
<circle cx="81.8" cy="156.1" r=".44" fill="#fff" stroke="#000" stroke-width=".18"/>
<path d="M102.2 169.2h1.7v1.7h-1.7z" fill="#008000" stroke="#008000" stroke-width=".18"/>
<circle cx="103" cy="170.1" r=".55" fill="#fff" stroke="#000" stroke-width=".18"/>
<circle cx="103" cy="167.6" r=".85" fill="#008000" stroke="#008000" stroke-width=".18"/>
<circle cx="103" cy="167.6" r=".55" fill="#fff" stroke="#000" stroke-width=".18"/>
<circle cx="103" cy="165" r=".85" fill="#008000" stroke="#008000" stroke-width=".18"/>
<circle cx="103" cy="165" r=".55" fill="#fff" stroke="#000" stroke-width=".18"/>
<circle cx="103" cy="162.5" r=".85" fill="#008000" stroke="#008000" stroke-width=".18"/>
<circle cx="103" cy="162.5" r=".55" fill="#fff" stroke="#000" stroke-width=".18"/>
<circle cx="103" cy="160" r=".85" fill="#008000" stroke="#008000" stroke-width=".18"/>
<circle cx="103" cy="160" r=".55" fill="#fff" stroke="#000" stroke-width=".18"/>
<circle cx="103" cy="157.4" r=".85" fill="#008000" stroke="#008000" stroke-width=".18"/>
<circle cx="103" cy="157.4" r=".55" fill="#fff" stroke="#000" stroke-width=".18"/>
<circle cx="103" cy="154.9" r=".85" fill="#008000" stroke="#008000" stroke-width=".18"/>
<circle cx="103" cy="154.9" r=".55" fill="#fff" stroke="#000" stroke-width=".18"/>
<circle cx="103" cy="152.3" r=".85" fill="#008000" stroke="#008000" stroke-width=".18"/>
<circle cx="103" cy="152.3" r=".55" fill="#fff" stroke="#000" stroke-width=".18"/>
<circle cx="103" cy="149.8" r=".85" fill="#008000" stroke="#008000" stroke-width=".18"/>
<circle cx="103" cy="149.8" r=".55" fill="#fff" stroke="#000" stroke-width=".18"/>
<circle cx="103" cy="147.3" r=".85" fill="#008000" stroke="#008000" stroke-width=".18"/>
<circle cx="103" cy="147.3" r=".55" fill="#fff" stroke="#000" stroke-width=".18"/>
<circle cx="103" cy="144.7" r=".85" fill="#008000" stroke="#008000" stroke-width=".18"/>
<circle cx="103" cy="144.7" r=".55" fill="#fff" stroke="#000" stroke-width=".18"/>
<circle cx="103" cy="142.2" r=".85" fill="#008000" stroke="#008000" stroke-width=".18"/>
<circle cx="103" cy="142.2" r=".55" fill="#fff" stroke="#000" stroke-width=".18"/>
<circle cx="103" cy="139.6" r=".85" fill="#008000" stroke="#008000" stroke-width=".18"/>
<circle cx="103" cy="139.6" r=".55" fill="#fff" stroke="#000" stroke-width=".18"/>
<circle cx="103" cy="137.1" r=".85" fill="#008000" stroke="#008000" stroke-width=".18"/>
<circle cx="103" cy="137.1" r=".55" fill="#fff" stroke="#000" stroke-width=".18"/>
<circle cx="95.4" cy="137.1" r=".85" fill="#008000" stroke="#008000" stroke-width=".18"/>
<circle cx="95.4" cy="137.1" r=".55" fill="#fff" stroke="#000" stroke-width=".18"/>
<circle cx="95.4" cy="139.6" r=".85" fill="#008000" stroke="#008000" stroke-width=".18"/>
<circle cx="95.4" cy="139.6" r=".55" fill="#fff" stroke="#000" stroke-width=".18"/>
<circle cx="95.4" cy="142.2" r=".85" fill="#008000" stroke="#008000" stroke-width=".18"/>
<circle cx="95.4" cy="142.2" r=".55" fill="#fff" stroke="#000" stroke-width=".18"/>
<circle cx="95.4" cy="144.7" r=".85" fill="#008000" stroke="#008000" stroke-width=".18"/>
<circle cx="95.4" cy="144.7" r=".55" fill="#fff" stroke="#000" stroke-width=".18"/>
<circle cx="95.4" cy="147.3" r=".85" fill="#008000" stroke="#008000" stroke-width=".18"/>
<circle cx="95.4" cy="147.3" r=".55" fill="#fff" stroke="#000" stroke-width=".18"/>
<circle cx="95.4" cy="149.8" r=".85" fill="#008000" stroke="#008000" stroke-width=".18"/>
<circle cx="95.4" cy="149.8" r=".55" fill="#fff" stroke="#000" stroke-width=".18"/>
<circle cx="95.4" cy="152.3" r=".85" fill="#008000" stroke="#008000" stroke-width=".18"/>
<circle cx="95.4" cy="152.3" r=".55" fill="#fff" stroke="#000" stroke-width=".18"/>
<circle cx="95.4" cy="154.9" r=".85" fill="#008000" stroke="#008000" stroke-width=".18"/>
<circle cx="95.4" cy="154.9" r=".55" fill="#fff" stroke="#000" stroke-width=".18"/>
<circle cx="95.4" cy="157.4" r=".85" fill="#008000" stroke="#008000" stroke-width=".18"/>
<circle cx="95.4" cy="157.4" r=".55" fill="#fff" stroke="#000" stroke-width=".18"/>
<circle cx="95.4" cy="160" r=".85" fill="#008000" stroke="#008000" stroke-width=".18"/>
<circle cx="95.4" cy="160" r=".55" fill="#fff" stroke="#000" stroke-width=".18"/>
<circle cx="95.4" cy="162.5" r=".85" fill="#008000" stroke="#008000" stroke-width=".18"/>
<circle cx="95.4" cy="162.5" r=".55" fill="#fff" stroke="#000" stroke-width=".18"/>
<circle cx="95.4" cy="165" r=".85" fill="#008000" stroke="#008000" stroke-width=".18"/>
<circle cx="95.4" cy="165" r=".55" fill="#fff" stroke="#000" stroke-width=".18"/>
<circle cx="95.4" cy="167.6" r=".85" fill="#008000" stroke="#008000" stroke-width=".18"/>
<circle cx="95.4" cy="167.6" r=".55" fill="#fff" stroke="#000" stroke-width=".18"/>
<circle cx="95.4" cy="170.1" r=".85" fill="#008000" stroke="#008000" stroke-width=".18"/>
<circle cx="95.4" cy="170.1" r=".55" fill="#fff" stroke="#000" stroke-width=".18"/>
<circle cx="63.7" cy="165.3" r="1.4" fill="#008000" stroke="#008000" stroke-width=".18"/>
<circle cx="63.7" cy="165.3" r=".93" fill="#fff" stroke="#000" stroke-width=".18"/>
<circle cx="63.7" cy="152.1" r="1.4" fill="#008000" stroke="#008000" stroke-width=".18"/>
<circle cx="63.7" cy="152.1" r=".93" fill="#fff" stroke="#000" stroke-width=".18"/>
<circle cx="106.8" cy="133.3" r=".93" fill="#008000" stroke="#008000" stroke-width=".18"/>
<circle cx="106.8" cy="133.3" r=".51" fill="#fff" stroke="#000" stroke-width=".18"/>
<circle cx="104.3" cy="133.3" r=".93" fill="#008000" stroke="#008000" stroke-width=".18"/>
<circle cx="104.3" cy="133.3" r=".51" fill="#fff" stroke="#000" stroke-width=".18"/>
<circle cx="101.7" cy="133.3" r=".93" fill="#008000" stroke="#008000" stroke-width=".18"/>
<circle cx="101.7" cy="133.3" r=".51" fill="#fff" stroke="#000" stroke-width=".18"/>
<circle cx="99.2" cy="133.3" r=".93" fill="#008000" stroke="#008000" stroke-width=".18"/>
<circle cx="99.2" cy="133.3" r=".51" fill="#fff" stroke="#000" stroke-width=".18"/>
<circle cx="96.7" cy="133.3" r=".93" fill="#008000" stroke="#008000" stroke-width=".18"/>
<circle cx="96.7" cy="133.3" r=".51" fill="#fff" stroke="#000" stroke-width=".18"/>
<circle cx="89.7" cy="157.7" r=".93" fill="#008000" stroke="#008000" stroke-width=".18"/>
<circle cx="89.7" cy="157.7" r=".44" fill="#fff" stroke="#000" stroke-width=".18"/>
<circle cx="89.7" cy="150.1" r=".93" fill="#008000" stroke="#008000" stroke-width=".18"/>
<circle cx="89.7" cy="150.1" r=".44" fill="#fff" stroke="#000" stroke-width=".18"/>
<circle cx="89.7" cy="170.7" r=".93" fill="#008000" stroke="#008000" stroke-width=".18"/>
<circle cx="89.7" cy="170.7" r=".44" fill="#fff" stroke="#000" stroke-width=".18"/>
<circle cx="89.7" cy="163.1" r=".93" fill="#008000" stroke="#008000" stroke-width=".18"/>
<circle cx="89.7" cy="163.1" r=".44" fill="#fff" stroke="#000" stroke-width=".18"/>
<circle cx="92.5" cy="163.1" r=".93" fill="#008000" stroke="#008000" stroke-width=".18"/>
<circle cx="92.5" cy="163.1" r=".44" fill="#fff" stroke="#000" stroke-width=".18"/>
<circle cx="92.5" cy="170.7" r=".93" fill="#008000" stroke="#008000" stroke-width=".18"/>
<circle cx="92.5" cy="170.7" r=".44" fill="#fff" stroke="#000" stroke-width=".18"/>
<circle cx="87.1" cy="166.9" r=".83" fill="#008000" stroke="#008000" stroke-width=".18"/>
<circle cx="87.1" cy="166.9" r=".44" fill="#fff" stroke="#000" stroke-width=".18"/>
<circle cx="87.1" cy="169.5" r=".83" fill="#008000" stroke="#008000" stroke-width=".18"/>
<circle cx="87.1" cy="169.5" r=".44" fill="#fff" stroke="#000" stroke-width=".18"/>
<circle cx="84.3" cy="145.4" r=".83" fill="#008000" stroke="#008000" stroke-width=".18"/>
<circle cx="84.3" cy="145.4" r=".44" fill="#fff" stroke="#000" stroke-width=".18"/>
<circle cx="81.8" cy="145.4" r=".83" fill="#008000" stroke="#008000" stroke-width=".18"/>
<circle cx="81.8" cy="145.4" r=".44" fill="#fff" stroke="#000" stroke-width=".18"/>
<circle cx="84.3" cy="142.5" r=".83" fill="#008000" stroke="#008000" stroke-width=".18"/>
<circle cx="84.3" cy="142.5" r=".44" fill="#fff" stroke="#000" stroke-width=".18"/>
<circle cx="81.8" cy="142.5" r=".83" fill="#008000" stroke="#008000" stroke-width=".18"/>
<circle cx="81.8" cy="142.5" r=".44" fill="#fff" stroke="#000" stroke-width=".18"/>
<circle cx="106.2" cy="152.3" r=".83" fill="#008000" stroke="#008000" stroke-width=".18"/>
<circle cx="106.2" cy="152.3" r=".44" fill="#fff" stroke="#000" stroke-width=".18"/>
<circle cx="106.2" cy="154.9" r=".83" fill="#008000" stroke="#008000" stroke-width=".18"/>
<circle cx="106.2" cy="154.9" r=".44" fill="#fff" stroke="#000" stroke-width=".18"/>
<g fill="#800000" stroke="#800000" stroke-width=".18">
<path d="M56 170.5a2.88 2.88 0 0 1 4.6 .2 2.88 2.88 0 0 1-1.5 4.3 2.88 2.88 0 0 1-3.7-2.7h2.5a.35 .35 0 0 1 .5-.4 .35 .35 0 0 1 .1 .6 .35 .35 0 0 1-.6-.1l-2.5-.1 .1-.6z" fill-rule="evenodd"/>
<path d="M56 130.9a2.89 2.89 0 0 1 4.7 .1 2.89 2.89 0 0 1-1.5 4.4 2.89 2.89 0 0 1-3.8-2.7h2.5a.35 .35 0 0 1 .5-.4 .35 .35 0 0 1 .1 .6 .35 .35 0 0 1-.6-.2h-2.5l.1-.7z" fill-rule="evenodd"/>
<path d="M149.3 130.9a2.88 2.88 0 0 1 4.7 .1 2.88 2.88 0 0 1-1.6 4.4 2.88 2.88 0 0 1-3.7-2.7h2.5a.35 .35 0 0 1 .6-.3 .35 .35 0 0 1 0 .6 .35 .35 0 0 1-.6-.3h-2.5l.3-1.3z" fill-rule="evenodd"/>
<path d="M149.8 170.1a2.89 2.89 0 0 1 4.4 .9 2.89 2.89 0 0 1-2 4.1 2.89 2.89 0 0 1-3.5-2.8h2.5a.35 .35 0 0 1 .6-.2 .35 .35 0 0 1 0 .6 .35 .35 0 0 1-.6-.3l-2.5-.1a2.87 2.87 0 0 1 1.1-2.2z" fill-rule="evenodd"/>
</g>
<g fill="none" stroke="#505050" stroke-width=".18">
<path d="M74.4 136.1h.3M74.4 135.7l.1-.1v.5M74.7 133.3h.1M74.8 133.3l.2-.2-.3-.1v.5M74.8 133.3l.2 .2M75 135.7a.2 .2 0 0 1 .2 .2 .2 .2 0 0 1-.2 .2zM75.2 135.7l-.2 .3M75.3 133l-.1 .4h.3M75.4 133.3v.2M75.5 135.6v.5M75.6 135.8l.2 .3M75.8 135.6l-.3 .3"/>
<path d="M82.8 132.4l.1 .4 .2 .1 2.2 .1 .2 .1v.2l-.2 .1-1.8 .1v.2l.2 .1h1l.2 .2-.2 .2-.8 .1 .1 .2 .6 .1 .1 .3-.9 .1-.1 .3 1.3 .1 .1 .2-.2 .2h-1.5l-.1 .2 .2 .2h1.9l.3 .2 .1 .3M94.8 139.1h.7v1.1h-.7zM94.8 136.5h.7v1.2h-.7zM95.5 136.2h7.5v34.8h-7.5zM103 136.5h.6v1.2h-.6zM103 139.1h.6v1.1h-.6zM107.5 134.7v.5h-.2M107.8 134.9l.2-.1-.2 .4h.2M113.1 131.9h.2v-.2l-.2-.1v.5M113.6 131.7h.3v.4h-.3zM114.2 131.6l.1 .5 .1-.3 .1 .3 .1-.5M114.9 131.8h.1"/>
<path d="M115.1 131.6h-.2v.5h.2M115.4 131.9h.1M115.5 131.9l.1-.2-.2-.1v.5M115.5 131.9l.1 .2M115.9 132.2h.2M116.4 131.6v.4l-.1 .1M116.7 132.1l.2-.5 .1 .5M116.8 132h.2M117.1 132.7v.3l-.2 .1M117.4 133.1h.3M117.4 132.8l.1-.1v.4M117.5 131.6l-.2 .1v.4h.2"/>
<path d="M117.8 131.6v.5M117.9 131.8l.1 .3M118 131.6l-.2 .3M121.5 139.5h.4M121.5 139.2l.3 .3M121.7 139.9l.1-.1 .1 .3M121.7 139.9l-.2-.1v.3M121.7 139.9v.1M121.9 139.2l-.3 .2M124.6 139.8l-.2 .1M124.6 139.4h-.5l.1 .1M124.6 139.2v.3"/>
<path d="M136 135.9v.2h.5M136 137a.21 .21 0 0 1 .3-.1 .21 .21 0 0 1 .1 .3h-.3zM136.1 137l.3 .2M136.1 136.6h.5M136.2 135.9v.2M136.4 136.4v.2M136.5 138v.3l-.5-.2 .1 .2M136.5 137.5v.3l-.5-.3 .1 .3M136.5 136.4h-.4M147 138.3l.1 .2h.3l.1-.2M147 136.8h.5l-.1 .2h-.4M147 136.2v.3"/>
<path d="M147 136.4h.5M147.1 137.4h.3l.1 .1-.4 .1zM147.5 135.7v.3l-.5-.3 .1 .3M147.6 137.8v.2M55.4 147h.4l.1 .2M55.4 146h.4a.2 .2 0 0 1-.2 .2 .2 .2 0 0 1-.2-.2zM55.5 145.9l.3 .3M55.9 146.5v.2M55.9 146.6h-.5l.1 .1M58 158.5v.4M58 159.4l.3 1.1M58.4 156.6l-.3 .8"/>
<path d="M58.8 152.7a1.61 1.61 0 0 1 1.3-.4v-.2h7.1v.2l2.8 2.8h.3v7.1h-.2l-2.9 2.9v.1h-7.1v-.2a1.65 1.65 0 0 1-1.7-1.1 1.65 1.65 0 0 1 .5-1.9 6.9 6.9 0 0 0-.5-7.7 1.53 1.53 0 0 1 .4-1.6zM59.1 155.3l-.4 .5M60.2 154.1l-.8 .7M60.5 154.7h4.6a.8 .8 0 0 1 .8 .8 .8 .8 0 0 1-.8 .8h-4.6M60.6 154.9v1.2M60.7 155v1M60.9 155.1v.8M61 153.6l-.3 .1M62.9 152v-.7h1.5v.7M63.1 152.9l-1.1 .2M63.5 156.4a1.96 1.96 0 0 0 3 .6 1.96 1.96 0 0 0 0-3 1.96 1.96 0 0 0-3 .6 1.95 1.95 0 0 1 3.3-.4 1.95 1.95 0 0 1-.9 3.2M63.5 154.9v1.2"/>
<path d="M63.6 152.8h.4M63.7 155v1M63.9 155.1v.9M65.1 153l.8 .2M65.9 159.9a1.96 1.96 0 0 1 .8 3.1 1.96 1.96 0 0 1-3.2-.4 1.96 1.96 0 0 0 3 .7 1.96 1.96 0 0 0 0-3.1 1.96 1.96 0 0 0-3 .7M66.7 153.6l.5 .3M67.7 154.3l.7 .8M68.7 155.6l.2 .3M69.4 156.9l.2 1M69.5 160l-.2 .7M69.6 158.5v.4M71 159.4v.6"/>
<path d="M71 159.7h1.2M75.2 158.1h7.4v12.6h-7.4zM76 141.5h.8M76.4 141.2v.7M80.2 152.3a.21 .21 0 0 1 .3-.1 .21 .21 0 0 1 .1 .2l-.3 .1zM80.3 151.7h.3a.18 .18 0 0 1-.2 .2 .18 .18 0 0 1-.1-.2zM80.3 152.2l.3 .2M80.3 151.7l.3 .2M80.7 152.9h-.5l.1 .1M80.7 152.7v.3M82 143.9l.1-.1a.2 .2 0 0 1 .2 .3 .2 .2 0 0 1-.3 .1zM82 141h.1a.2 .2 0 0 1 .2 .2 .2 .2 0 0 1-.3 .2z"/>
<path d="M82.2 143.9l-.2 .3M82.2 141.1l-.2 .2M82.5 141.4h.1M82.5 144.3h.1M82.8 141.1l.1-.2v.5M82.8 143.9l.1-.1v.5M82.8 144.3h.2M82.8 141.4h.2M82.9 146.4l-.2 .1v.4h.2M82.9 143.6l-.2 .1v.3h.2M83.1 152.7v-.2h-.2l-.1 .2h.5M83.1 146.5h.3l-.3 .4h.3"/>
<path d="M83.1 143.6h.3v.2h-.2M83.2 143.8l.2 .2h-.3M83.3 151.9v.3l-.4-.2 .1 .2M83.3 152.5l-.2 .1M83.4 144.2v.1l.2-.1M83.4 141.3v.1l.2-.1M83.4 141.1v.5M83.4 144v.4M83.6 144v.3M83.6 141.1v.3M83.9 144h.2M83.9 141.2h.2"/>
<path d="M84.1 143.8h-.2v.5M84.1 140.9h-.2v.5M86.6 142.4h5v4.6h-5zM86.8 142.7h4.5v4.1h-4.5zM88.3 153.6l.2-.1 .1 .3M88.3 153.7l-.1-.2-.1 .3M88.4 154.3v-.2h-.2l-.1 .2h.5M88.6 154.1l-.2 .1M90.8 153.5h.4M90.8 153.2l.3 .3M90.8 153.9a.22 .22 0 0 1 .2-.1 .22 .22 0 0 1 .2 .2h-.4zM90.9 153.8l.2 .3"/>
<path d="M91.2 154.3v.3l-.4-.2 .1 .2M91.2 153.2l-.2 .2M94.8 159.4h.7v1.1h-.7zM94.8 156.8h.7v1.2h-.7zM94.8 154.3h.7v1.1h-.7zM94.8 151.8h.7v1.1h-.7zM94.8 149.2h.7v1.1h-.7zM94.8 146.7h.7v1.1h-.7zM94.8 144.2h.7v1.1h-.7zM94.8 141.6h.7v1.1h-.7zM103 141.6h.6v1.1h-.6zM103 144.2h.6v1.1h-.6z"/>
<path d="M103 146.7h.6v1.1h-.6zM103 149.2h.6v1.1h-.6zM103 151.8h.6v1.1h-.6M103 154.3h.6v1.1h-.6M103 156.8h.6v1.2h-.6M103 159.4h.6v1.1h-.6M104.6 152.6v.2h.5M104.7 154.5a.22 .22 0 0 1 .2-.1 .22 .22 0 0 1 .2 .2h-.4zM104.8 154.4l.2 .2M104.8 153.3h.5M104.9 152.6v.2M105 153.1h.1l-.1 .2"/>
<path d="M105.1 154.1h.1M105.1 153l-.3 .1M105.1 153.6v.3M105.1 153.7h-.5l.2 .2M107.3 153.8l.1 .2 .3-.1v-.1M107.5 153.3h.2M107.6 153.2v.3l-.3-.1M124.4 140l-.1-.2h-.2v.2h.5M125.6 149.6l5.4 .1 .1-.2 1.3 .1 .2 .2v2.6l-.2 .2h-1.3l-.1-.1-5.4 .1-.1-.3zM125.7 155.2h4.2v1.9h-4.2zM125.8 149.9v2.3M127 149.9v2.3"/>
<path d="M127.1 156.1h2.2M127.8 156.1l1-.6v1.3zM127.8 155.5v1.3M131.1 149.9v2.3M132.4 149.9v2.3M136 146.4v.2h.5M136 147.5a.21 .21 0 0 1 .3-.1 .21 .21 0 0 1 .1 .2l-.3 .1zM136.1 147.4l.3 .3M136.1 147.1h.5M136.2 146.4v.2M136.4 146.9v.2M136.5 148.5v.3l-.5-.3 .1 .3"/>
<path d="M136.5 148v.2l-.5-.2 .1 .2M136.5 146.8l-.4 .1M137.9 156v2.9l.3 .3h9.6l.3-.3v-2.9M147 148.7l.1 .3 .3-.1 .1-.2M147 147.2l.5 .1-.1 .2h-.4M147 146.7v.3M147 146.8h.5M147.1 147.8h.3l.1 .2h-.4zM147.5 146.2v.3M147.5 146.3h-.5l.1 .2M147.6 148.3v.2M150.6 147h.4l.1 .2"/>
<path d="M151.1 146.6l-.5-.1v.2M56.6 161.3l.1 .6 .8 .1 .3-.2v-.5h-.7v.2M57.8 160.1v.7M57.8 160.5h-1.2l.3 .3M58.7 161.5l.2 .3M59.2 162.2l.7 .8M60.4 163.4l.5 .3M60.5 161h4.8a.8 .8 0 0 1 .8 .8 .8 .8 0 0 1-.8 .8h-4.8M60.6 161.2v1.2M60.7 161.3v1M60.9 161.4v.8M61.7 164.1l.8 .3"/>
<path d="M62.9 165.2v.8h1.5v-.7M63.5 161.2v1.2M63.6 164.5h.4M63.7 161.3v1M63.9 161.4v.8M65.6 164.2l-1 .3M66.9 163.6l-.3 .2M68.2 162.5l-.8 .8M68.9 161.5l-.3 .6M71.1 161.7h.3l.1 .2 .1-.3h.3l.2 .1 .1 .5h-1.2zM71.5 161.9v.3M71.9 160.5v.6"/>
<path d="M72.2 160.4l-1.2 .4 1.2 .4M85.6 167.2v.2h.5M85.6 169a.22 .22 0 0 1 .3-.1 .22 .22 0 0 1 .1 .3h-.2zM85.7 169l.3 .2M85.8 167.9h.5M85.8 167.2v.2M86 167.7h.1l-.1 .2M86.1 168.7h.1M86.1 167.6l-.3 .1M86.1 168.2v.3M86.1 168.3h-.5l.1 .2M88.1 166.5v.3h.2l.2-.3 .1 .1v.2"/>
<path d="M88.2 168.3l.1 .3h.3l.1-.3M88.4 167.3v-.2h-.2l-.1 .2h.5M88.6 167.1l-.2 .1M88.7 167.8v.3M88.7 168h-.5l.1 .1M90.8 166.5h.7M90.8 166.2l.3 .3M90.8 166.9a.22 .22 0 0 1 .2-.1 .22 .22 0 0 1 .2 .2l-.3 .1zM90.9 166.8l.2 .2M91 166.9a.22 .22 0 0 1 .3-.1 .22 .22 0 0 1 .1 .2l-.3 .1zM91 166.2l.3 .3M91.1 166.8l.3 .2"/>
<path d="M91.2 167.4v.2l-.4-.2 .1 .2M91.2 166.2l-.2 .2M91.5 167.4v.2l-.5-.2 .1 .2M91.5 166.2l-.3 .2M93.6 166.6l.2 .2M93.9 167.3v-.2h-.2l-.1 .2h.5M94 166.5l-.2 .3M94 166.5h.1M94 166.5l.1 .3h-.3M94.1 167.1l-.2 .1M94.8 169.5h.7v1.2h-.7zM94.8 167h.7v1.1h-.7z"/>
<path d="M94.8 164.5h.7v1.1h-.7zM94.8 161.9h.7v1.1h-.7zM98.9 171l.2-.3 .3 .1 .1 .2M103 169.5h.6v1.2h-.6M103 161.9h.6v1.1h-.6M103 164.5h.6v1.1h-.6M103 167h.6v1.1h-.6M116.2 163.8l-.2-.1v.2l.2 .2h-.2M116.5 163.7l.3 .1-.3 .1M116.5 171l-.3 .1 .3 .1M116.6 163.9l.1 .2-.2 .1M128.9 163.8h-.2l.2 .3h-.2"/>
<path d="M128.9 171l.2 .3 .1-.3M129.2 163.8l.1-.1v.5M129.2 164.2h.3M141.6 163.8h-.2l.2 .3h-.2M141.6 171l.3 .1-.3 .1M141.9 163.8h.2l-.2 .4h.2"/>
<circle cx="58.3" cy="132.6" r="2.86"/>
<circle cx="151.6" cy="132.6" r="2.86"/>
<circle cx="72.6" cy="144.1" r="6.1"/>
<circle cx="72.6" cy="144.1" r="1.27"/>
<circle cx="115.1" cy="150.4" r="3.2"/>
<circle cx="121.8" cy="147.3" r="2.03"/>
<circle cx="58.3" cy="172.3" r="2.86"/>
<circle cx="151.6" cy="172.3" r="2.86"/>
</g>
<path d="M117.6 149.2v2.5M121.1 149.2h1.3" fill="none" stroke="#505050" stroke-width=".32"/>
<g fill="none" stroke="#505050" stroke-width=".21">
<path d="M56.7 137.1h1.3l.6 .6v1.3l-.6 .6 .6 .7v1.2l-.6 .7 .6 .6v1.3l-.6 .6 .6 .7v1.2l-.6 .7h-1.3l-.7-.7v-1.2l.7-.7-.7-.6v-1.3l.7-.6-.7-.7v-1.2l.7-.7-.7-.6v-1.3zM72.3 134.6h.3M72.6 133.8h5v1.5h-5zM77.6 134.6h.3M85.8 136.9h-3a2.69 2.69 0 0 1 0-4.6h3a2.7 2.7 0 0 1 0 4.6M95.4 132.7l.6-.7h1.3l.6 .7 .7-.7h1.2l.7 .7 .6-.7h1.3l.6 .7 .7-.7h1.2l.7 .7 .6-.7h1.3l.6 .7v1.2l-.6 .7h-1.3l-.6-.7-.7 .7h-1.2l-.7-.7-.6 .7h-1.3l-.6-.7-.7 .7h-1.2l-.7-.7-.6 .7h-1.3l-.6-.7zM111.8 139v-8.1h9v13.5h-2.1M111.8 133.8h9M122.3 137.1h1.5v5.1h-1.5zM123 136.8v.3M125.2 132.5h10.2v10h-10.2zM125.2 132l1.7-.5h6.8l1.7 .5v.4h-10.2z"/>
<path d="M125.2 132.2h10.2M125.2 132h10.2M125.7 131.8h9.2M126.4 131.7h7.9M143.6 139.6h1.3M144.3 133.9v1.3M144.3 139v1.3M151.9 137.1h1.3l.6 .6v1.3l-.6 .6 .6 .7v1.2l-.6 .7 .6 .6v1.3l-.6 .6 .6 .7v1.2l-.6 .7h-1.3l-.6-.7v-1.2l.6-.7-.6-.6v-1.3l.6-.6-.6-.7v-1.2l.6-.7-.6-.6v-1.3zM81 149.8h1.5v5.1h-1.5zM81.8 149.5v.3M81.8 154.9v.2M82.1 142.5h.4"/>
<path d="M82.1 145.4h.4M82.5 141.9v1.2M82.5 144.7v1.3M83.5 142.5h.5M83.5 141.9v1.2M83.5 144.7v1.3M83.5 145.4h.5M88.9 151.4h1.5v5.1h-1.5zM89.7 151.1v.3M89.7 156.5v.2M105.6 153.1h1.2M105.6 154.1h1.2"/>
<path d="M106.2 152.6v.5M106.2 154.1v.5M111.8 143.7v.7h2.2M123 142.2v.2M143.6 150.1h1.3M144.3 144.4v1.3M144.3 149.5v1.2M86.5 167.7h1.3M86.5 168.7h1.3M87.1 167.2v.5M87.1 168.7v.5M88.9 164.4h1.5v5.1h-1.5z"/>
<path d="M89.7 164.1v.3M89.7 169.5v.2M91.8 164.4h1.5v5.1h-1.5zM92.5 164.1v.3M92.5 169.5v.2M113.3 165l.5-.5h5.1l.5 .5v5.1l-.5 .5h-5.1l-.5-.5zM113.8 166.3v.7l.4 .9M113.8 168.1v.7M126.5 164.5h5.1l.5 .5v5.1l-.5 .5h-5.1l-.5-.5v-5.1zM126.5 166.3v.7l.4 .9M126.5 168.1v.7M139.2 164.5h5.1l.5 .5v5.1l-.5 .5h-5.1l-.5-.5v-5.1z"/>
<path d="M139.2 166.3v.7l.4 .9M139.2 168.1v.7"/>
<circle cx="141.7" cy="137.1" r="5"/>
<circle cx="141.7" cy="147.6" r="5"/>
<circle cx="116.4" cy="167.6" r="1.78"/>
<circle cx="129.1" cy="167.6" r="1.78"/>
<circle cx="141.7" cy="167.6" r="1.78"/>
</g>
<g fill="#505050" stroke="#505050" stroke-width=".18">
<path d="M126.1 155.2h.5v1.9h-.5z"/>
<path d="M129.9 155.7h.6v.9h-.6z"/>
<path d="M125.1 155.7h.6v.9h-.6z"/>
<path d="M123.5 150.8h2v.6h-2z"/>
<path d="M132.6 150.8h1.9v.6h-1.9z"/>
<path d="M126.4 142.4h1v1.7h-1z"/>
<path d="M128.1 142.4h1v1.7h-1z"/>
<path d="M129.8 142.4h1v1.7h-1z"/>
<path d="M131.5 142.4h1v1.7h-1z"/>
<path d="M133.2 142.4h1v1.7h-1z"/>
<path d="M137.7 154.9h1.9v1.2h-1.9z"/>
<path d="M139.6 154.9h1.8v.7h-1.8z"/>
<path d="M141.4 154.9h.7v1.2h-.7z"/>
<path d="M142.1 154.9h1.8v.7h-1.8z"/>
<path d="M143.9 154.9h.8v1.2h-.8z"/>
<path d="M144.7 154.9h1.7v.7h-1.7z"/>
<path d="M146.4 154.9h1.9v1.2h-1.9z"/>
<path d="M67.1 158.5h2.2v.4h-2.2z"/>
<path d="M67.9 157.6h.4v2.2h-.4z"/>
<path d="M126.4 144.1h1v2.1h-1z"/>
<path d="M128.1 144.1h1v2.1h-1z"/>
<path d="M129.8 144.1h1v2.1h-1z"/>
<path d="M131.5 144.1h1v2.1h-1z"/>
<path d="M133.2 144.1h1v2.1h-1z"/>
<path d="M152.3 138.1h.5v.5h-.5z"/>
<path d="M152.3 140.7h.5v.5h-.5z"/>
<path d="M152.3 143.2h.5v.5h-.5z"/>
<path d="M152.3 145.7h.5v.5h-.5z"/>
<path d="M57.1 138.1h.5v.5h-.5z"/>
<path d="M57.1 140.7h.5v.5h-.5z"/>
<path d="M57.1 143.2h.5v.5h-.5z"/>
<path d="M57.1 145.7h.5v.5h-.5z"/>
<path d="M139.6 155.6h1.8v.5h-1.8z"/>
<path d="M142.1 155.6h1.8v.5h-1.8z"/>
<path d="M144.7 155.6h1.7v.5h-1.7z"/>
<path d="M73.8 158.5h1.3v.4h-1.3z"/>
<path d="M73.8 159.7h1.3v.5h-1.3z"/>
<path d="M73.8 161h1.3v.4h-1.3z"/>
<path d="M73.8 162.3h1.3v.4h-1.3z"/>
<path d="M73.8 163.5h1.3v.5h-1.3z"/>
<path d="M73.8 164.8h1.3v.4h-1.3z"/>
<path d="M73.8 166.1h1.3v.4h-1.3z"/>
<path d="M73.8 167.3h1.3v.5h-1.3z"/>
<path d="M73.8 168.6h1.3v.4h-1.3z"/>
<path d="M73.8 169.9h1.3v.4h-1.3z"/>
<path d="M82.7 158.5h1.3v.4h-1.3z"/>
<path d="M82.7 159.7h1.3v.5h-1.3z"/>
<path d="M82.7 161h1.3v.4h-1.3z"/>
<path d="M82.7 162.3h1.3v.4h-1.3z"/>
<path d="M82.7 163.5h1.3v.5h-1.3z"/>
<path d="M82.7 164.8h1.3v.4h-1.3z"/>
<path d="M82.7 166.1h1.3v.4h-1.3z"/>
<path d="M82.7 167.3h1.3v.5h-1.3z"/>
<path d="M82.7 168.6h1.3v.4h-1.3z"/>
<path d="M82.7 169.9h1.3v.4h-1.3z"/>
<path d="M87 147h.2v.8h-.2z"/>
<path d="M87.7 147h.2v.8h-.2z"/>
<path d="M88.3 147h.2v.8h-.2z"/>
<path d="M88.9 147h.3v.8h-.3z"/>
<path d="M89.6 147h.2v.8h-.2z"/>
<path d="M90.3 147h.2v.8h-.2z"/>
<path d="M90.9 147h.2v.8h-.2z"/>
<path d="M90.9 141.6h.2v.9h-.2z"/>
<path d="M90.3 141.6h.2v.9h-.2z"/>
<path d="M89.6 141.6h.2v.9h-.2z"/>
<path d="M88.9 141.6h.3v.9h-.3z"/>
<path d="M88.3 141.6h.2v.9h-.2z"/>
<path d="M87.7 141.6h.2v.9h-.2z"/>
<path d="M87 141.6h.2v.9h-.2z"/>
<path d="M96.4 133h.5v.5h-.5z"/>
<path d="M99 133h.5v.5h-.5z"/>
<path d="M101.5 133h.5v.5h-.5z"/>
<path d="M104 133h.5v.5h-.5z"/>
<path d="M106.6 133h.5v.5h-.5z"/>
</g>
<g fill="#505050" stroke="#505050" stroke-width=".18">
<path d="M75.7 141a.84 .84 0 0 1 1.4 .1 .84 .84 0 0 1-.5 1.2 .84 .84 0 0 1-1.1-.8h.2a.69 .69 0 0 1 .9-.6 .69 .69 0 0 1 .2 1.1 .69 .69 0 0 1-1.1-.2v-.3h-.2z" fill-rule="evenodd"/>
<path d="M81.2 169.3a.61 .61 0 0 1 1 .1 .61 .61 0 0 1-.3 .9 .61 .61 0 0 1-.8-.5h.1a.46 .46 0 0 1 .7-.4 .46 .46 0 0 1 .1 .8 .46 .46 0 0 1-.8-.3v-.1h-.1z" fill-rule="evenodd"/>
<path d="M87.1 145.5a.53 .53 0 0 1 .8 .2 .53 .53 0 0 1-.4 .8 .53 .53 0 0 1-.6-.6h.2a.38 .38 0 0 1 .5-.3 .38 .38 0 0 1 .1 .6 .38 .38 0 0 1-.6-.1v-.2h-.2z" fill-rule="evenodd"/>
<circle cx="138.4" cy="158.6" r=".25"/>
</g>
<path d="M124 156.1h1.3M130.3 156.1h1.3" fill="none" stroke="#505050" stroke-width=".87"/>
<path d="M122.7 151.1h1.1M134.3 151.1h1.1" fill="none" stroke="#505050" stroke-width=".61"/>
<g fill="none" stroke="#000" stroke-width=".18">
<path d="M74.1 134.6h2M75.1 133.5v2.1M83.3 134.6h2M84.3 133.5v2.1M94.4 137.1h2M95.4 136.1v2M105.8 133.3h2M106.8 132.3v2M115.3 130.8h2.1M116.4 129.8v2M122 139.6h2M123 138.6v2.1"/>
<path d="M129.3 139.6h2M130.3 138.6v2.1M140.7 137.1h2M141.7 136.1v2M56.3 146h2M57.3 145v2M62.7 158.7h2M63.7 157.7v2M71.5 144.1h2.1M72.6 143.1v2M80.8 152.3h2M81.8 151.3v2.1"/>
<path d="M82 145.4h2M82 142.5h2M83 141.5v2M83 144.3v2.1M88.2 144.7h1.7M88.7 153.9h2M89 143.8v1.8M89.7 152.9v2M105.2 153.6h2M106.2 152.6v2M114.1 150.4h2M115.1 149.4v2"/>
<path d="M120.7 147.3h2.1M121.8 146.2v2.1M126.8 156.1h2M127.8 155.1v2.1M128 151.1h2.1M129.1 150.1v2M140.7 147.6h2M141.7 146.6v2M142 154.9h2M143 153.9v2M151.5 146h2M152.5 145v2"/>
<path d="M77.9 164.4h2M78.9 163.4v2M86.1 168.2h2.1M87.1 167.2v2M88.7 166.9h2M89.7 165.9v2M91.5 166.9h2.1M92.5 165.9v2M115.3 167.6h2.1M116.4 166.5v2.1M128 167.6h2.1M129.1 166.5v2.1"/>
<path d="M140.7 167.6h2M141.7 166.5v2.1"/>
</g>
<g fill="none" stroke="#f90" stroke-width=".18">
<path d="M56.2 130.3a2.4 2.4 0 0 1 1.5-.5h94.4a2.26 2.26 0 0 1 2.3 2.2v40.9a2.29 2.29 0 0 1-2.3 2.3h-94.4a2.29 2.29 0 0 1-2.3-2.3v-40.8a2.31 2.31 0 0 1 .8-1.8z"/>
<circle cx="58.3" cy="172.3" r="1.5"/>
</g>
<circle cx="58.3" cy="172.3" r="1.5" fill="#fff" stroke="#000" stroke-width=".18"/>
<circle cx="58.3" cy="132.6" r="1.5" fill="none" stroke="#f90" stroke-width=".18"/>
<circle cx="58.3" cy="132.6" r="1.5" fill="#fff" stroke="#000" stroke-width=".18"/>
<circle cx="151.6" cy="132.6" r="1.5" fill="none" stroke="#f90" stroke-width=".18"/>
<circle cx="151.6" cy="132.6" r="1.5" fill="#fff" stroke="#000" stroke-width=".18"/>
<circle cx="151.6" cy="172.3" r="1.5" fill="none" stroke="#f90" stroke-width=".18"/>
<circle cx="151.6" cy="172.3" r="1.5" fill="#fff" stroke="#000" stroke-width=".18"/>
<g fill="none" stroke="#505050" stroke-width=".18">
<path d="M58.3 139.9l-2 2M58.3 137.4l-2 2M59.3 131.6l-2 2M70.3 134.6h2M71.3 133.5v2.1M77.9 134.6h2M78.9 133.5v2.1M81.5 134.6h1M82.5 134.6l1-1.1v2.1zM85 134.6h1.1M86.1 134.6l1-1.1v2.1zM96.4 136.1l-2 2"/>
<path d="M96.4 138.6l-2 2.1M97.7 132.3l-2 2M100.2 132.3l-2 2M102.8 132.3l-2.1 2M104 138.6l-2 2.1M104 136.1l-2 2M105.3 132.3l-2 2M107.8 132.3l-2 2M117.4 137.4l-2.1 2.1M122 135.8h2M123 134.8v2M140.7 134.6h2"/>
<path d="M140.7 139.6h2M141.7 133.6v2M141.7 138.6v2M152.6 131.6l-2 2M153.5 139.9l-2 2M153.5 137.4l-2 2M58.3 145l-2 2M58.3 142.4l-2 2.1M64.7 151.1l-2 2M69.8 143.1l-2.1 2M77.4 143.1l-2 2M80.8 148.5h2"/>
<path d="M80.8 156.1h2M80.8 145.4h2M80.8 142.5h2M81.8 141.5v2M81.8 144.3v2.1M81.8 147.5v2M81.8 155.1v2.1M83.3 145.4h2M83.3 142.5h2M84.3 141.5v2M84.3 144.3v2.1M88.7 157.7h2"/>
<path d="M88.7 150.1h2M89.7 149.1v2M89.7 156.7v2M96.4 156.4l-2 2M96.4 153.9l-2 2M96.4 151.3l-2 2.1M96.4 148.8l-2 2M96.4 146.2l-2 2.1M96.4 143.7l-2 2M96.4 141.2l-2 2M96.4 158.9l-2 2.1M104 158.9l-2 2.1"/>
<path d="M104 156.4l-2 2M104 153.9l-2 2M104 151.3l-2 2.1M104 148.8l-2 2M104 146.2l-2 2.1M104 143.7l-2 2M104 141.2l-2 2M105.2 152.3h2M105.2 154.9h2M106.2 151.3v2.1M106.2 153.9v2M112.5 150.4h2.1"/>
<path d="M112.7 140.4l-2.1 2.1M113.6 149.4v2M115.6 150.4h2M116.6 149.4v2M117.4 143.4l-2.1 2.1M120.7 148.3h2.1M120.7 146.2h2.1M121.8 145.2v4.1M122 143.4h2M123 142.4v2.1M123.7 150.1l-2 2M125 155.1l-2 2.1"/>
<path d="M132.6 155.1l-2 2.1M136.4 150.1l-2 2M140.7 145.1h2M140.7 150.1h2M141.5 156.4l-2 2M141.7 144.1v2M141.7 149.1v2M144 156.4l-2 2M146.6 156.4l-2.1 2M153.5 145l-2 2M153.5 142.4l-2 2.1M59.3 171.3l-2 2"/>
<path d="M64.7 164.3l-2 2M86.1 166.9h2.1M86.1 169.5h2.1M87.1 165.9v2M87.1 168.4v2.1M88.7 170.7h2M88.7 163.1h2M89.7 162.1v2M89.7 169.7v2M91.5 170.7h2.1M91.5 163.1h2.1M92.5 162.1v2"/>
<path d="M92.5 169.7v2M96.4 169.1l-2 2M96.4 164l-2 2M96.4 161.5l-2 2M96.4 166.5l-2 2.1M104 169.1l-2 2M104 166.5l-2 2.1M104 164l-2 2M104 161.5l-2 2M114.1 164.3l-2 2M114.1 168.8l-2 2M120.6 164.3l-2 2"/>
<path d="M120.6 168.8l-2 2M126.8 164.3l-2 2M126.8 168.8l-2 2M133.3 164.3l-2 2M133.3 168.8l-2 2M139.5 164.3l-2 2M139.5 168.8l-2 2M146 164.3l-2 2M146 168.8l-2 2M152.6 171.3l-2 2"/>
<circle cx="57.3" cy="138.4" r=".99"/>
<circle cx="58.3" cy="132.6" r=".99"/>
<circle cx="71.3" cy="134.6" r=".99"/>
<circle cx="78.9" cy="134.6" r=".99"/>
<circle cx="95.4" cy="137.1" r=".99"/>
<circle cx="95.4" cy="139.6" r=".99"/>
<circle cx="96.7" cy="133.3" r=".99"/>
<circle cx="99.2" cy="133.3" r=".99"/>
<circle cx="101.7" cy="133.3" r=".99"/>
<circle cx="103" cy="137.1" r=".99"/>
<circle cx="103" cy="139.6" r=".99"/>
<circle cx="104.3" cy="133.3" r=".99"/>
<circle cx="106.8" cy="133.3" r=".99"/>
<circle cx="116.4" cy="138.5" r=".99"/>
<circle cx="123" cy="135.8" r=".99"/>
<circle cx="141.7" cy="139.6" r=".99"/>
<circle cx="141.7" cy="134.6" r=".99"/>
<circle cx="151.6" cy="132.6" r=".99"/>
<circle cx="152.5" cy="138.4" r=".99"/>
<circle cx="57.3" cy="140.9" r=".99"/>
<circle cx="57.3" cy="146" r=".99"/>
<circle cx="57.3" cy="143.4" r=".99"/>
<circle cx="63.7" cy="152.1" r=".99"/>
<circle cx="68.7" cy="144.1" r=".99"/>
<circle cx="76.4" cy="144.1" r=".99"/>
<circle cx="81.8" cy="142.5" r=".99"/>
<circle cx="81.8" cy="148.5" r=".99"/>
<circle cx="81.8" cy="156.1" r=".99"/>
<circle cx="81.8" cy="145.4" r=".99"/>
<circle cx="84.3" cy="145.4" r=".99"/>
<circle cx="84.3" cy="142.5" r=".99"/>
<circle cx="89.7" cy="157.7" r=".99"/>
<circle cx="89.7" cy="150.1" r=".99"/>
<circle cx="95.4" cy="144.7" r=".99"/>
<circle cx="95.4" cy="149.8" r=".99"/>
<circle cx="95.4" cy="152.3" r=".99"/>
<circle cx="95.4" cy="157.4" r=".99"/>
<circle cx="95.4" cy="142.2" r=".99"/>
<circle cx="95.4" cy="154.9" r=".99"/>
<circle cx="95.4" cy="147.3" r=".99"/>
<circle cx="95.4" cy="160" r=".99"/>
<circle cx="103" cy="157.4" r=".99"/>
<circle cx="103" cy="154.9" r=".99"/>
<circle cx="103" cy="144.7" r=".99"/>
<circle cx="103" cy="152.3" r=".99"/>
<circle cx="103" cy="149.8" r=".99"/>
<circle cx="103" cy="142.2" r=".99"/>
<circle cx="103" cy="160" r=".99"/>
<circle cx="103" cy="147.3" r=".99"/>
<circle cx="106.2" cy="152.3" r=".99"/>
<circle cx="106.2" cy="154.9" r=".99"/>
<circle cx="111.7" cy="141.5" r=".99"/>
<circle cx="113.6" cy="150.4" r=".99"/>
<circle cx="116.4" cy="144.4" r=".99"/>
<circle cx="116.6" cy="150.4" r=".99"/>
<circle cx="121.8" cy="148.3" r=".99"/>
<circle cx="121.8" cy="146.2" r=".99"/>
<circle cx="122.7" cy="151.1" r=".99"/>
<circle cx="123" cy="143.4" r=".99"/>
<circle cx="124" cy="156.1" r=".99"/>
<circle cx="131.6" cy="156.1" r=".99"/>
<circle cx="135.4" cy="151.1" r=".99"/>
<circle cx="140.5" cy="157.4" r=".99"/>
<circle cx="141.7" cy="145.1" r=".99"/>
<circle cx="141.7" cy="150.1" r=".99"/>
<circle cx="143" cy="157.4" r=".99"/>
<circle cx="145.5" cy="157.4" r=".99"/>
<circle cx="152.5" cy="143.4" r=".99"/>
<circle cx="152.5" cy="146" r=".99"/>
<circle cx="152.5" cy="140.9" r=".99"/>
<circle cx="58.3" cy="172.3" r=".99"/>
<circle cx="63.7" cy="165.3" r=".99"/>
<circle cx="87.1" cy="166.9" r=".99"/>
<circle cx="87.1" cy="169.5" r=".99"/>
<circle cx="89.7" cy="163.1" r=".99"/>
<circle cx="89.7" cy="170.7" r=".99"/>
<circle cx="92.5" cy="163.1" r=".99"/>
<circle cx="92.5" cy="170.7" r=".99"/>
<circle cx="95.4" cy="167.6" r=".99"/>
<circle cx="95.4" cy="165" r=".99"/>
<circle cx="95.4" cy="162.5" r=".99"/>
<circle cx="95.4" cy="170.1" r=".99"/>
<circle cx="103" cy="170.1" r=".99"/>
<circle cx="103" cy="167.6" r=".99"/>
<circle cx="103" cy="165" r=".99"/>
<circle cx="103" cy="162.5" r=".99"/>
<circle cx="113.1" cy="165.3" r=".99"/>
<circle cx="113.1" cy="169.8" r=".99"/>
<circle cx="119.6" cy="169.8" r=".99"/>
<circle cx="119.6" cy="165.3" r=".99"/>
<circle cx="125.8" cy="165.3" r=".99"/>
<circle cx="125.8" cy="169.8" r=".99"/>
<circle cx="132.3" cy="169.8" r=".99"/>
<circle cx="132.3" cy="165.3" r=".99"/>
<circle cx="138.5" cy="169.8" r=".99"/>
<circle cx="138.5" cy="165.3" r=".99"/>
<circle cx="145" cy="165.3" r=".99"/>
<circle cx="145" cy="169.8" r=".99"/>
<circle cx="151.6" cy="172.3" r=".99"/>
</g>
<use href="#words"/>
</svg>
